VERSION 5.8 ;
BUSBITCHARS "[]" ;
DIVIDERCHAR "/" ;
UNITS
    DATABASE MICRONS 1000 ;
END UNITS

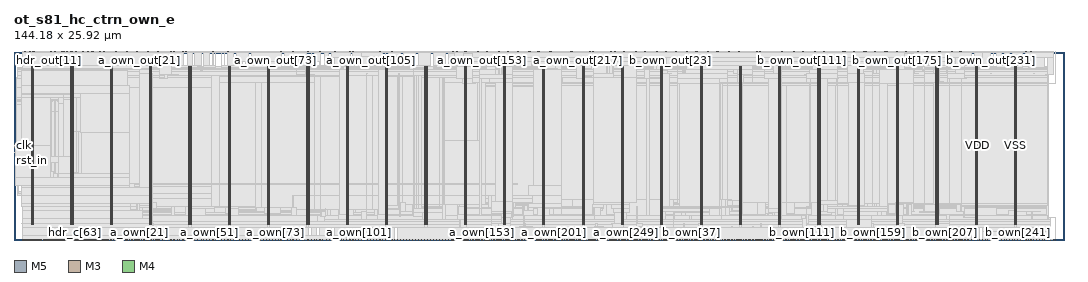
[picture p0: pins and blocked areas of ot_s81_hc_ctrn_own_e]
MACRO ot_s81_hc_ctrn_own_e
  FOREIGN ot_s81_hc_ctrn_own_e 0 0 ;
  CLASS BLOCK ;
  SIZE 144.18 BY 25.92 ;
  PIN a_own[0]
    DIRECTION INPUT ;
    USE SIGNAL ;
    PORT
      LAYER M5 ;
        RECT  13.008 0 13.032 0.084 ;
    END
  END a_own[0]
  PIN a_own[100]
    DIRECTION INPUT ;
    USE SIGNAL ;
    PORT
      LAYER M5 ;
        RECT  46.896 0 46.92 0.084 ;
    END
  END a_own[100]
  PIN a_own[101]
    DIRECTION INPUT ;
    USE SIGNAL ;
    PORT
      LAYER M3 ;
        RECT  47.304 0 47.322 0.038 ;
    END
  END a_own[101]
  PIN a_own[102]
    DIRECTION INPUT ;
    USE SIGNAL ;
    PORT
      LAYER M5 ;
        RECT  47.76 0 47.784 0.084 ;
    END
  END a_own[102]
  PIN a_own[103]
    DIRECTION INPUT ;
    USE SIGNAL ;
    PORT
      LAYER M3 ;
        RECT  48.168 0 48.186 0.038 ;
    END
  END a_own[103]
  PIN a_own[104]
    DIRECTION INPUT ;
    USE SIGNAL ;
    PORT
      LAYER M5 ;
        RECT  48.528 0 48.552 0.084 ;
    END
  END a_own[104]
  PIN a_own[105]
    DIRECTION INPUT ;
    USE SIGNAL ;
    PORT
      LAYER M3 ;
        RECT  48.96 0 48.978 0.038 ;
    END
  END a_own[105]
  PIN a_own[106]
    DIRECTION INPUT ;
    USE SIGNAL ;
    PORT
      LAYER M5 ;
        RECT  49.392 0 49.416 0.084 ;
    END
  END a_own[106]
  PIN a_own[107]
    DIRECTION INPUT ;
    USE SIGNAL ;
    PORT
      LAYER M3 ;
        RECT  49.824 0 49.842 0.038 ;
    END
  END a_own[107]
  PIN a_own[108]
    DIRECTION INPUT ;
    USE SIGNAL ;
    PORT
      LAYER M5 ;
        RECT  50.256 0 50.28 0.084 ;
    END
  END a_own[108]
  PIN a_own[109]
    DIRECTION INPUT ;
    USE SIGNAL ;
    PORT
      LAYER M3 ;
        RECT  50.58 0 50.598 0.038 ;
    END
  END a_own[109]
  PIN a_own[10]
    DIRECTION INPUT ;
    USE SIGNAL ;
    PORT
      LAYER M5 ;
        RECT  15.024 0 15.048 0.084 ;
    END
  END a_own[10]
  PIN a_own[110]
    DIRECTION INPUT ;
    USE SIGNAL ;
    PORT
      LAYER M5 ;
        RECT  51.024 0 51.048 0.084 ;
    END
  END a_own[110]
  PIN a_own[111]
    DIRECTION INPUT ;
    USE SIGNAL ;
    PORT
      LAYER M3 ;
        RECT  51.444 0 51.462 0.038 ;
    END
  END a_own[111]
  PIN a_own[112]
    DIRECTION INPUT ;
    USE SIGNAL ;
    PORT
      LAYER M5 ;
        RECT  51.888 0 51.912 0.084 ;
    END
  END a_own[112]
  PIN a_own[113]
    DIRECTION INPUT ;
    USE SIGNAL ;
    PORT
      LAYER M3 ;
        RECT  52.2 0 52.218 0.038 ;
    END
  END a_own[113]
  PIN a_own[114]
    DIRECTION INPUT ;
    USE SIGNAL ;
    PORT
      LAYER M5 ;
        RECT  52.656 0 52.68 0.084 ;
    END
  END a_own[114]
  PIN a_own[115]
    DIRECTION INPUT ;
    USE SIGNAL ;
    PORT
      LAYER M3 ;
        RECT  53.064 0 53.082 0.038 ;
    END
  END a_own[115]
  PIN a_own[116]
    DIRECTION INPUT ;
    USE SIGNAL ;
    PORT
      LAYER M5 ;
        RECT  53.52 0 53.544 0.084 ;
    END
  END a_own[116]
  PIN a_own[117]
    DIRECTION INPUT ;
    USE SIGNAL ;
    PORT
      LAYER M3 ;
        RECT  53.856 0 53.874 0.038 ;
    END
  END a_own[117]
  PIN a_own[118]
    DIRECTION INPUT ;
    USE SIGNAL ;
    PORT
      LAYER M5 ;
        RECT  54.288 0 54.312 0.084 ;
    END
  END a_own[118]
  PIN a_own[119]
    DIRECTION INPUT ;
    USE SIGNAL ;
    PORT
      LAYER M3 ;
        RECT  54.72 0 54.738 0.038 ;
    END
  END a_own[119]
  PIN a_own[11]
    DIRECTION INPUT ;
    USE SIGNAL ;
    PORT
      LAYER M3 ;
        RECT  15.264 0 15.282 0.038 ;
    END
  END a_own[11]
  PIN a_own[120]
    DIRECTION INPUT ;
    USE SIGNAL ;
    PORT
      LAYER M5 ;
        RECT  55.152 0 55.176 0.084 ;
    END
  END a_own[120]
  PIN a_own[121]
    DIRECTION INPUT ;
    USE SIGNAL ;
    PORT
      LAYER M3 ;
        RECT  55.476 0 55.494 0.038 ;
    END
  END a_own[121]
  PIN a_own[122]
    DIRECTION INPUT ;
    USE SIGNAL ;
    PORT
      LAYER M5 ;
        RECT  55.92 0 55.944 0.084 ;
    END
  END a_own[122]
  PIN a_own[123]
    DIRECTION INPUT ;
    USE SIGNAL ;
    PORT
      LAYER M3 ;
        RECT  56.34 0 56.358 0.038 ;
    END
  END a_own[123]
  PIN a_own[124]
    DIRECTION INPUT ;
    USE SIGNAL ;
    PORT
      LAYER M5 ;
        RECT  56.784 0 56.808 0.084 ;
    END
  END a_own[124]
  PIN a_own[125]
    DIRECTION INPUT ;
    USE SIGNAL ;
    PORT
      LAYER M3 ;
        RECT  57.204 0 57.222 0.038 ;
    END
  END a_own[125]
  PIN a_own[126]
    DIRECTION INPUT ;
    USE SIGNAL ;
    PORT
      LAYER M5 ;
        RECT  57.552 0 57.576 0.084 ;
    END
  END a_own[126]
  PIN a_own[127]
    DIRECTION INPUT ;
    USE SIGNAL ;
    PORT
      LAYER M3 ;
        RECT  57.96 0 57.978 0.038 ;
    END
  END a_own[127]
  PIN a_own[128]
    DIRECTION INPUT ;
    USE SIGNAL ;
    PORT
      LAYER M5 ;
        RECT  58.416 0 58.44 0.084 ;
    END
  END a_own[128]
  PIN a_own[129]
    DIRECTION INPUT ;
    USE SIGNAL ;
    PORT
      LAYER M3 ;
        RECT  58.824 0 58.842 0.038 ;
    END
  END a_own[129]
  PIN a_own[12]
    DIRECTION INPUT ;
    USE SIGNAL ;
    PORT
      LAYER M5 ;
        RECT  15.504 0 15.528 0.084 ;
    END
  END a_own[12]
  PIN a_own[130]
    DIRECTION INPUT ;
    USE SIGNAL ;
    PORT
      LAYER M5 ;
        RECT  59.184 0 59.208 0.084 ;
    END
  END a_own[130]
  PIN a_own[131]
    DIRECTION INPUT ;
    USE SIGNAL ;
    PORT
      LAYER M3 ;
        RECT  59.616 0 59.634 0.038 ;
    END
  END a_own[131]
  PIN a_own[132]
    DIRECTION INPUT ;
    USE SIGNAL ;
    PORT
      LAYER M5 ;
        RECT  60.048 0 60.072 0.084 ;
    END
  END a_own[132]
  PIN a_own[133]
    DIRECTION INPUT ;
    USE SIGNAL ;
    PORT
      LAYER M3 ;
        RECT  60.264 0 60.282 0.038 ;
    END
  END a_own[133]
  PIN a_own[134]
    DIRECTION INPUT ;
    USE SIGNAL ;
    PORT
      LAYER M5 ;
        RECT  60.432 0 60.456 0.084 ;
    END
  END a_own[134]
  PIN a_own[135]
    DIRECTION INPUT ;
    USE SIGNAL ;
    PORT
      LAYER M3 ;
        RECT  60.66 0 60.678 0.038 ;
    END
  END a_own[135]
  PIN a_own[136]
    DIRECTION INPUT ;
    USE SIGNAL ;
    PORT
      LAYER M5 ;
        RECT  60.816 0 60.84 0.084 ;
    END
  END a_own[136]
  PIN a_own[137]
    DIRECTION INPUT ;
    USE SIGNAL ;
    PORT
      LAYER M3 ;
        RECT  61.056 0 61.074 0.038 ;
    END
  END a_own[137]
  PIN a_own[138]
    DIRECTION INPUT ;
    USE SIGNAL ;
    PORT
      LAYER M5 ;
        RECT  61.296 0 61.32 0.084 ;
    END
  END a_own[138]
  PIN a_own[139]
    DIRECTION INPUT ;
    USE SIGNAL ;
    PORT
      LAYER M3 ;
        RECT  61.416 0 61.434 0.038 ;
    END
  END a_own[139]
  PIN a_own[13]
    DIRECTION INPUT ;
    USE SIGNAL ;
    PORT
      LAYER M3 ;
        RECT  15.624 0 15.642 0.038 ;
    END
  END a_own[13]
  PIN a_own[140]
    DIRECTION INPUT ;
    USE SIGNAL ;
    PORT
      LAYER M5 ;
        RECT  61.68 0 61.704 0.084 ;
    END
  END a_own[140]
  PIN a_own[141]
    DIRECTION INPUT ;
    USE SIGNAL ;
    PORT
      LAYER M3 ;
        RECT  61.92 0 61.938 0.038 ;
    END
  END a_own[141]
  PIN a_own[142]
    DIRECTION INPUT ;
    USE SIGNAL ;
    PORT
      LAYER M5 ;
        RECT  62.064 0 62.088 0.084 ;
    END
  END a_own[142]
  PIN a_own[143]
    DIRECTION INPUT ;
    USE SIGNAL ;
    PORT
      LAYER M3 ;
        RECT  62.28 0 62.298 0.038 ;
    END
  END a_own[143]
  PIN a_own[144]
    DIRECTION INPUT ;
    USE SIGNAL ;
    PORT
      LAYER M5 ;
        RECT  62.448 0 62.472 0.084 ;
    END
  END a_own[144]
  PIN a_own[145]
    DIRECTION INPUT ;
    USE SIGNAL ;
    PORT
      LAYER M3 ;
        RECT  62.676 0 62.694 0.038 ;
    END
  END a_own[145]
  PIN a_own[146]
    DIRECTION INPUT ;
    USE SIGNAL ;
    PORT
      LAYER M5 ;
        RECT  62.928 0 62.952 0.084 ;
    END
  END a_own[146]
  PIN a_own[147]
    DIRECTION INPUT ;
    USE SIGNAL ;
    PORT
      LAYER M3 ;
        RECT  63.072 0 63.09 0.038 ;
    END
  END a_own[147]
  PIN a_own[148]
    DIRECTION INPUT ;
    USE SIGNAL ;
    PORT
      LAYER M5 ;
        RECT  63.312 0 63.336 0.084 ;
    END
  END a_own[148]
  PIN a_own[149]
    DIRECTION INPUT ;
    USE SIGNAL ;
    PORT
      LAYER M3 ;
        RECT  63.54 0 63.558 0.038 ;
    END
  END a_own[149]
  PIN a_own[14]
    DIRECTION INPUT ;
    USE SIGNAL ;
    PORT
      LAYER M5 ;
        RECT  15.888 0 15.912 0.084 ;
    END
  END a_own[14]
  PIN a_own[150]
    DIRECTION INPUT ;
    USE SIGNAL ;
    PORT
      LAYER M5 ;
        RECT  63.696 0 63.72 0.084 ;
    END
  END a_own[150]
  PIN a_own[151]
    DIRECTION INPUT ;
    USE SIGNAL ;
    PORT
      LAYER M3 ;
        RECT  63.936 0 63.954 0.038 ;
    END
  END a_own[151]
  PIN a_own[152]
    DIRECTION INPUT ;
    USE SIGNAL ;
    PORT
      LAYER M5 ;
        RECT  64.176 0 64.2 0.084 ;
    END
  END a_own[152]
  PIN a_own[153]
    DIRECTION INPUT ;
    USE SIGNAL ;
    PORT
      LAYER M3 ;
        RECT  64.296 0 64.314 0.038 ;
    END
  END a_own[153]
  PIN a_own[154]
    DIRECTION INPUT ;
    USE SIGNAL ;
    PORT
      LAYER M5 ;
        RECT  64.56 0 64.584 0.084 ;
    END
  END a_own[154]
  PIN a_own[155]
    DIRECTION INPUT ;
    USE SIGNAL ;
    PORT
      LAYER M3 ;
        RECT  64.692 0 64.71 0.038 ;
    END
  END a_own[155]
  PIN a_own[156]
    DIRECTION INPUT ;
    USE SIGNAL ;
    PORT
      LAYER M5 ;
        RECT  64.944 0 64.968 0.084 ;
    END
  END a_own[156]
  PIN a_own[157]
    DIRECTION INPUT ;
    USE SIGNAL ;
    PORT
      LAYER M3 ;
        RECT  65.16 0 65.178 0.038 ;
    END
  END a_own[157]
  PIN a_own[158]
    DIRECTION INPUT ;
    USE SIGNAL ;
    PORT
      LAYER M5 ;
        RECT  65.328 0 65.352 0.084 ;
    END
  END a_own[158]
  PIN a_own[159]
    DIRECTION INPUT ;
    USE SIGNAL ;
    PORT
      LAYER M3 ;
        RECT  65.556 0 65.574 0.038 ;
    END
  END a_own[159]
  PIN a_own[15]
    DIRECTION INPUT ;
    USE SIGNAL ;
    PORT
      LAYER M3 ;
        RECT  16.128 0 16.146 0.038 ;
    END
  END a_own[15]
  PIN a_own[160]
    DIRECTION INPUT ;
    USE SIGNAL ;
    PORT
      LAYER M5 ;
        RECT  65.808 0 65.832 0.084 ;
    END
  END a_own[160]
  PIN a_own[161]
    DIRECTION INPUT ;
    USE SIGNAL ;
    PORT
      LAYER M3 ;
        RECT  65.952 0 65.97 0.038 ;
    END
  END a_own[161]
  PIN a_own[162]
    DIRECTION INPUT ;
    USE SIGNAL ;
    PORT
      LAYER M5 ;
        RECT  66.192 0 66.216 0.084 ;
    END
  END a_own[162]
  PIN a_own[163]
    DIRECTION INPUT ;
    USE SIGNAL ;
    PORT
      LAYER M3 ;
        RECT  66.42 0 66.438 0.038 ;
    END
  END a_own[163]
  PIN a_own[164]
    DIRECTION INPUT ;
    USE SIGNAL ;
    PORT
      LAYER M5 ;
        RECT  66.576 0 66.6 0.084 ;
    END
  END a_own[164]
  PIN a_own[165]
    DIRECTION INPUT ;
    USE SIGNAL ;
    PORT
      LAYER M3 ;
        RECT  66.816 0 66.834 0.038 ;
    END
  END a_own[165]
  PIN a_own[166]
    DIRECTION INPUT ;
    USE SIGNAL ;
    PORT
      LAYER M5 ;
        RECT  66.96 0 66.984 0.084 ;
    END
  END a_own[166]
  PIN a_own[167]
    DIRECTION INPUT ;
    USE SIGNAL ;
    PORT
      LAYER M3 ;
        RECT  67.176 0 67.194 0.038 ;
    END
  END a_own[167]
  PIN a_own[168]
    DIRECTION INPUT ;
    USE SIGNAL ;
    PORT
      LAYER M5 ;
        RECT  67.44 0 67.464 0.084 ;
    END
  END a_own[168]
  PIN a_own[169]
    DIRECTION INPUT ;
    USE SIGNAL ;
    PORT
      LAYER M3 ;
        RECT  67.572 0 67.59 0.038 ;
    END
  END a_own[169]
  PIN a_own[16]
    DIRECTION INPUT ;
    USE SIGNAL ;
    PORT
      LAYER M5 ;
        RECT  16.272 0 16.296 0.084 ;
    END
  END a_own[16]
  PIN a_own[170]
    DIRECTION INPUT ;
    USE SIGNAL ;
    PORT
      LAYER M5 ;
        RECT  67.824 0 67.848 0.084 ;
    END
  END a_own[170]
  PIN a_own[171]
    DIRECTION INPUT ;
    USE SIGNAL ;
    PORT
      LAYER M3 ;
        RECT  68.04 0 68.058 0.038 ;
    END
  END a_own[171]
  PIN a_own[172]
    DIRECTION INPUT ;
    USE SIGNAL ;
    PORT
      LAYER M5 ;
        RECT  68.208 0 68.232 0.084 ;
    END
  END a_own[172]
  PIN a_own[173]
    DIRECTION INPUT ;
    USE SIGNAL ;
    PORT
      LAYER M3 ;
        RECT  68.436 0 68.454 0.038 ;
    END
  END a_own[173]
  PIN a_own[174]
    DIRECTION INPUT ;
    USE SIGNAL ;
    PORT
      LAYER M5 ;
        RECT  68.592 0 68.616 0.084 ;
    END
  END a_own[174]
  PIN a_own[175]
    DIRECTION INPUT ;
    USE SIGNAL ;
    PORT
      LAYER M3 ;
        RECT  68.832 0 68.85 0.038 ;
    END
  END a_own[175]
  PIN a_own[176]
    DIRECTION INPUT ;
    USE SIGNAL ;
    PORT
      LAYER M5 ;
        RECT  69.072 0 69.096 0.084 ;
    END
  END a_own[176]
  PIN a_own[177]
    DIRECTION INPUT ;
    USE SIGNAL ;
    PORT
      LAYER M3 ;
        RECT  69.192 0 69.21 0.038 ;
    END
  END a_own[177]
  PIN a_own[178]
    DIRECTION INPUT ;
    USE SIGNAL ;
    PORT
      LAYER M5 ;
        RECT  69.456 0 69.48 0.084 ;
    END
  END a_own[178]
  PIN a_own[179]
    DIRECTION INPUT ;
    USE SIGNAL ;
    PORT
      LAYER M3 ;
        RECT  69.696 0 69.714 0.038 ;
    END
  END a_own[179]
  PIN a_own[17]
    DIRECTION INPUT ;
    USE SIGNAL ;
    PORT
      LAYER M3 ;
        RECT  16.488 0 16.506 0.038 ;
    END
  END a_own[17]
  PIN a_own[180]
    DIRECTION INPUT ;
    USE SIGNAL ;
    PORT
      LAYER M5 ;
        RECT  69.84 0 69.864 0.084 ;
    END
  END a_own[180]
  PIN a_own[181]
    DIRECTION INPUT ;
    USE SIGNAL ;
    PORT
      LAYER M3 ;
        RECT  70.056 0 70.074 0.038 ;
    END
  END a_own[181]
  PIN a_own[182]
    DIRECTION INPUT ;
    USE SIGNAL ;
    PORT
      LAYER M5 ;
        RECT  70.32 0 70.344 0.084 ;
    END
  END a_own[182]
  PIN a_own[183]
    DIRECTION INPUT ;
    USE SIGNAL ;
    PORT
      LAYER M3 ;
        RECT  70.452 0 70.47 0.038 ;
    END
  END a_own[183]
  PIN a_own[184]
    DIRECTION INPUT ;
    USE SIGNAL ;
    PORT
      LAYER M5 ;
        RECT  70.704 0 70.728 0.084 ;
    END
  END a_own[184]
  PIN a_own[185]
    DIRECTION INPUT ;
    USE SIGNAL ;
    PORT
      LAYER M3 ;
        RECT  70.848 0 70.866 0.038 ;
    END
  END a_own[185]
  PIN a_own[186]
    DIRECTION INPUT ;
    USE SIGNAL ;
    PORT
      LAYER M5 ;
        RECT  71.088 0 71.112 0.084 ;
    END
  END a_own[186]
  PIN a_own[187]
    DIRECTION INPUT ;
    USE SIGNAL ;
    PORT
      LAYER M3 ;
        RECT  71.316 0 71.334 0.038 ;
    END
  END a_own[187]
  PIN a_own[188]
    DIRECTION INPUT ;
    USE SIGNAL ;
    PORT
      LAYER M5 ;
        RECT  71.472 0 71.496 0.084 ;
    END
  END a_own[188]
  PIN a_own[189]
    DIRECTION INPUT ;
    USE SIGNAL ;
    PORT
      LAYER M3 ;
        RECT  71.712 0 71.73 0.038 ;
    END
  END a_own[189]
  PIN a_own[18]
    DIRECTION INPUT ;
    USE SIGNAL ;
    PORT
      LAYER M5 ;
        RECT  16.656 0 16.68 0.084 ;
    END
  END a_own[18]
  PIN a_own[190]
    DIRECTION INPUT ;
    USE SIGNAL ;
    PORT
      LAYER M5 ;
        RECT  71.952 0 71.976 0.084 ;
    END
  END a_own[190]
  PIN a_own[191]
    DIRECTION INPUT ;
    USE SIGNAL ;
    PORT
      LAYER M3 ;
        RECT  72.072 0 72.09 0.038 ;
    END
  END a_own[191]
  PIN a_own[192]
    DIRECTION INPUT ;
    USE SIGNAL ;
    PORT
      LAYER M5 ;
        RECT  72.336 0 72.36 0.084 ;
    END
  END a_own[192]
  PIN a_own[193]
    DIRECTION INPUT ;
    USE SIGNAL ;
    PORT
      LAYER M3 ;
        RECT  72.468 0 72.486 0.038 ;
    END
  END a_own[193]
  PIN a_own[194]
    DIRECTION INPUT ;
    USE SIGNAL ;
    PORT
      LAYER M5 ;
        RECT  72.72 0 72.744 0.084 ;
    END
  END a_own[194]
  PIN a_own[195]
    DIRECTION INPUT ;
    USE SIGNAL ;
    PORT
      LAYER M3 ;
        RECT  72.936 0 72.954 0.038 ;
    END
  END a_own[195]
  PIN a_own[196]
    DIRECTION INPUT ;
    USE SIGNAL ;
    PORT
      LAYER M5 ;
        RECT  73.104 0 73.128 0.084 ;
    END
  END a_own[196]
  PIN a_own[197]
    DIRECTION INPUT ;
    USE SIGNAL ;
    PORT
      LAYER M3 ;
        RECT  73.332 0 73.35 0.038 ;
    END
  END a_own[197]
  PIN a_own[198]
    DIRECTION INPUT ;
    USE SIGNAL ;
    PORT
      LAYER M5 ;
        RECT  73.584 0 73.608 0.084 ;
    END
  END a_own[198]
  PIN a_own[199]
    DIRECTION INPUT ;
    USE SIGNAL ;
    PORT
      LAYER M3 ;
        RECT  73.728 0 73.746 0.038 ;
    END
  END a_own[199]
  PIN a_own[19]
    DIRECTION INPUT ;
    USE SIGNAL ;
    PORT
      LAYER M3 ;
        RECT  16.884 0 16.902 0.038 ;
    END
  END a_own[19]
  PIN a_own[1]
    DIRECTION INPUT ;
    USE SIGNAL ;
    PORT
      LAYER M3 ;
        RECT  13.248 0 13.266 0.038 ;
    END
  END a_own[1]
  PIN a_own[200]
    DIRECTION INPUT ;
    USE SIGNAL ;
    PORT
      LAYER M5 ;
        RECT  73.968 0 73.992 0.084 ;
    END
  END a_own[200]
  PIN a_own[201]
    DIRECTION INPUT ;
    USE SIGNAL ;
    PORT
      LAYER M3 ;
        RECT  74.196 0 74.214 0.038 ;
    END
  END a_own[201]
  PIN a_own[202]
    DIRECTION INPUT ;
    USE SIGNAL ;
    PORT
      LAYER M5 ;
        RECT  74.352 0 74.376 0.084 ;
    END
  END a_own[202]
  PIN a_own[203]
    DIRECTION INPUT ;
    USE SIGNAL ;
    PORT
      LAYER M3 ;
        RECT  74.592 0 74.61 0.038 ;
    END
  END a_own[203]
  PIN a_own[204]
    DIRECTION INPUT ;
    USE SIGNAL ;
    PORT
      LAYER M5 ;
        RECT  74.736 0 74.76 0.084 ;
    END
  END a_own[204]
  PIN a_own[205]
    DIRECTION INPUT ;
    USE SIGNAL ;
    PORT
      LAYER M3 ;
        RECT  74.952 0 74.97 0.038 ;
    END
  END a_own[205]
  PIN a_own[206]
    DIRECTION INPUT ;
    USE SIGNAL ;
    PORT
      LAYER M5 ;
        RECT  75.216 0 75.24 0.084 ;
    END
  END a_own[206]
  PIN a_own[207]
    DIRECTION INPUT ;
    USE SIGNAL ;
    PORT
      LAYER M3 ;
        RECT  75.348 0 75.366 0.038 ;
    END
  END a_own[207]
  PIN a_own[208]
    DIRECTION INPUT ;
    USE SIGNAL ;
    PORT
      LAYER M5 ;
        RECT  75.6 0 75.624 0.084 ;
    END
  END a_own[208]
  PIN a_own[209]
    DIRECTION INPUT ;
    USE SIGNAL ;
    PORT
      LAYER M3 ;
        RECT  75.816 0 75.834 0.038 ;
    END
  END a_own[209]
  PIN a_own[20]
    DIRECTION INPUT ;
    USE SIGNAL ;
    PORT
      LAYER M5 ;
        RECT  17.136 0 17.16 0.084 ;
    END
  END a_own[20]
  PIN a_own[210]
    DIRECTION INPUT ;
    USE SIGNAL ;
    PORT
      LAYER M5 ;
        RECT  75.984 0 76.008 0.084 ;
    END
  END a_own[210]
  PIN a_own[211]
    DIRECTION INPUT ;
    USE SIGNAL ;
    PORT
      LAYER M3 ;
        RECT  76.212 0 76.23 0.038 ;
    END
  END a_own[211]
  PIN a_own[212]
    DIRECTION INPUT ;
    USE SIGNAL ;
    PORT
      LAYER M5 ;
        RECT  76.464 0 76.488 0.084 ;
    END
  END a_own[212]
  PIN a_own[213]
    DIRECTION INPUT ;
    USE SIGNAL ;
    PORT
      LAYER M3 ;
        RECT  76.608 0 76.626 0.038 ;
    END
  END a_own[213]
  PIN a_own[214]
    DIRECTION INPUT ;
    USE SIGNAL ;
    PORT
      LAYER M5 ;
        RECT  76.848 0 76.872 0.084 ;
    END
  END a_own[214]
  PIN a_own[215]
    DIRECTION INPUT ;
    USE SIGNAL ;
    PORT
      LAYER M3 ;
        RECT  76.968 0 76.986 0.038 ;
    END
  END a_own[215]
  PIN a_own[216]
    DIRECTION INPUT ;
    USE SIGNAL ;
    PORT
      LAYER M5 ;
        RECT  77.232 0 77.256 0.084 ;
    END
  END a_own[216]
  PIN a_own[217]
    DIRECTION INPUT ;
    USE SIGNAL ;
    PORT
      LAYER M3 ;
        RECT  77.472 0 77.49 0.038 ;
    END
  END a_own[217]
  PIN a_own[218]
    DIRECTION INPUT ;
    USE SIGNAL ;
    PORT
      LAYER M5 ;
        RECT  77.616 0 77.64 0.084 ;
    END
  END a_own[218]
  PIN a_own[219]
    DIRECTION INPUT ;
    USE SIGNAL ;
    PORT
      LAYER M3 ;
        RECT  77.832 0 77.85 0.038 ;
    END
  END a_own[219]
  PIN a_own[21]
    DIRECTION INPUT ;
    USE SIGNAL ;
    PORT
      LAYER M3 ;
        RECT  17.28 0 17.298 0.038 ;
    END
  END a_own[21]
  PIN a_own[220]
    DIRECTION INPUT ;
    USE SIGNAL ;
    PORT
      LAYER M5 ;
        RECT  78.096 0 78.12 0.084 ;
    END
  END a_own[220]
  PIN a_own[221]
    DIRECTION INPUT ;
    USE SIGNAL ;
    PORT
      LAYER M3 ;
        RECT  78.228 0 78.246 0.038 ;
    END
  END a_own[221]
  PIN a_own[222]
    DIRECTION INPUT ;
    USE SIGNAL ;
    PORT
      LAYER M5 ;
        RECT  78.48 0 78.504 0.084 ;
    END
  END a_own[222]
  PIN a_own[223]
    DIRECTION INPUT ;
    USE SIGNAL ;
    PORT
      LAYER M3 ;
        RECT  78.624 0 78.642 0.038 ;
    END
  END a_own[223]
  PIN a_own[224]
    DIRECTION INPUT ;
    USE SIGNAL ;
    PORT
      LAYER M5 ;
        RECT  78.864 0 78.888 0.084 ;
    END
  END a_own[224]
  PIN a_own[225]
    DIRECTION INPUT ;
    USE SIGNAL ;
    PORT
      LAYER M3 ;
        RECT  79.092 0 79.11 0.038 ;
    END
  END a_own[225]
  PIN a_own[226]
    DIRECTION INPUT ;
    USE SIGNAL ;
    PORT
      LAYER M5 ;
        RECT  79.248 0 79.272 0.084 ;
    END
  END a_own[226]
  PIN a_own[227]
    DIRECTION INPUT ;
    USE SIGNAL ;
    PORT
      LAYER M3 ;
        RECT  79.488 0 79.506 0.038 ;
    END
  END a_own[227]
  PIN a_own[228]
    DIRECTION INPUT ;
    USE SIGNAL ;
    PORT
      LAYER M5 ;
        RECT  79.728 0 79.752 0.084 ;
    END
  END a_own[228]
  PIN a_own[229]
    DIRECTION INPUT ;
    USE SIGNAL ;
    PORT
      LAYER M3 ;
        RECT  79.848 0 79.866 0.038 ;
    END
  END a_own[229]
  PIN a_own[22]
    DIRECTION INPUT ;
    USE SIGNAL ;
    PORT
      LAYER M5 ;
        RECT  17.52 0 17.544 0.084 ;
    END
  END a_own[22]
  PIN a_own[230]
    DIRECTION INPUT ;
    USE SIGNAL ;
    PORT
      LAYER M5 ;
        RECT  80.112 0 80.136 0.084 ;
    END
  END a_own[230]
  PIN a_own[231]
    DIRECTION INPUT ;
    USE SIGNAL ;
    PORT
      LAYER M3 ;
        RECT  80.352 0 80.37 0.038 ;
    END
  END a_own[231]
  PIN a_own[232]
    DIRECTION INPUT ;
    USE SIGNAL ;
    PORT
      LAYER M5 ;
        RECT  80.496 0 80.52 0.084 ;
    END
  END a_own[232]
  PIN a_own[233]
    DIRECTION INPUT ;
    USE SIGNAL ;
    PORT
      LAYER M3 ;
        RECT  80.712 0 80.73 0.038 ;
    END
  END a_own[233]
  PIN a_own[234]
    DIRECTION INPUT ;
    USE SIGNAL ;
    PORT
      LAYER M5 ;
        RECT  80.88 0 80.904 0.084 ;
    END
  END a_own[234]
  PIN a_own[235]
    DIRECTION INPUT ;
    USE SIGNAL ;
    PORT
      LAYER M3 ;
        RECT  81.108 0 81.126 0.038 ;
    END
  END a_own[235]
  PIN a_own[236]
    DIRECTION INPUT ;
    USE SIGNAL ;
    PORT
      LAYER M5 ;
        RECT  81.36 0 81.384 0.084 ;
    END
  END a_own[236]
  PIN a_own[237]
    DIRECTION INPUT ;
    USE SIGNAL ;
    PORT
      LAYER M3 ;
        RECT  81.504 0 81.522 0.038 ;
    END
  END a_own[237]
  PIN a_own[238]
    DIRECTION INPUT ;
    USE SIGNAL ;
    PORT
      LAYER M5 ;
        RECT  81.744 0 81.768 0.084 ;
    END
  END a_own[238]
  PIN a_own[239]
    DIRECTION INPUT ;
    USE SIGNAL ;
    PORT
      LAYER M3 ;
        RECT  81.972 0 81.99 0.038 ;
    END
  END a_own[239]
  PIN a_own[23]
    DIRECTION INPUT ;
    USE SIGNAL ;
    PORT
      LAYER M3 ;
        RECT  17.748 0 17.766 0.038 ;
    END
  END a_own[23]
  PIN a_own[240]
    DIRECTION INPUT ;
    USE SIGNAL ;
    PORT
      LAYER M5 ;
        RECT  82.128 0 82.152 0.084 ;
    END
  END a_own[240]
  PIN a_own[241]
    DIRECTION INPUT ;
    USE SIGNAL ;
    PORT
      LAYER M3 ;
        RECT  82.368 0 82.386 0.038 ;
    END
  END a_own[241]
  PIN a_own[242]
    DIRECTION INPUT ;
    USE SIGNAL ;
    PORT
      LAYER M5 ;
        RECT  82.512 0 82.536 0.084 ;
    END
  END a_own[242]
  PIN a_own[243]
    DIRECTION INPUT ;
    USE SIGNAL ;
    PORT
      LAYER M3 ;
        RECT  82.728 0 82.746 0.038 ;
    END
  END a_own[243]
  PIN a_own[244]
    DIRECTION INPUT ;
    USE SIGNAL ;
    PORT
      LAYER M5 ;
        RECT  82.992 0 83.016 0.084 ;
    END
  END a_own[244]
  PIN a_own[245]
    DIRECTION INPUT ;
    USE SIGNAL ;
    PORT
      LAYER M3 ;
        RECT  83.124 0 83.142 0.038 ;
    END
  END a_own[245]
  PIN a_own[246]
    DIRECTION INPUT ;
    USE SIGNAL ;
    PORT
      LAYER M5 ;
        RECT  83.376 0 83.4 0.084 ;
    END
  END a_own[246]
  PIN a_own[247]
    DIRECTION INPUT ;
    USE SIGNAL ;
    PORT
      LAYER M3 ;
        RECT  83.592 0 83.61 0.038 ;
    END
  END a_own[247]
  PIN a_own[248]
    DIRECTION INPUT ;
    USE SIGNAL ;
    PORT
      LAYER M5 ;
        RECT  83.76 0 83.784 0.084 ;
    END
  END a_own[248]
  PIN a_own[249]
    DIRECTION INPUT ;
    USE SIGNAL ;
    PORT
      LAYER M3 ;
        RECT  83.988 0 84.006 0.038 ;
    END
  END a_own[249]
  PIN a_own[24]
    DIRECTION INPUT ;
    USE SIGNAL ;
    PORT
      LAYER M5 ;
        RECT  17.904 0 17.928 0.084 ;
    END
  END a_own[24]
  PIN a_own[250]
    DIRECTION INPUT ;
    USE SIGNAL ;
    PORT
      LAYER M5 ;
        RECT  84.24 0 84.264 0.084 ;
    END
  END a_own[250]
  PIN a_own[251]
    DIRECTION INPUT ;
    USE SIGNAL ;
    PORT
      LAYER M3 ;
        RECT  84.384 0 84.402 0.038 ;
    END
  END a_own[251]
  PIN a_own[252]
    DIRECTION INPUT ;
    USE SIGNAL ;
    PORT
      LAYER M5 ;
        RECT  84.624 0 84.648 0.084 ;
    END
  END a_own[252]
  PIN a_own[253]
    DIRECTION INPUT ;
    USE SIGNAL ;
    PORT
      LAYER M3 ;
        RECT  84.744 0 84.762 0.038 ;
    END
  END a_own[253]
  PIN a_own[254]
    DIRECTION INPUT ;
    USE SIGNAL ;
    PORT
      LAYER M5 ;
        RECT  85.008 0 85.032 0.084 ;
    END
  END a_own[254]
  PIN a_own[255]
    DIRECTION INPUT ;
    USE SIGNAL ;
    PORT
      LAYER M3 ;
        RECT  85.248 0 85.266 0.038 ;
    END
  END a_own[255]
  PIN a_own[25]
    DIRECTION INPUT ;
    USE SIGNAL ;
    PORT
      LAYER M3 ;
        RECT  18.144 0 18.162 0.038 ;
    END
  END a_own[25]
  PIN a_own[26]
    DIRECTION INPUT ;
    USE SIGNAL ;
    PORT
      LAYER M5 ;
        RECT  18.384 0 18.408 0.084 ;
    END
  END a_own[26]
  PIN a_own[27]
    DIRECTION INPUT ;
    USE SIGNAL ;
    PORT
      LAYER M3 ;
        RECT  18.504 0 18.522 0.038 ;
    END
  END a_own[27]
  PIN a_own[28]
    DIRECTION INPUT ;
    USE SIGNAL ;
    PORT
      LAYER M5 ;
        RECT  18.768 0 18.792 0.084 ;
    END
  END a_own[28]
  PIN a_own[29]
    DIRECTION INPUT ;
    USE SIGNAL ;
    PORT
      LAYER M3 ;
        RECT  18.9 0 18.918 0.038 ;
    END
  END a_own[29]
  PIN a_own[2]
    DIRECTION INPUT ;
    USE SIGNAL ;
    PORT
      LAYER M5 ;
        RECT  13.392 0 13.416 0.084 ;
    END
  END a_own[2]
  PIN a_own[30]
    DIRECTION INPUT ;
    USE SIGNAL ;
    PORT
      LAYER M5 ;
        RECT  19.152 0 19.176 0.084 ;
    END
  END a_own[30]
  PIN a_own[31]
    DIRECTION INPUT ;
    USE SIGNAL ;
    PORT
      LAYER M3 ;
        RECT  19.368 0 19.386 0.038 ;
    END
  END a_own[31]
  PIN a_own[32]
    DIRECTION INPUT ;
    USE SIGNAL ;
    PORT
      LAYER M5 ;
        RECT  19.536 0 19.56 0.084 ;
    END
  END a_own[32]
  PIN a_own[33]
    DIRECTION INPUT ;
    USE SIGNAL ;
    PORT
      LAYER M3 ;
        RECT  19.764 0 19.782 0.038 ;
    END
  END a_own[33]
  PIN a_own[34]
    DIRECTION INPUT ;
    USE SIGNAL ;
    PORT
      LAYER M5 ;
        RECT  20.016 0 20.04 0.084 ;
    END
  END a_own[34]
  PIN a_own[35]
    DIRECTION INPUT ;
    USE SIGNAL ;
    PORT
      LAYER M3 ;
        RECT  20.34 0 20.358 0.038 ;
    END
  END a_own[35]
  PIN a_own[36]
    DIRECTION INPUT ;
    USE SIGNAL ;
    PORT
      LAYER M5 ;
        RECT  20.688 0 20.712 0.084 ;
    END
  END a_own[36]
  PIN a_own[37]
    DIRECTION INPUT ;
    USE SIGNAL ;
    PORT
      LAYER M3 ;
        RECT  21.096 0 21.114 0.038 ;
    END
  END a_own[37]
  PIN a_own[38]
    DIRECTION INPUT ;
    USE SIGNAL ;
    PORT
      LAYER M5 ;
        RECT  21.552 0 21.576 0.084 ;
    END
  END a_own[38]
  PIN a_own[39]
    DIRECTION INPUT ;
    USE SIGNAL ;
    PORT
      LAYER M3 ;
        RECT  21.96 0 21.978 0.038 ;
    END
  END a_own[39]
  PIN a_own[3]
    DIRECTION INPUT ;
    USE SIGNAL ;
    PORT
      LAYER M3 ;
        RECT  13.608 0 13.626 0.038 ;
    END
  END a_own[3]
  PIN a_own[40]
    DIRECTION INPUT ;
    USE SIGNAL ;
    PORT
      LAYER M5 ;
        RECT  22.416 0 22.44 0.084 ;
    END
  END a_own[40]
  PIN a_own[41]
    DIRECTION INPUT ;
    USE SIGNAL ;
    PORT
      LAYER M3 ;
        RECT  22.752 0 22.77 0.038 ;
    END
  END a_own[41]
  PIN a_own[42]
    DIRECTION INPUT ;
    USE SIGNAL ;
    PORT
      LAYER M5 ;
        RECT  23.184 0 23.208 0.084 ;
    END
  END a_own[42]
  PIN a_own[43]
    DIRECTION INPUT ;
    USE SIGNAL ;
    PORT
      LAYER M3 ;
        RECT  23.616 0 23.634 0.038 ;
    END
  END a_own[43]
  PIN a_own[44]
    DIRECTION INPUT ;
    USE SIGNAL ;
    PORT
      LAYER M5 ;
        RECT  24.048 0 24.072 0.084 ;
    END
  END a_own[44]
  PIN a_own[45]
    DIRECTION INPUT ;
    USE SIGNAL ;
    PORT
      LAYER M3 ;
        RECT  24.372 0 24.39 0.038 ;
    END
  END a_own[45]
  PIN a_own[46]
    DIRECTION INPUT ;
    USE SIGNAL ;
    PORT
      LAYER M5 ;
        RECT  24.816 0 24.84 0.084 ;
    END
  END a_own[46]
  PIN a_own[47]
    DIRECTION INPUT ;
    USE SIGNAL ;
    PORT
      LAYER M3 ;
        RECT  25.236 0 25.254 0.038 ;
    END
  END a_own[47]
  PIN a_own[48]
    DIRECTION INPUT ;
    USE SIGNAL ;
    PORT
      LAYER M5 ;
        RECT  25.68 0 25.704 0.084 ;
    END
  END a_own[48]
  PIN a_own[49]
    DIRECTION INPUT ;
    USE SIGNAL ;
    PORT
      LAYER M3 ;
        RECT  25.992 0 26.01 0.038 ;
    END
  END a_own[49]
  PIN a_own[4]
    DIRECTION INPUT ;
    USE SIGNAL ;
    PORT
      LAYER M5 ;
        RECT  13.872 0 13.896 0.084 ;
    END
  END a_own[4]
  PIN a_own[50]
    DIRECTION INPUT ;
    USE SIGNAL ;
    PORT
      LAYER M5 ;
        RECT  26.448 0 26.472 0.084 ;
    END
  END a_own[50]
  PIN a_own[51]
    DIRECTION INPUT ;
    USE SIGNAL ;
    PORT
      LAYER M3 ;
        RECT  26.856 0 26.874 0.038 ;
    END
  END a_own[51]
  PIN a_own[52]
    DIRECTION INPUT ;
    USE SIGNAL ;
    PORT
      LAYER M5 ;
        RECT  27.312 0 27.336 0.084 ;
    END
  END a_own[52]
  PIN a_own[53]
    DIRECTION INPUT ;
    USE SIGNAL ;
    PORT
      LAYER M3 ;
        RECT  27.648 0 27.666 0.038 ;
    END
  END a_own[53]
  PIN a_own[54]
    DIRECTION INPUT ;
    USE SIGNAL ;
    PORT
      LAYER M5 ;
        RECT  28.08 0 28.104 0.084 ;
    END
  END a_own[54]
  PIN a_own[55]
    DIRECTION INPUT ;
    USE SIGNAL ;
    PORT
      LAYER M3 ;
        RECT  28.512 0 28.53 0.038 ;
    END
  END a_own[55]
  PIN a_own[56]
    DIRECTION INPUT ;
    USE SIGNAL ;
    PORT
      LAYER M5 ;
        RECT  28.944 0 28.968 0.084 ;
    END
  END a_own[56]
  PIN a_own[57]
    DIRECTION INPUT ;
    USE SIGNAL ;
    PORT
      LAYER M3 ;
        RECT  29.376 0 29.394 0.038 ;
    END
  END a_own[57]
  PIN a_own[58]
    DIRECTION INPUT ;
    USE SIGNAL ;
    PORT
      LAYER M5 ;
        RECT  29.712 0 29.736 0.084 ;
    END
  END a_own[58]
  PIN a_own[59]
    DIRECTION INPUT ;
    USE SIGNAL ;
    PORT
      LAYER M3 ;
        RECT  30.132 0 30.15 0.038 ;
    END
  END a_own[59]
  PIN a_own[5]
    DIRECTION INPUT ;
    USE SIGNAL ;
    PORT
      LAYER M3 ;
        RECT  14.004 0 14.022 0.038 ;
    END
  END a_own[5]
  PIN a_own[60]
    DIRECTION INPUT ;
    USE SIGNAL ;
    PORT
      LAYER M5 ;
        RECT  30.576 0 30.6 0.084 ;
    END
  END a_own[60]
  PIN a_own[61]
    DIRECTION INPUT ;
    USE SIGNAL ;
    PORT
      LAYER M3 ;
        RECT  30.996 0 31.014 0.038 ;
    END
  END a_own[61]
  PIN a_own[62]
    DIRECTION INPUT ;
    USE SIGNAL ;
    PORT
      LAYER M5 ;
        RECT  31.344 0 31.368 0.084 ;
    END
  END a_own[62]
  PIN a_own[63]
    DIRECTION INPUT ;
    USE SIGNAL ;
    PORT
      LAYER M3 ;
        RECT  31.752 0 31.77 0.038 ;
    END
  END a_own[63]
  PIN a_own[64]
    DIRECTION INPUT ;
    USE SIGNAL ;
    PORT
      LAYER M5 ;
        RECT  32.208 0 32.232 0.084 ;
    END
  END a_own[64]
  PIN a_own[65]
    DIRECTION INPUT ;
    USE SIGNAL ;
    PORT
      LAYER M3 ;
        RECT  32.616 0 32.634 0.038 ;
    END
  END a_own[65]
  PIN a_own[66]
    DIRECTION INPUT ;
    USE SIGNAL ;
    PORT
      LAYER M5 ;
        RECT  32.976 0 33 0.084 ;
    END
  END a_own[66]
  PIN a_own[67]
    DIRECTION INPUT ;
    USE SIGNAL ;
    PORT
      LAYER M3 ;
        RECT  33.408 0 33.426 0.038 ;
    END
  END a_own[67]
  PIN a_own[68]
    DIRECTION INPUT ;
    USE SIGNAL ;
    PORT
      LAYER M5 ;
        RECT  33.84 0 33.864 0.084 ;
    END
  END a_own[68]
  PIN a_own[69]
    DIRECTION INPUT ;
    USE SIGNAL ;
    PORT
      LAYER M3 ;
        RECT  34.272 0 34.29 0.038 ;
    END
  END a_own[69]
  PIN a_own[6]
    DIRECTION INPUT ;
    USE SIGNAL ;
    PORT
      LAYER M5 ;
        RECT  14.256 0 14.28 0.084 ;
    END
  END a_own[6]
  PIN a_own[70]
    DIRECTION INPUT ;
    USE SIGNAL ;
    PORT
      LAYER M5 ;
        RECT  34.608 0 34.632 0.084 ;
    END
  END a_own[70]
  PIN a_own[71]
    DIRECTION INPUT ;
    USE SIGNAL ;
    PORT
      LAYER M3 ;
        RECT  35.028 0 35.046 0.038 ;
    END
  END a_own[71]
  PIN a_own[72]
    DIRECTION INPUT ;
    USE SIGNAL ;
    PORT
      LAYER M5 ;
        RECT  35.472 0 35.496 0.084 ;
    END
  END a_own[72]
  PIN a_own[73]
    DIRECTION INPUT ;
    USE SIGNAL ;
    PORT
      LAYER M3 ;
        RECT  35.892 0 35.91 0.038 ;
    END
  END a_own[73]
  PIN a_own[74]
    DIRECTION INPUT ;
    USE SIGNAL ;
    PORT
      LAYER M5 ;
        RECT  36.336 0 36.36 0.084 ;
    END
  END a_own[74]
  PIN a_own[75]
    DIRECTION INPUT ;
    USE SIGNAL ;
    PORT
      LAYER M3 ;
        RECT  36.648 0 36.666 0.038 ;
    END
  END a_own[75]
  PIN a_own[76]
    DIRECTION INPUT ;
    USE SIGNAL ;
    PORT
      LAYER M5 ;
        RECT  37.104 0 37.128 0.084 ;
    END
  END a_own[76]
  PIN a_own[77]
    DIRECTION INPUT ;
    USE SIGNAL ;
    PORT
      LAYER M3 ;
        RECT  37.512 0 37.53 0.038 ;
    END
  END a_own[77]
  PIN a_own[78]
    DIRECTION INPUT ;
    USE SIGNAL ;
    PORT
      LAYER M5 ;
        RECT  37.968 0 37.992 0.084 ;
    END
  END a_own[78]
  PIN a_own[79]
    DIRECTION INPUT ;
    USE SIGNAL ;
    PORT
      LAYER M3 ;
        RECT  38.304 0 38.322 0.038 ;
    END
  END a_own[79]
  PIN a_own[7]
    DIRECTION INPUT ;
    USE SIGNAL ;
    PORT
      LAYER M3 ;
        RECT  14.4 0 14.418 0.038 ;
    END
  END a_own[7]
  PIN a_own[80]
    DIRECTION INPUT ;
    USE SIGNAL ;
    PORT
      LAYER M5 ;
        RECT  38.736 0 38.76 0.084 ;
    END
  END a_own[80]
  PIN a_own[81]
    DIRECTION INPUT ;
    USE SIGNAL ;
    PORT
      LAYER M3 ;
        RECT  39.168 0 39.186 0.038 ;
    END
  END a_own[81]
  PIN a_own[82]
    DIRECTION INPUT ;
    USE SIGNAL ;
    PORT
      LAYER M5 ;
        RECT  39.6 0 39.624 0.084 ;
    END
  END a_own[82]
  PIN a_own[83]
    DIRECTION INPUT ;
    USE SIGNAL ;
    PORT
      LAYER M3 ;
        RECT  39.924 0 39.942 0.038 ;
    END
  END a_own[83]
  PIN a_own[84]
    DIRECTION INPUT ;
    USE SIGNAL ;
    PORT
      LAYER M5 ;
        RECT  40.368 0 40.392 0.084 ;
    END
  END a_own[84]
  PIN a_own[85]
    DIRECTION INPUT ;
    USE SIGNAL ;
    PORT
      LAYER M3 ;
        RECT  40.788 0 40.806 0.038 ;
    END
  END a_own[85]
  PIN a_own[86]
    DIRECTION INPUT ;
    USE SIGNAL ;
    PORT
      LAYER M5 ;
        RECT  41.232 0 41.256 0.084 ;
    END
  END a_own[86]
  PIN a_own[87]
    DIRECTION INPUT ;
    USE SIGNAL ;
    PORT
      LAYER M3 ;
        RECT  41.544 0 41.562 0.038 ;
    END
  END a_own[87]
  PIN a_own[88]
    DIRECTION INPUT ;
    USE SIGNAL ;
    PORT
      LAYER M5 ;
        RECT  42 0 42.024 0.084 ;
    END
  END a_own[88]
  PIN a_own[89]
    DIRECTION INPUT ;
    USE SIGNAL ;
    PORT
      LAYER M3 ;
        RECT  42.408 0 42.426 0.038 ;
    END
  END a_own[89]
  PIN a_own[8]
    DIRECTION INPUT ;
    USE SIGNAL ;
    PORT
      LAYER M5 ;
        RECT  14.64 0 14.664 0.084 ;
    END
  END a_own[8]
  PIN a_own[90]
    DIRECTION INPUT ;
    USE SIGNAL ;
    PORT
      LAYER M5 ;
        RECT  42.864 0 42.888 0.084 ;
    END
  END a_own[90]
  PIN a_own[91]
    DIRECTION INPUT ;
    USE SIGNAL ;
    PORT
      LAYER M3 ;
        RECT  43.272 0 43.29 0.038 ;
    END
  END a_own[91]
  PIN a_own[92]
    DIRECTION INPUT ;
    USE SIGNAL ;
    PORT
      LAYER M5 ;
        RECT  43.632 0 43.656 0.084 ;
    END
  END a_own[92]
  PIN a_own[93]
    DIRECTION INPUT ;
    USE SIGNAL ;
    PORT
      LAYER M3 ;
        RECT  44.064 0 44.082 0.038 ;
    END
  END a_own[93]
  PIN a_own[94]
    DIRECTION INPUT ;
    USE SIGNAL ;
    PORT
      LAYER M5 ;
        RECT  44.496 0 44.52 0.084 ;
    END
  END a_own[94]
  PIN a_own[95]
    DIRECTION INPUT ;
    USE SIGNAL ;
    PORT
      LAYER M3 ;
        RECT  44.928 0 44.946 0.038 ;
    END
  END a_own[95]
  PIN a_own[96]
    DIRECTION INPUT ;
    USE SIGNAL ;
    PORT
      LAYER M5 ;
        RECT  45.264 0 45.288 0.084 ;
    END
  END a_own[96]
  PIN a_own[97]
    DIRECTION INPUT ;
    USE SIGNAL ;
    PORT
      LAYER M3 ;
        RECT  45.684 0 45.702 0.038 ;
    END
  END a_own[97]
  PIN a_own[98]
    DIRECTION INPUT ;
    USE SIGNAL ;
    PORT
      LAYER M5 ;
        RECT  46.128 0 46.152 0.084 ;
    END
  END a_own[98]
  PIN a_own[99]
    DIRECTION INPUT ;
    USE SIGNAL ;
    PORT
      LAYER M3 ;
        RECT  46.548 0 46.566 0.038 ;
    END
  END a_own[99]
  PIN a_own[9]
    DIRECTION INPUT ;
    USE SIGNAL ;
    PORT
      LAYER M3 ;
        RECT  14.868 0 14.886 0.038 ;
    END
  END a_own[9]
  PIN a_own_out[0]
    DIRECTION OUTPUT ;
    USE SIGNAL ;
    PORT
      LAYER M5 ;
        RECT  13.008 25.836 13.032 25.92 ;
    END
  END a_own_out[0]
  PIN a_own_out[100]
    DIRECTION OUTPUT ;
    USE SIGNAL ;
    PORT
      LAYER M5 ;
        RECT  46.896 25.836 46.92 25.92 ;
    END
  END a_own_out[100]
  PIN a_own_out[101]
    DIRECTION OUTPUT ;
    USE SIGNAL ;
    PORT
      LAYER M3 ;
        RECT  47.304 25.882 47.322 25.92 ;
    END
  END a_own_out[101]
  PIN a_own_out[102]
    DIRECTION OUTPUT ;
    USE SIGNAL ;
    PORT
      LAYER M5 ;
        RECT  47.76 25.836 47.784 25.92 ;
    END
  END a_own_out[102]
  PIN a_own_out[103]
    DIRECTION OUTPUT ;
    USE SIGNAL ;
    PORT
      LAYER M3 ;
        RECT  48.168 25.882 48.186 25.92 ;
    END
  END a_own_out[103]
  PIN a_own_out[104]
    DIRECTION OUTPUT ;
    USE SIGNAL ;
    PORT
      LAYER M5 ;
        RECT  48.528 25.836 48.552 25.92 ;
    END
  END a_own_out[104]
  PIN a_own_out[105]
    DIRECTION OUTPUT ;
    USE SIGNAL ;
    PORT
      LAYER M3 ;
        RECT  48.96 25.882 48.978 25.92 ;
    END
  END a_own_out[105]
  PIN a_own_out[106]
    DIRECTION OUTPUT ;
    USE SIGNAL ;
    PORT
      LAYER M5 ;
        RECT  49.392 25.836 49.416 25.92 ;
    END
  END a_own_out[106]
  PIN a_own_out[107]
    DIRECTION OUTPUT ;
    USE SIGNAL ;
    PORT
      LAYER M3 ;
        RECT  49.824 25.882 49.842 25.92 ;
    END
  END a_own_out[107]
  PIN a_own_out[108]
    DIRECTION OUTPUT ;
    USE SIGNAL ;
    PORT
      LAYER M5 ;
        RECT  50.256 25.836 50.28 25.92 ;
    END
  END a_own_out[108]
  PIN a_own_out[109]
    DIRECTION OUTPUT ;
    USE SIGNAL ;
    PORT
      LAYER M3 ;
        RECT  50.58 25.882 50.598 25.92 ;
    END
  END a_own_out[109]
  PIN a_own_out[10]
    DIRECTION OUTPUT ;
    USE SIGNAL ;
    PORT
      LAYER M5 ;
        RECT  15.024 25.836 15.048 25.92 ;
    END
  END a_own_out[10]
  PIN a_own_out[110]
    DIRECTION OUTPUT ;
    USE SIGNAL ;
    PORT
      LAYER M5 ;
        RECT  51.024 25.836 51.048 25.92 ;
    END
  END a_own_out[110]
  PIN a_own_out[111]
    DIRECTION OUTPUT ;
    USE SIGNAL ;
    PORT
      LAYER M3 ;
        RECT  51.444 25.882 51.462 25.92 ;
    END
  END a_own_out[111]
  PIN a_own_out[112]
    DIRECTION OUTPUT ;
    USE SIGNAL ;
    PORT
      LAYER M5 ;
        RECT  51.888 25.836 51.912 25.92 ;
    END
  END a_own_out[112]
  PIN a_own_out[113]
    DIRECTION OUTPUT ;
    USE SIGNAL ;
    PORT
      LAYER M3 ;
        RECT  52.2 25.882 52.218 25.92 ;
    END
  END a_own_out[113]
  PIN a_own_out[114]
    DIRECTION OUTPUT ;
    USE SIGNAL ;
    PORT
      LAYER M5 ;
        RECT  52.656 25.836 52.68 25.92 ;
    END
  END a_own_out[114]
  PIN a_own_out[115]
    DIRECTION OUTPUT ;
    USE SIGNAL ;
    PORT
      LAYER M3 ;
        RECT  53.064 25.882 53.082 25.92 ;
    END
  END a_own_out[115]
  PIN a_own_out[116]
    DIRECTION OUTPUT ;
    USE SIGNAL ;
    PORT
      LAYER M5 ;
        RECT  53.52 25.836 53.544 25.92 ;
    END
  END a_own_out[116]
  PIN a_own_out[117]
    DIRECTION OUTPUT ;
    USE SIGNAL ;
    PORT
      LAYER M3 ;
        RECT  53.856 25.882 53.874 25.92 ;
    END
  END a_own_out[117]
  PIN a_own_out[118]
    DIRECTION OUTPUT ;
    USE SIGNAL ;
    PORT
      LAYER M5 ;
        RECT  54.288 25.836 54.312 25.92 ;
    END
  END a_own_out[118]
  PIN a_own_out[119]
    DIRECTION OUTPUT ;
    USE SIGNAL ;
    PORT
      LAYER M3 ;
        RECT  54.72 25.882 54.738 25.92 ;
    END
  END a_own_out[119]
  PIN a_own_out[11]
    DIRECTION OUTPUT ;
    USE SIGNAL ;
    PORT
      LAYER M3 ;
        RECT  15.264 25.882 15.282 25.92 ;
    END
  END a_own_out[11]
  PIN a_own_out[120]
    DIRECTION OUTPUT ;
    USE SIGNAL ;
    PORT
      LAYER M5 ;
        RECT  55.152 25.836 55.176 25.92 ;
    END
  END a_own_out[120]
  PIN a_own_out[121]
    DIRECTION OUTPUT ;
    USE SIGNAL ;
    PORT
      LAYER M3 ;
        RECT  55.476 25.882 55.494 25.92 ;
    END
  END a_own_out[121]
  PIN a_own_out[122]
    DIRECTION OUTPUT ;
    USE SIGNAL ;
    PORT
      LAYER M5 ;
        RECT  55.92 25.836 55.944 25.92 ;
    END
  END a_own_out[122]
  PIN a_own_out[123]
    DIRECTION OUTPUT ;
    USE SIGNAL ;
    PORT
      LAYER M3 ;
        RECT  56.34 25.882 56.358 25.92 ;
    END
  END a_own_out[123]
  PIN a_own_out[124]
    DIRECTION OUTPUT ;
    USE SIGNAL ;
    PORT
      LAYER M5 ;
        RECT  56.784 25.836 56.808 25.92 ;
    END
  END a_own_out[124]
  PIN a_own_out[125]
    DIRECTION OUTPUT ;
    USE SIGNAL ;
    PORT
      LAYER M3 ;
        RECT  57.204 25.882 57.222 25.92 ;
    END
  END a_own_out[125]
  PIN a_own_out[126]
    DIRECTION OUTPUT ;
    USE SIGNAL ;
    PORT
      LAYER M5 ;
        RECT  57.552 25.836 57.576 25.92 ;
    END
  END a_own_out[126]
  PIN a_own_out[127]
    DIRECTION OUTPUT ;
    USE SIGNAL ;
    PORT
      LAYER M3 ;
        RECT  57.96 25.882 57.978 25.92 ;
    END
  END a_own_out[127]
  PIN a_own_out[128]
    DIRECTION OUTPUT ;
    USE SIGNAL ;
    PORT
      LAYER M5 ;
        RECT  58.416 25.836 58.44 25.92 ;
    END
  END a_own_out[128]
  PIN a_own_out[129]
    DIRECTION OUTPUT ;
    USE SIGNAL ;
    PORT
      LAYER M3 ;
        RECT  58.824 25.882 58.842 25.92 ;
    END
  END a_own_out[129]
  PIN a_own_out[12]
    DIRECTION OUTPUT ;
    USE SIGNAL ;
    PORT
      LAYER M5 ;
        RECT  15.504 25.836 15.528 25.92 ;
    END
  END a_own_out[12]
  PIN a_own_out[130]
    DIRECTION OUTPUT ;
    USE SIGNAL ;
    PORT
      LAYER M5 ;
        RECT  59.184 25.836 59.208 25.92 ;
    END
  END a_own_out[130]
  PIN a_own_out[131]
    DIRECTION OUTPUT ;
    USE SIGNAL ;
    PORT
      LAYER M3 ;
        RECT  59.616 25.882 59.634 25.92 ;
    END
  END a_own_out[131]
  PIN a_own_out[132]
    DIRECTION OUTPUT ;
    USE SIGNAL ;
    PORT
      LAYER M5 ;
        RECT  60.048 25.836 60.072 25.92 ;
    END
  END a_own_out[132]
  PIN a_own_out[133]
    DIRECTION OUTPUT ;
    USE SIGNAL ;
    PORT
      LAYER M3 ;
        RECT  60.264 25.882 60.282 25.92 ;
    END
  END a_own_out[133]
  PIN a_own_out[134]
    DIRECTION OUTPUT ;
    USE SIGNAL ;
    PORT
      LAYER M5 ;
        RECT  60.432 25.836 60.456 25.92 ;
    END
  END a_own_out[134]
  PIN a_own_out[135]
    DIRECTION OUTPUT ;
    USE SIGNAL ;
    PORT
      LAYER M3 ;
        RECT  60.66 25.882 60.678 25.92 ;
    END
  END a_own_out[135]
  PIN a_own_out[136]
    DIRECTION OUTPUT ;
    USE SIGNAL ;
    PORT
      LAYER M5 ;
        RECT  60.816 25.836 60.84 25.92 ;
    END
  END a_own_out[136]
  PIN a_own_out[137]
    DIRECTION OUTPUT ;
    USE SIGNAL ;
    PORT
      LAYER M3 ;
        RECT  61.056 25.882 61.074 25.92 ;
    END
  END a_own_out[137]
  PIN a_own_out[138]
    DIRECTION OUTPUT ;
    USE SIGNAL ;
    PORT
      LAYER M5 ;
        RECT  61.296 25.836 61.32 25.92 ;
    END
  END a_own_out[138]
  PIN a_own_out[139]
    DIRECTION OUTPUT ;
    USE SIGNAL ;
    PORT
      LAYER M3 ;
        RECT  61.416 25.882 61.434 25.92 ;
    END
  END a_own_out[139]
  PIN a_own_out[13]
    DIRECTION OUTPUT ;
    USE SIGNAL ;
    PORT
      LAYER M3 ;
        RECT  15.624 25.882 15.642 25.92 ;
    END
  END a_own_out[13]
  PIN a_own_out[140]
    DIRECTION OUTPUT ;
    USE SIGNAL ;
    PORT
      LAYER M5 ;
        RECT  61.68 25.836 61.704 25.92 ;
    END
  END a_own_out[140]
  PIN a_own_out[141]
    DIRECTION OUTPUT ;
    USE SIGNAL ;
    PORT
      LAYER M3 ;
        RECT  61.92 25.882 61.938 25.92 ;
    END
  END a_own_out[141]
  PIN a_own_out[142]
    DIRECTION OUTPUT ;
    USE SIGNAL ;
    PORT
      LAYER M5 ;
        RECT  62.064 25.836 62.088 25.92 ;
    END
  END a_own_out[142]
  PIN a_own_out[143]
    DIRECTION OUTPUT ;
    USE SIGNAL ;
    PORT
      LAYER M3 ;
        RECT  62.28 25.882 62.298 25.92 ;
    END
  END a_own_out[143]
  PIN a_own_out[144]
    DIRECTION OUTPUT ;
    USE SIGNAL ;
    PORT
      LAYER M5 ;
        RECT  62.448 25.836 62.472 25.92 ;
    END
  END a_own_out[144]
  PIN a_own_out[145]
    DIRECTION OUTPUT ;
    USE SIGNAL ;
    PORT
      LAYER M3 ;
        RECT  62.676 25.882 62.694 25.92 ;
    END
  END a_own_out[145]
  PIN a_own_out[146]
    DIRECTION OUTPUT ;
    USE SIGNAL ;
    PORT
      LAYER M5 ;
        RECT  62.928 25.836 62.952 25.92 ;
    END
  END a_own_out[146]
  PIN a_own_out[147]
    DIRECTION OUTPUT ;
    USE SIGNAL ;
    PORT
      LAYER M3 ;
        RECT  63.072 25.882 63.09 25.92 ;
    END
  END a_own_out[147]
  PIN a_own_out[148]
    DIRECTION OUTPUT ;
    USE SIGNAL ;
    PORT
      LAYER M5 ;
        RECT  63.312 25.836 63.336 25.92 ;
    END
  END a_own_out[148]
  PIN a_own_out[149]
    DIRECTION OUTPUT ;
    USE SIGNAL ;
    PORT
      LAYER M3 ;
        RECT  63.54 25.882 63.558 25.92 ;
    END
  END a_own_out[149]
  PIN a_own_out[14]
    DIRECTION OUTPUT ;
    USE SIGNAL ;
    PORT
      LAYER M5 ;
        RECT  15.888 25.836 15.912 25.92 ;
    END
  END a_own_out[14]
  PIN a_own_out[150]
    DIRECTION OUTPUT ;
    USE SIGNAL ;
    PORT
      LAYER M5 ;
        RECT  63.696 25.836 63.72 25.92 ;
    END
  END a_own_out[150]
  PIN a_own_out[151]
    DIRECTION OUTPUT ;
    USE SIGNAL ;
    PORT
      LAYER M3 ;
        RECT  63.936 25.882 63.954 25.92 ;
    END
  END a_own_out[151]
  PIN a_own_out[152]
    DIRECTION OUTPUT ;
    USE SIGNAL ;
    PORT
      LAYER M5 ;
        RECT  64.176 25.836 64.2 25.92 ;
    END
  END a_own_out[152]
  PIN a_own_out[153]
    DIRECTION OUTPUT ;
    USE SIGNAL ;
    PORT
      LAYER M3 ;
        RECT  64.296 25.882 64.314 25.92 ;
    END
  END a_own_out[153]
  PIN a_own_out[154]
    DIRECTION OUTPUT ;
    USE SIGNAL ;
    PORT
      LAYER M5 ;
        RECT  64.56 25.836 64.584 25.92 ;
    END
  END a_own_out[154]
  PIN a_own_out[155]
    DIRECTION OUTPUT ;
    USE SIGNAL ;
    PORT
      LAYER M3 ;
        RECT  64.692 25.882 64.71 25.92 ;
    END
  END a_own_out[155]
  PIN a_own_out[156]
    DIRECTION OUTPUT ;
    USE SIGNAL ;
    PORT
      LAYER M5 ;
        RECT  64.944 25.836 64.968 25.92 ;
    END
  END a_own_out[156]
  PIN a_own_out[157]
    DIRECTION OUTPUT ;
    USE SIGNAL ;
    PORT
      LAYER M3 ;
        RECT  65.16 25.882 65.178 25.92 ;
    END
  END a_own_out[157]
  PIN a_own_out[158]
    DIRECTION OUTPUT ;
    USE SIGNAL ;
    PORT
      LAYER M5 ;
        RECT  65.328 25.836 65.352 25.92 ;
    END
  END a_own_out[158]
  PIN a_own_out[159]
    DIRECTION OUTPUT ;
    USE SIGNAL ;
    PORT
      LAYER M3 ;
        RECT  65.556 25.882 65.574 25.92 ;
    END
  END a_own_out[159]
  PIN a_own_out[15]
    DIRECTION OUTPUT ;
    USE SIGNAL ;
    PORT
      LAYER M3 ;
        RECT  16.128 25.882 16.146 25.92 ;
    END
  END a_own_out[15]
  PIN a_own_out[160]
    DIRECTION OUTPUT ;
    USE SIGNAL ;
    PORT
      LAYER M5 ;
        RECT  65.808 25.836 65.832 25.92 ;
    END
  END a_own_out[160]
  PIN a_own_out[161]
    DIRECTION OUTPUT ;
    USE SIGNAL ;
    PORT
      LAYER M3 ;
        RECT  65.952 25.882 65.97 25.92 ;
    END
  END a_own_out[161]
  PIN a_own_out[162]
    DIRECTION OUTPUT ;
    USE SIGNAL ;
    PORT
      LAYER M5 ;
        RECT  66.192 25.836 66.216 25.92 ;
    END
  END a_own_out[162]
  PIN a_own_out[163]
    DIRECTION OUTPUT ;
    USE SIGNAL ;
    PORT
      LAYER M3 ;
        RECT  66.42 25.882 66.438 25.92 ;
    END
  END a_own_out[163]
  PIN a_own_out[164]
    DIRECTION OUTPUT ;
    USE SIGNAL ;
    PORT
      LAYER M5 ;
        RECT  66.576 25.836 66.6 25.92 ;
    END
  END a_own_out[164]
  PIN a_own_out[165]
    DIRECTION OUTPUT ;
    USE SIGNAL ;
    PORT
      LAYER M3 ;
        RECT  66.816 25.882 66.834 25.92 ;
    END
  END a_own_out[165]
  PIN a_own_out[166]
    DIRECTION OUTPUT ;
    USE SIGNAL ;
    PORT
      LAYER M5 ;
        RECT  66.96 25.836 66.984 25.92 ;
    END
  END a_own_out[166]
  PIN a_own_out[167]
    DIRECTION OUTPUT ;
    USE SIGNAL ;
    PORT
      LAYER M3 ;
        RECT  67.176 25.882 67.194 25.92 ;
    END
  END a_own_out[167]
  PIN a_own_out[168]
    DIRECTION OUTPUT ;
    USE SIGNAL ;
    PORT
      LAYER M5 ;
        RECT  67.44 25.836 67.464 25.92 ;
    END
  END a_own_out[168]
  PIN a_own_out[169]
    DIRECTION OUTPUT ;
    USE SIGNAL ;
    PORT
      LAYER M3 ;
        RECT  67.572 25.882 67.59 25.92 ;
    END
  END a_own_out[169]
  PIN a_own_out[16]
    DIRECTION OUTPUT ;
    USE SIGNAL ;
    PORT
      LAYER M5 ;
        RECT  16.272 25.836 16.296 25.92 ;
    END
  END a_own_out[16]
  PIN a_own_out[170]
    DIRECTION OUTPUT ;
    USE SIGNAL ;
    PORT
      LAYER M5 ;
        RECT  67.824 25.836 67.848 25.92 ;
    END
  END a_own_out[170]
  PIN a_own_out[171]
    DIRECTION OUTPUT ;
    USE SIGNAL ;
    PORT
      LAYER M3 ;
        RECT  68.04 25.882 68.058 25.92 ;
    END
  END a_own_out[171]
  PIN a_own_out[172]
    DIRECTION OUTPUT ;
    USE SIGNAL ;
    PORT
      LAYER M5 ;
        RECT  68.208 25.836 68.232 25.92 ;
    END
  END a_own_out[172]
  PIN a_own_out[173]
    DIRECTION OUTPUT ;
    USE SIGNAL ;
    PORT
      LAYER M3 ;
        RECT  68.436 25.882 68.454 25.92 ;
    END
  END a_own_out[173]
  PIN a_own_out[174]
    DIRECTION OUTPUT ;
    USE SIGNAL ;
    PORT
      LAYER M5 ;
        RECT  68.592 25.836 68.616 25.92 ;
    END
  END a_own_out[174]
  PIN a_own_out[175]
    DIRECTION OUTPUT ;
    USE SIGNAL ;
    PORT
      LAYER M3 ;
        RECT  68.832 25.882 68.85 25.92 ;
    END
  END a_own_out[175]
  PIN a_own_out[176]
    DIRECTION OUTPUT ;
    USE SIGNAL ;
    PORT
      LAYER M5 ;
        RECT  69.072 25.836 69.096 25.92 ;
    END
  END a_own_out[176]
  PIN a_own_out[177]
    DIRECTION OUTPUT ;
    USE SIGNAL ;
    PORT
      LAYER M3 ;
        RECT  69.192 25.882 69.21 25.92 ;
    END
  END a_own_out[177]
  PIN a_own_out[178]
    DIRECTION OUTPUT ;
    USE SIGNAL ;
    PORT
      LAYER M5 ;
        RECT  69.456 25.836 69.48 25.92 ;
    END
  END a_own_out[178]
  PIN a_own_out[179]
    DIRECTION OUTPUT ;
    USE SIGNAL ;
    PORT
      LAYER M3 ;
        RECT  69.696 25.882 69.714 25.92 ;
    END
  END a_own_out[179]
  PIN a_own_out[17]
    DIRECTION OUTPUT ;
    USE SIGNAL ;
    PORT
      LAYER M3 ;
        RECT  16.488 25.882 16.506 25.92 ;
    END
  END a_own_out[17]
  PIN a_own_out[180]
    DIRECTION OUTPUT ;
    USE SIGNAL ;
    PORT
      LAYER M5 ;
        RECT  69.84 25.836 69.864 25.92 ;
    END
  END a_own_out[180]
  PIN a_own_out[181]
    DIRECTION OUTPUT ;
    USE SIGNAL ;
    PORT
      LAYER M3 ;
        RECT  70.056 25.882 70.074 25.92 ;
    END
  END a_own_out[181]
  PIN a_own_out[182]
    DIRECTION OUTPUT ;
    USE SIGNAL ;
    PORT
      LAYER M5 ;
        RECT  70.32 25.836 70.344 25.92 ;
    END
  END a_own_out[182]
  PIN a_own_out[183]
    DIRECTION OUTPUT ;
    USE SIGNAL ;
    PORT
      LAYER M3 ;
        RECT  70.452 25.882 70.47 25.92 ;
    END
  END a_own_out[183]
  PIN a_own_out[184]
    DIRECTION OUTPUT ;
    USE SIGNAL ;
    PORT
      LAYER M5 ;
        RECT  70.704 25.836 70.728 25.92 ;
    END
  END a_own_out[184]
  PIN a_own_out[185]
    DIRECTION OUTPUT ;
    USE SIGNAL ;
    PORT
      LAYER M3 ;
        RECT  70.848 25.882 70.866 25.92 ;
    END
  END a_own_out[185]
  PIN a_own_out[186]
    DIRECTION OUTPUT ;
    USE SIGNAL ;
    PORT
      LAYER M5 ;
        RECT  71.088 25.836 71.112 25.92 ;
    END
  END a_own_out[186]
  PIN a_own_out[187]
    DIRECTION OUTPUT ;
    USE SIGNAL ;
    PORT
      LAYER M3 ;
        RECT  71.316 25.882 71.334 25.92 ;
    END
  END a_own_out[187]
  PIN a_own_out[188]
    DIRECTION OUTPUT ;
    USE SIGNAL ;
    PORT
      LAYER M5 ;
        RECT  71.472 25.836 71.496 25.92 ;
    END
  END a_own_out[188]
  PIN a_own_out[189]
    DIRECTION OUTPUT ;
    USE SIGNAL ;
    PORT
      LAYER M3 ;
        RECT  71.712 25.882 71.73 25.92 ;
    END
  END a_own_out[189]
  PIN a_own_out[18]
    DIRECTION OUTPUT ;
    USE SIGNAL ;
    PORT
      LAYER M5 ;
        RECT  16.656 25.836 16.68 25.92 ;
    END
  END a_own_out[18]
  PIN a_own_out[190]
    DIRECTION OUTPUT ;
    USE SIGNAL ;
    PORT
      LAYER M5 ;
        RECT  71.952 25.836 71.976 25.92 ;
    END
  END a_own_out[190]
  PIN a_own_out[191]
    DIRECTION OUTPUT ;
    USE SIGNAL ;
    PORT
      LAYER M3 ;
        RECT  72.072 25.882 72.09 25.92 ;
    END
  END a_own_out[191]
  PIN a_own_out[192]
    DIRECTION OUTPUT ;
    USE SIGNAL ;
    PORT
      LAYER M5 ;
        RECT  72.336 25.836 72.36 25.92 ;
    END
  END a_own_out[192]
  PIN a_own_out[193]
    DIRECTION OUTPUT ;
    USE SIGNAL ;
    PORT
      LAYER M3 ;
        RECT  72.468 25.882 72.486 25.92 ;
    END
  END a_own_out[193]
  PIN a_own_out[194]
    DIRECTION OUTPUT ;
    USE SIGNAL ;
    PORT
      LAYER M5 ;
        RECT  72.72 25.836 72.744 25.92 ;
    END
  END a_own_out[194]
  PIN a_own_out[195]
    DIRECTION OUTPUT ;
    USE SIGNAL ;
    PORT
      LAYER M3 ;
        RECT  72.936 25.882 72.954 25.92 ;
    END
  END a_own_out[195]
  PIN a_own_out[196]
    DIRECTION OUTPUT ;
    USE SIGNAL ;
    PORT
      LAYER M5 ;
        RECT  73.104 25.836 73.128 25.92 ;
    END
  END a_own_out[196]
  PIN a_own_out[197]
    DIRECTION OUTPUT ;
    USE SIGNAL ;
    PORT
      LAYER M3 ;
        RECT  73.332 25.882 73.35 25.92 ;
    END
  END a_own_out[197]
  PIN a_own_out[198]
    DIRECTION OUTPUT ;
    USE SIGNAL ;
    PORT
      LAYER M5 ;
        RECT  73.584 25.836 73.608 25.92 ;
    END
  END a_own_out[198]
  PIN a_own_out[199]
    DIRECTION OUTPUT ;
    USE SIGNAL ;
    PORT
      LAYER M3 ;
        RECT  73.728 25.882 73.746 25.92 ;
    END
  END a_own_out[199]
  PIN a_own_out[19]
    DIRECTION OUTPUT ;
    USE SIGNAL ;
    PORT
      LAYER M3 ;
        RECT  16.884 25.882 16.902 25.92 ;
    END
  END a_own_out[19]
  PIN a_own_out[1]
    DIRECTION OUTPUT ;
    USE SIGNAL ;
    PORT
      LAYER M3 ;
        RECT  13.248 25.882 13.266 25.92 ;
    END
  END a_own_out[1]
  PIN a_own_out[200]
    DIRECTION OUTPUT ;
    USE SIGNAL ;
    PORT
      LAYER M5 ;
        RECT  73.968 25.836 73.992 25.92 ;
    END
  END a_own_out[200]
  PIN a_own_out[201]
    DIRECTION OUTPUT ;
    USE SIGNAL ;
    PORT
      LAYER M3 ;
        RECT  74.196 25.882 74.214 25.92 ;
    END
  END a_own_out[201]
  PIN a_own_out[202]
    DIRECTION OUTPUT ;
    USE SIGNAL ;
    PORT
      LAYER M5 ;
        RECT  74.352 25.836 74.376 25.92 ;
    END
  END a_own_out[202]
  PIN a_own_out[203]
    DIRECTION OUTPUT ;
    USE SIGNAL ;
    PORT
      LAYER M3 ;
        RECT  74.592 25.882 74.61 25.92 ;
    END
  END a_own_out[203]
  PIN a_own_out[204]
    DIRECTION OUTPUT ;
    USE SIGNAL ;
    PORT
      LAYER M5 ;
        RECT  74.736 25.836 74.76 25.92 ;
    END
  END a_own_out[204]
  PIN a_own_out[205]
    DIRECTION OUTPUT ;
    USE SIGNAL ;
    PORT
      LAYER M3 ;
        RECT  74.952 25.882 74.97 25.92 ;
    END
  END a_own_out[205]
  PIN a_own_out[206]
    DIRECTION OUTPUT ;
    USE SIGNAL ;
    PORT
      LAYER M5 ;
        RECT  75.216 25.836 75.24 25.92 ;
    END
  END a_own_out[206]
  PIN a_own_out[207]
    DIRECTION OUTPUT ;
    USE SIGNAL ;
    PORT
      LAYER M3 ;
        RECT  75.348 25.882 75.366 25.92 ;
    END
  END a_own_out[207]
  PIN a_own_out[208]
    DIRECTION OUTPUT ;
    USE SIGNAL ;
    PORT
      LAYER M5 ;
        RECT  75.6 25.836 75.624 25.92 ;
    END
  END a_own_out[208]
  PIN a_own_out[209]
    DIRECTION OUTPUT ;
    USE SIGNAL ;
    PORT
      LAYER M3 ;
        RECT  75.816 25.882 75.834 25.92 ;
    END
  END a_own_out[209]
  PIN a_own_out[20]
    DIRECTION OUTPUT ;
    USE SIGNAL ;
    PORT
      LAYER M5 ;
        RECT  17.136 25.836 17.16 25.92 ;
    END
  END a_own_out[20]
  PIN a_own_out[210]
    DIRECTION OUTPUT ;
    USE SIGNAL ;
    PORT
      LAYER M5 ;
        RECT  75.984 25.836 76.008 25.92 ;
    END
  END a_own_out[210]
  PIN a_own_out[211]
    DIRECTION OUTPUT ;
    USE SIGNAL ;
    PORT
      LAYER M3 ;
        RECT  76.212 25.882 76.23 25.92 ;
    END
  END a_own_out[211]
  PIN a_own_out[212]
    DIRECTION OUTPUT ;
    USE SIGNAL ;
    PORT
      LAYER M5 ;
        RECT  76.464 25.836 76.488 25.92 ;
    END
  END a_own_out[212]
  PIN a_own_out[213]
    DIRECTION OUTPUT ;
    USE SIGNAL ;
    PORT
      LAYER M3 ;
        RECT  76.608 25.882 76.626 25.92 ;
    END
  END a_own_out[213]
  PIN a_own_out[214]
    DIRECTION OUTPUT ;
    USE SIGNAL ;
    PORT
      LAYER M5 ;
        RECT  76.848 25.836 76.872 25.92 ;
    END
  END a_own_out[214]
  PIN a_own_out[215]
    DIRECTION OUTPUT ;
    USE SIGNAL ;
    PORT
      LAYER M3 ;
        RECT  76.968 25.882 76.986 25.92 ;
    END
  END a_own_out[215]
  PIN a_own_out[216]
    DIRECTION OUTPUT ;
    USE SIGNAL ;
    PORT
      LAYER M5 ;
        RECT  77.232 25.836 77.256 25.92 ;
    END
  END a_own_out[216]
  PIN a_own_out[217]
    DIRECTION OUTPUT ;
    USE SIGNAL ;
    PORT
      LAYER M3 ;
        RECT  77.472 25.882 77.49 25.92 ;
    END
  END a_own_out[217]
  PIN a_own_out[218]
    DIRECTION OUTPUT ;
    USE SIGNAL ;
    PORT
      LAYER M5 ;
        RECT  77.616 25.836 77.64 25.92 ;
    END
  END a_own_out[218]
  PIN a_own_out[219]
    DIRECTION OUTPUT ;
    USE SIGNAL ;
    PORT
      LAYER M3 ;
        RECT  77.832 25.882 77.85 25.92 ;
    END
  END a_own_out[219]
  PIN a_own_out[21]
    DIRECTION OUTPUT ;
    USE SIGNAL ;
    PORT
      LAYER M3 ;
        RECT  17.28 25.882 17.298 25.92 ;
    END
  END a_own_out[21]
  PIN a_own_out[220]
    DIRECTION OUTPUT ;
    USE SIGNAL ;
    PORT
      LAYER M5 ;
        RECT  78.096 25.836 78.12 25.92 ;
    END
  END a_own_out[220]
  PIN a_own_out[221]
    DIRECTION OUTPUT ;
    USE SIGNAL ;
    PORT
      LAYER M3 ;
        RECT  78.228 25.882 78.246 25.92 ;
    END
  END a_own_out[221]
  PIN a_own_out[222]
    DIRECTION OUTPUT ;
    USE SIGNAL ;
    PORT
      LAYER M5 ;
        RECT  78.48 25.836 78.504 25.92 ;
    END
  END a_own_out[222]
  PIN a_own_out[223]
    DIRECTION OUTPUT ;
    USE SIGNAL ;
    PORT
      LAYER M3 ;
        RECT  78.624 25.882 78.642 25.92 ;
    END
  END a_own_out[223]
  PIN a_own_out[224]
    DIRECTION OUTPUT ;
    USE SIGNAL ;
    PORT
      LAYER M5 ;
        RECT  78.864 25.836 78.888 25.92 ;
    END
  END a_own_out[224]
  PIN a_own_out[225]
    DIRECTION OUTPUT ;
    USE SIGNAL ;
    PORT
      LAYER M3 ;
        RECT  79.092 25.882 79.11 25.92 ;
    END
  END a_own_out[225]
  PIN a_own_out[226]
    DIRECTION OUTPUT ;
    USE SIGNAL ;
    PORT
      LAYER M5 ;
        RECT  79.248 25.836 79.272 25.92 ;
    END
  END a_own_out[226]
  PIN a_own_out[227]
    DIRECTION OUTPUT ;
    USE SIGNAL ;
    PORT
      LAYER M3 ;
        RECT  79.488 25.882 79.506 25.92 ;
    END
  END a_own_out[227]
  PIN a_own_out[228]
    DIRECTION OUTPUT ;
    USE SIGNAL ;
    PORT
      LAYER M5 ;
        RECT  79.728 25.836 79.752 25.92 ;
    END
  END a_own_out[228]
  PIN a_own_out[229]
    DIRECTION OUTPUT ;
    USE SIGNAL ;
    PORT
      LAYER M3 ;
        RECT  79.848 25.882 79.866 25.92 ;
    END
  END a_own_out[229]
  PIN a_own_out[22]
    DIRECTION OUTPUT ;
    USE SIGNAL ;
    PORT
      LAYER M5 ;
        RECT  17.52 25.836 17.544 25.92 ;
    END
  END a_own_out[22]
  PIN a_own_out[230]
    DIRECTION OUTPUT ;
    USE SIGNAL ;
    PORT
      LAYER M5 ;
        RECT  80.112 25.836 80.136 25.92 ;
    END
  END a_own_out[230]
  PIN a_own_out[231]
    DIRECTION OUTPUT ;
    USE SIGNAL ;
    PORT
      LAYER M3 ;
        RECT  80.352 25.882 80.37 25.92 ;
    END
  END a_own_out[231]
  PIN a_own_out[232]
    DIRECTION OUTPUT ;
    USE SIGNAL ;
    PORT
      LAYER M5 ;
        RECT  80.496 25.836 80.52 25.92 ;
    END
  END a_own_out[232]
  PIN a_own_out[233]
    DIRECTION OUTPUT ;
    USE SIGNAL ;
    PORT
      LAYER M3 ;
        RECT  80.712 25.882 80.73 25.92 ;
    END
  END a_own_out[233]
  PIN a_own_out[234]
    DIRECTION OUTPUT ;
    USE SIGNAL ;
    PORT
      LAYER M5 ;
        RECT  80.88 25.836 80.904 25.92 ;
    END
  END a_own_out[234]
  PIN a_own_out[235]
    DIRECTION OUTPUT ;
    USE SIGNAL ;
    PORT
      LAYER M3 ;
        RECT  81.108 25.882 81.126 25.92 ;
    END
  END a_own_out[235]
  PIN a_own_out[236]
    DIRECTION OUTPUT ;
    USE SIGNAL ;
    PORT
      LAYER M5 ;
        RECT  81.36 25.836 81.384 25.92 ;
    END
  END a_own_out[236]
  PIN a_own_out[237]
    DIRECTION OUTPUT ;
    USE SIGNAL ;
    PORT
      LAYER M3 ;
        RECT  81.504 25.882 81.522 25.92 ;
    END
  END a_own_out[237]
  PIN a_own_out[238]
    DIRECTION OUTPUT ;
    USE SIGNAL ;
    PORT
      LAYER M5 ;
        RECT  81.744 25.836 81.768 25.92 ;
    END
  END a_own_out[238]
  PIN a_own_out[239]
    DIRECTION OUTPUT ;
    USE SIGNAL ;
    PORT
      LAYER M3 ;
        RECT  81.972 25.882 81.99 25.92 ;
    END
  END a_own_out[239]
  PIN a_own_out[23]
    DIRECTION OUTPUT ;
    USE SIGNAL ;
    PORT
      LAYER M3 ;
        RECT  17.748 25.882 17.766 25.92 ;
    END
  END a_own_out[23]
  PIN a_own_out[240]
    DIRECTION OUTPUT ;
    USE SIGNAL ;
    PORT
      LAYER M5 ;
        RECT  82.128 25.836 82.152 25.92 ;
    END
  END a_own_out[240]
  PIN a_own_out[241]
    DIRECTION OUTPUT ;
    USE SIGNAL ;
    PORT
      LAYER M3 ;
        RECT  82.368 25.882 82.386 25.92 ;
    END
  END a_own_out[241]
  PIN a_own_out[242]
    DIRECTION OUTPUT ;
    USE SIGNAL ;
    PORT
      LAYER M5 ;
        RECT  82.512 25.836 82.536 25.92 ;
    END
  END a_own_out[242]
  PIN a_own_out[243]
    DIRECTION OUTPUT ;
    USE SIGNAL ;
    PORT
      LAYER M3 ;
        RECT  82.728 25.882 82.746 25.92 ;
    END
  END a_own_out[243]
  PIN a_own_out[244]
    DIRECTION OUTPUT ;
    USE SIGNAL ;
    PORT
      LAYER M5 ;
        RECT  82.992 25.836 83.016 25.92 ;
    END
  END a_own_out[244]
  PIN a_own_out[245]
    DIRECTION OUTPUT ;
    USE SIGNAL ;
    PORT
      LAYER M3 ;
        RECT  83.124 25.882 83.142 25.92 ;
    END
  END a_own_out[245]
  PIN a_own_out[246]
    DIRECTION OUTPUT ;
    USE SIGNAL ;
    PORT
      LAYER M5 ;
        RECT  83.376 25.836 83.4 25.92 ;
    END
  END a_own_out[246]
  PIN a_own_out[247]
    DIRECTION OUTPUT ;
    USE SIGNAL ;
    PORT
      LAYER M3 ;
        RECT  83.592 25.882 83.61 25.92 ;
    END
  END a_own_out[247]
  PIN a_own_out[248]
    DIRECTION OUTPUT ;
    USE SIGNAL ;
    PORT
      LAYER M5 ;
        RECT  83.76 25.836 83.784 25.92 ;
    END
  END a_own_out[248]
  PIN a_own_out[249]
    DIRECTION OUTPUT ;
    USE SIGNAL ;
    PORT
      LAYER M3 ;
        RECT  83.988 25.882 84.006 25.92 ;
    END
  END a_own_out[249]
  PIN a_own_out[24]
    DIRECTION OUTPUT ;
    USE SIGNAL ;
    PORT
      LAYER M5 ;
        RECT  17.904 25.836 17.928 25.92 ;
    END
  END a_own_out[24]
  PIN a_own_out[250]
    DIRECTION OUTPUT ;
    USE SIGNAL ;
    PORT
      LAYER M5 ;
        RECT  84.24 25.836 84.264 25.92 ;
    END
  END a_own_out[250]
  PIN a_own_out[251]
    DIRECTION OUTPUT ;
    USE SIGNAL ;
    PORT
      LAYER M3 ;
        RECT  84.384 25.882 84.402 25.92 ;
    END
  END a_own_out[251]
  PIN a_own_out[252]
    DIRECTION OUTPUT ;
    USE SIGNAL ;
    PORT
      LAYER M5 ;
        RECT  84.624 25.836 84.648 25.92 ;
    END
  END a_own_out[252]
  PIN a_own_out[253]
    DIRECTION OUTPUT ;
    USE SIGNAL ;
    PORT
      LAYER M3 ;
        RECT  84.744 25.882 84.762 25.92 ;
    END
  END a_own_out[253]
  PIN a_own_out[254]
    DIRECTION OUTPUT ;
    USE SIGNAL ;
    PORT
      LAYER M5 ;
        RECT  85.008 25.836 85.032 25.92 ;
    END
  END a_own_out[254]
  PIN a_own_out[255]
    DIRECTION OUTPUT ;
    USE SIGNAL ;
    PORT
      LAYER M3 ;
        RECT  85.248 25.882 85.266 25.92 ;
    END
  END a_own_out[255]
  PIN a_own_out[25]
    DIRECTION OUTPUT ;
    USE SIGNAL ;
    PORT
      LAYER M3 ;
        RECT  18.144 25.882 18.162 25.92 ;
    END
  END a_own_out[25]
  PIN a_own_out[26]
    DIRECTION OUTPUT ;
    USE SIGNAL ;
    PORT
      LAYER M5 ;
        RECT  18.384 25.836 18.408 25.92 ;
    END
  END a_own_out[26]
  PIN a_own_out[27]
    DIRECTION OUTPUT ;
    USE SIGNAL ;
    PORT
      LAYER M3 ;
        RECT  18.504 25.882 18.522 25.92 ;
    END
  END a_own_out[27]
  PIN a_own_out[28]
    DIRECTION OUTPUT ;
    USE SIGNAL ;
    PORT
      LAYER M5 ;
        RECT  18.768 25.836 18.792 25.92 ;
    END
  END a_own_out[28]
  PIN a_own_out[29]
    DIRECTION OUTPUT ;
    USE SIGNAL ;
    PORT
      LAYER M3 ;
        RECT  18.9 25.882 18.918 25.92 ;
    END
  END a_own_out[29]
  PIN a_own_out[2]
    DIRECTION OUTPUT ;
    USE SIGNAL ;
    PORT
      LAYER M5 ;
        RECT  13.392 25.836 13.416 25.92 ;
    END
  END a_own_out[2]
  PIN a_own_out[30]
    DIRECTION OUTPUT ;
    USE SIGNAL ;
    PORT
      LAYER M5 ;
        RECT  19.152 25.836 19.176 25.92 ;
    END
  END a_own_out[30]
  PIN a_own_out[31]
    DIRECTION OUTPUT ;
    USE SIGNAL ;
    PORT
      LAYER M3 ;
        RECT  19.368 25.882 19.386 25.92 ;
    END
  END a_own_out[31]
  PIN a_own_out[32]
    DIRECTION OUTPUT ;
    USE SIGNAL ;
    PORT
      LAYER M5 ;
        RECT  19.536 25.836 19.56 25.92 ;
    END
  END a_own_out[32]
  PIN a_own_out[33]
    DIRECTION OUTPUT ;
    USE SIGNAL ;
    PORT
      LAYER M3 ;
        RECT  19.764 25.882 19.782 25.92 ;
    END
  END a_own_out[33]
  PIN a_own_out[34]
    DIRECTION OUTPUT ;
    USE SIGNAL ;
    PORT
      LAYER M5 ;
        RECT  20.016 25.836 20.04 25.92 ;
    END
  END a_own_out[34]
  PIN a_own_out[35]
    DIRECTION OUTPUT ;
    USE SIGNAL ;
    PORT
      LAYER M3 ;
        RECT  20.34 25.882 20.358 25.92 ;
    END
  END a_own_out[35]
  PIN a_own_out[36]
    DIRECTION OUTPUT ;
    USE SIGNAL ;
    PORT
      LAYER M5 ;
        RECT  20.688 25.836 20.712 25.92 ;
    END
  END a_own_out[36]
  PIN a_own_out[37]
    DIRECTION OUTPUT ;
    USE SIGNAL ;
    PORT
      LAYER M3 ;
        RECT  21.096 25.882 21.114 25.92 ;
    END
  END a_own_out[37]
  PIN a_own_out[38]
    DIRECTION OUTPUT ;
    USE SIGNAL ;
    PORT
      LAYER M5 ;
        RECT  21.552 25.836 21.576 25.92 ;
    END
  END a_own_out[38]
  PIN a_own_out[39]
    DIRECTION OUTPUT ;
    USE SIGNAL ;
    PORT
      LAYER M3 ;
        RECT  21.96 25.882 21.978 25.92 ;
    END
  END a_own_out[39]
  PIN a_own_out[3]
    DIRECTION OUTPUT ;
    USE SIGNAL ;
    PORT
      LAYER M3 ;
        RECT  13.608 25.882 13.626 25.92 ;
    END
  END a_own_out[3]
  PIN a_own_out[40]
    DIRECTION OUTPUT ;
    USE SIGNAL ;
    PORT
      LAYER M5 ;
        RECT  22.416 25.836 22.44 25.92 ;
    END
  END a_own_out[40]
  PIN a_own_out[41]
    DIRECTION OUTPUT ;
    USE SIGNAL ;
    PORT
      LAYER M3 ;
        RECT  22.752 25.882 22.77 25.92 ;
    END
  END a_own_out[41]
  PIN a_own_out[42]
    DIRECTION OUTPUT ;
    USE SIGNAL ;
    PORT
      LAYER M5 ;
        RECT  23.184 25.836 23.208 25.92 ;
    END
  END a_own_out[42]
  PIN a_own_out[43]
    DIRECTION OUTPUT ;
    USE SIGNAL ;
    PORT
      LAYER M3 ;
        RECT  23.616 25.882 23.634 25.92 ;
    END
  END a_own_out[43]
  PIN a_own_out[44]
    DIRECTION OUTPUT ;
    USE SIGNAL ;
    PORT
      LAYER M5 ;
        RECT  24.048 25.836 24.072 25.92 ;
    END
  END a_own_out[44]
  PIN a_own_out[45]
    DIRECTION OUTPUT ;
    USE SIGNAL ;
    PORT
      LAYER M3 ;
        RECT  24.372 25.882 24.39 25.92 ;
    END
  END a_own_out[45]
  PIN a_own_out[46]
    DIRECTION OUTPUT ;
    USE SIGNAL ;
    PORT
      LAYER M5 ;
        RECT  24.816 25.836 24.84 25.92 ;
    END
  END a_own_out[46]
  PIN a_own_out[47]
    DIRECTION OUTPUT ;
    USE SIGNAL ;
    PORT
      LAYER M3 ;
        RECT  25.236 25.882 25.254 25.92 ;
    END
  END a_own_out[47]
  PIN a_own_out[48]
    DIRECTION OUTPUT ;
    USE SIGNAL ;
    PORT
      LAYER M5 ;
        RECT  25.68 25.836 25.704 25.92 ;
    END
  END a_own_out[48]
  PIN a_own_out[49]
    DIRECTION OUTPUT ;
    USE SIGNAL ;
    PORT
      LAYER M3 ;
        RECT  25.992 25.882 26.01 25.92 ;
    END
  END a_own_out[49]
  PIN a_own_out[4]
    DIRECTION OUTPUT ;
    USE SIGNAL ;
    PORT
      LAYER M5 ;
        RECT  13.872 25.836 13.896 25.92 ;
    END
  END a_own_out[4]
  PIN a_own_out[50]
    DIRECTION OUTPUT ;
    USE SIGNAL ;
    PORT
      LAYER M5 ;
        RECT  26.448 25.836 26.472 25.92 ;
    END
  END a_own_out[50]
  PIN a_own_out[51]
    DIRECTION OUTPUT ;
    USE SIGNAL ;
    PORT
      LAYER M3 ;
        RECT  26.856 25.882 26.874 25.92 ;
    END
  END a_own_out[51]
  PIN a_own_out[52]
    DIRECTION OUTPUT ;
    USE SIGNAL ;
    PORT
      LAYER M5 ;
        RECT  27.312 25.836 27.336 25.92 ;
    END
  END a_own_out[52]
  PIN a_own_out[53]
    DIRECTION OUTPUT ;
    USE SIGNAL ;
    PORT
      LAYER M3 ;
        RECT  27.648 25.882 27.666 25.92 ;
    END
  END a_own_out[53]
  PIN a_own_out[54]
    DIRECTION OUTPUT ;
    USE SIGNAL ;
    PORT
      LAYER M5 ;
        RECT  28.08 25.836 28.104 25.92 ;
    END
  END a_own_out[54]
  PIN a_own_out[55]
    DIRECTION OUTPUT ;
    USE SIGNAL ;
    PORT
      LAYER M3 ;
        RECT  28.512 25.882 28.53 25.92 ;
    END
  END a_own_out[55]
  PIN a_own_out[56]
    DIRECTION OUTPUT ;
    USE SIGNAL ;
    PORT
      LAYER M5 ;
        RECT  28.944 25.836 28.968 25.92 ;
    END
  END a_own_out[56]
  PIN a_own_out[57]
    DIRECTION OUTPUT ;
    USE SIGNAL ;
    PORT
      LAYER M3 ;
        RECT  29.376 25.882 29.394 25.92 ;
    END
  END a_own_out[57]
  PIN a_own_out[58]
    DIRECTION OUTPUT ;
    USE SIGNAL ;
    PORT
      LAYER M5 ;
        RECT  29.712 25.836 29.736 25.92 ;
    END
  END a_own_out[58]
  PIN a_own_out[59]
    DIRECTION OUTPUT ;
    USE SIGNAL ;
    PORT
      LAYER M3 ;
        RECT  30.132 25.882 30.15 25.92 ;
    END
  END a_own_out[59]
  PIN a_own_out[5]
    DIRECTION OUTPUT ;
    USE SIGNAL ;
    PORT
      LAYER M3 ;
        RECT  14.004 25.882 14.022 25.92 ;
    END
  END a_own_out[5]
  PIN a_own_out[60]
    DIRECTION OUTPUT ;
    USE SIGNAL ;
    PORT
      LAYER M5 ;
        RECT  30.576 25.836 30.6 25.92 ;
    END
  END a_own_out[60]
  PIN a_own_out[61]
    DIRECTION OUTPUT ;
    USE SIGNAL ;
    PORT
      LAYER M3 ;
        RECT  30.996 25.882 31.014 25.92 ;
    END
  END a_own_out[61]
  PIN a_own_out[62]
    DIRECTION OUTPUT ;
    USE SIGNAL ;
    PORT
      LAYER M5 ;
        RECT  31.344 25.836 31.368 25.92 ;
    END
  END a_own_out[62]
  PIN a_own_out[63]
    DIRECTION OUTPUT ;
    USE SIGNAL ;
    PORT
      LAYER M3 ;
        RECT  31.752 25.882 31.77 25.92 ;
    END
  END a_own_out[63]
  PIN a_own_out[64]
    DIRECTION OUTPUT ;
    USE SIGNAL ;
    PORT
      LAYER M5 ;
        RECT  32.208 25.836 32.232 25.92 ;
    END
  END a_own_out[64]
  PIN a_own_out[65]
    DIRECTION OUTPUT ;
    USE SIGNAL ;
    PORT
      LAYER M3 ;
        RECT  32.616 25.882 32.634 25.92 ;
    END
  END a_own_out[65]
  PIN a_own_out[66]
    DIRECTION OUTPUT ;
    USE SIGNAL ;
    PORT
      LAYER M5 ;
        RECT  32.976 25.836 33 25.92 ;
    END
  END a_own_out[66]
  PIN a_own_out[67]
    DIRECTION OUTPUT ;
    USE SIGNAL ;
    PORT
      LAYER M3 ;
        RECT  33.408 25.882 33.426 25.92 ;
    END
  END a_own_out[67]
  PIN a_own_out[68]
    DIRECTION OUTPUT ;
    USE SIGNAL ;
    PORT
      LAYER M5 ;
        RECT  33.84 25.836 33.864 25.92 ;
    END
  END a_own_out[68]
  PIN a_own_out[69]
    DIRECTION OUTPUT ;
    USE SIGNAL ;
    PORT
      LAYER M3 ;
        RECT  34.272 25.882 34.29 25.92 ;
    END
  END a_own_out[69]
  PIN a_own_out[6]
    DIRECTION OUTPUT ;
    USE SIGNAL ;
    PORT
      LAYER M5 ;
        RECT  14.256 25.836 14.28 25.92 ;
    END
  END a_own_out[6]
  PIN a_own_out[70]
    DIRECTION OUTPUT ;
    USE SIGNAL ;
    PORT
      LAYER M5 ;
        RECT  34.608 25.836 34.632 25.92 ;
    END
  END a_own_out[70]
  PIN a_own_out[71]
    DIRECTION OUTPUT ;
    USE SIGNAL ;
    PORT
      LAYER M3 ;
        RECT  35.028 25.882 35.046 25.92 ;
    END
  END a_own_out[71]
  PIN a_own_out[72]
    DIRECTION OUTPUT ;
    USE SIGNAL ;
    PORT
      LAYER M5 ;
        RECT  35.472 25.836 35.496 25.92 ;
    END
  END a_own_out[72]
  PIN a_own_out[73]
    DIRECTION OUTPUT ;
    USE SIGNAL ;
    PORT
      LAYER M3 ;
        RECT  35.892 25.882 35.91 25.92 ;
    END
  END a_own_out[73]
  PIN a_own_out[74]
    DIRECTION OUTPUT ;
    USE SIGNAL ;
    PORT
      LAYER M5 ;
        RECT  36.336 25.836 36.36 25.92 ;
    END
  END a_own_out[74]
  PIN a_own_out[75]
    DIRECTION OUTPUT ;
    USE SIGNAL ;
    PORT
      LAYER M3 ;
        RECT  36.648 25.882 36.666 25.92 ;
    END
  END a_own_out[75]
  PIN a_own_out[76]
    DIRECTION OUTPUT ;
    USE SIGNAL ;
    PORT
      LAYER M5 ;
        RECT  37.104 25.836 37.128 25.92 ;
    END
  END a_own_out[76]
  PIN a_own_out[77]
    DIRECTION OUTPUT ;
    USE SIGNAL ;
    PORT
      LAYER M3 ;
        RECT  37.512 25.882 37.53 25.92 ;
    END
  END a_own_out[77]
  PIN a_own_out[78]
    DIRECTION OUTPUT ;
    USE SIGNAL ;
    PORT
      LAYER M5 ;
        RECT  37.968 25.836 37.992 25.92 ;
    END
  END a_own_out[78]
  PIN a_own_out[79]
    DIRECTION OUTPUT ;
    USE SIGNAL ;
    PORT
      LAYER M3 ;
        RECT  38.304 25.882 38.322 25.92 ;
    END
  END a_own_out[79]
  PIN a_own_out[7]
    DIRECTION OUTPUT ;
    USE SIGNAL ;
    PORT
      LAYER M3 ;
        RECT  14.4 25.882 14.418 25.92 ;
    END
  END a_own_out[7]
  PIN a_own_out[80]
    DIRECTION OUTPUT ;
    USE SIGNAL ;
    PORT
      LAYER M5 ;
        RECT  38.736 25.836 38.76 25.92 ;
    END
  END a_own_out[80]
  PIN a_own_out[81]
    DIRECTION OUTPUT ;
    USE SIGNAL ;
    PORT
      LAYER M3 ;
        RECT  39.168 25.882 39.186 25.92 ;
    END
  END a_own_out[81]
  PIN a_own_out[82]
    DIRECTION OUTPUT ;
    USE SIGNAL ;
    PORT
      LAYER M5 ;
        RECT  39.6 25.836 39.624 25.92 ;
    END
  END a_own_out[82]
  PIN a_own_out[83]
    DIRECTION OUTPUT ;
    USE SIGNAL ;
    PORT
      LAYER M3 ;
        RECT  39.924 25.882 39.942 25.92 ;
    END
  END a_own_out[83]
  PIN a_own_out[84]
    DIRECTION OUTPUT ;
    USE SIGNAL ;
    PORT
      LAYER M5 ;
        RECT  40.368 25.836 40.392 25.92 ;
    END
  END a_own_out[84]
  PIN a_own_out[85]
    DIRECTION OUTPUT ;
    USE SIGNAL ;
    PORT
      LAYER M3 ;
        RECT  40.788 25.882 40.806 25.92 ;
    END
  END a_own_out[85]
  PIN a_own_out[86]
    DIRECTION OUTPUT ;
    USE SIGNAL ;
    PORT
      LAYER M5 ;
        RECT  41.232 25.836 41.256 25.92 ;
    END
  END a_own_out[86]
  PIN a_own_out[87]
    DIRECTION OUTPUT ;
    USE SIGNAL ;
    PORT
      LAYER M3 ;
        RECT  41.544 25.882 41.562 25.92 ;
    END
  END a_own_out[87]
  PIN a_own_out[88]
    DIRECTION OUTPUT ;
    USE SIGNAL ;
    PORT
      LAYER M5 ;
        RECT  42 25.836 42.024 25.92 ;
    END
  END a_own_out[88]
  PIN a_own_out[89]
    DIRECTION OUTPUT ;
    USE SIGNAL ;
    PORT
      LAYER M3 ;
        RECT  42.408 25.882 42.426 25.92 ;
    END
  END a_own_out[89]
  PIN a_own_out[8]
    DIRECTION OUTPUT ;
    USE SIGNAL ;
    PORT
      LAYER M5 ;
        RECT  14.64 25.836 14.664 25.92 ;
    END
  END a_own_out[8]
  PIN a_own_out[90]
    DIRECTION OUTPUT ;
    USE SIGNAL ;
    PORT
      LAYER M5 ;
        RECT  42.864 25.836 42.888 25.92 ;
    END
  END a_own_out[90]
  PIN a_own_out[91]
    DIRECTION OUTPUT ;
    USE SIGNAL ;
    PORT
      LAYER M3 ;
        RECT  43.272 25.882 43.29 25.92 ;
    END
  END a_own_out[91]
  PIN a_own_out[92]
    DIRECTION OUTPUT ;
    USE SIGNAL ;
    PORT
      LAYER M5 ;
        RECT  43.632 25.836 43.656 25.92 ;
    END
  END a_own_out[92]
  PIN a_own_out[93]
    DIRECTION OUTPUT ;
    USE SIGNAL ;
    PORT
      LAYER M3 ;
        RECT  44.064 25.882 44.082 25.92 ;
    END
  END a_own_out[93]
  PIN a_own_out[94]
    DIRECTION OUTPUT ;
    USE SIGNAL ;
    PORT
      LAYER M5 ;
        RECT  44.496 25.836 44.52 25.92 ;
    END
  END a_own_out[94]
  PIN a_own_out[95]
    DIRECTION OUTPUT ;
    USE SIGNAL ;
    PORT
      LAYER M3 ;
        RECT  44.928 25.882 44.946 25.92 ;
    END
  END a_own_out[95]
  PIN a_own_out[96]
    DIRECTION OUTPUT ;
    USE SIGNAL ;
    PORT
      LAYER M5 ;
        RECT  45.264 25.836 45.288 25.92 ;
    END
  END a_own_out[96]
  PIN a_own_out[97]
    DIRECTION OUTPUT ;
    USE SIGNAL ;
    PORT
      LAYER M3 ;
        RECT  45.684 25.882 45.702 25.92 ;
    END
  END a_own_out[97]
  PIN a_own_out[98]
    DIRECTION OUTPUT ;
    USE SIGNAL ;
    PORT
      LAYER M5 ;
        RECT  46.128 25.836 46.152 25.92 ;
    END
  END a_own_out[98]
  PIN a_own_out[99]
    DIRECTION OUTPUT ;
    USE SIGNAL ;
    PORT
      LAYER M3 ;
        RECT  46.548 25.882 46.566 25.92 ;
    END
  END a_own_out[99]
  PIN a_own_out[9]
    DIRECTION OUTPUT ;
    USE SIGNAL ;
    PORT
      LAYER M3 ;
        RECT  14.868 25.882 14.886 25.92 ;
    END
  END a_own_out[9]
  PIN b_own[0]
    DIRECTION INPUT ;
    USE SIGNAL ;
    PORT
      LAYER M5 ;
        RECT  85.392 0 85.416 0.084 ;
    END
  END b_own[0]
  PIN b_own[100]
    DIRECTION INPUT ;
    USE SIGNAL ;
    PORT
      LAYER M5 ;
        RECT  105.936 0 105.96 0.084 ;
    END
  END b_own[100]
  PIN b_own[101]
    DIRECTION INPUT ;
    USE SIGNAL ;
    PORT
      LAYER M3 ;
        RECT  106.056 0 106.074 0.038 ;
    END
  END b_own[101]
  PIN b_own[102]
    DIRECTION INPUT ;
    USE SIGNAL ;
    PORT
      LAYER M5 ;
        RECT  106.32 0 106.344 0.084 ;
    END
  END b_own[102]
  PIN b_own[103]
    DIRECTION INPUT ;
    USE SIGNAL ;
    PORT
      LAYER M3 ;
        RECT  106.56 0 106.578 0.038 ;
    END
  END b_own[103]
  PIN b_own[104]
    DIRECTION INPUT ;
    USE SIGNAL ;
    PORT
      LAYER M5 ;
        RECT  106.704 0 106.728 0.084 ;
    END
  END b_own[104]
  PIN b_own[105]
    DIRECTION INPUT ;
    USE SIGNAL ;
    PORT
      LAYER M3 ;
        RECT  106.92 0 106.938 0.038 ;
    END
  END b_own[105]
  PIN b_own[106]
    DIRECTION INPUT ;
    USE SIGNAL ;
    PORT
      LAYER M5 ;
        RECT  107.088 0 107.112 0.084 ;
    END
  END b_own[106]
  PIN b_own[107]
    DIRECTION INPUT ;
    USE SIGNAL ;
    PORT
      LAYER M3 ;
        RECT  107.316 0 107.334 0.038 ;
    END
  END b_own[107]
  PIN b_own[108]
    DIRECTION INPUT ;
    USE SIGNAL ;
    PORT
      LAYER M5 ;
        RECT  107.568 0 107.592 0.084 ;
    END
  END b_own[108]
  PIN b_own[109]
    DIRECTION INPUT ;
    USE SIGNAL ;
    PORT
      LAYER M3 ;
        RECT  107.712 0 107.73 0.038 ;
    END
  END b_own[109]
  PIN b_own[10]
    DIRECTION INPUT ;
    USE SIGNAL ;
    PORT
      LAYER M5 ;
        RECT  87.504 0 87.528 0.084 ;
    END
  END b_own[10]
  PIN b_own[110]
    DIRECTION INPUT ;
    USE SIGNAL ;
    PORT
      LAYER M5 ;
        RECT  107.952 0 107.976 0.084 ;
    END
  END b_own[110]
  PIN b_own[111]
    DIRECTION INPUT ;
    USE SIGNAL ;
    PORT
      LAYER M3 ;
        RECT  108.18 0 108.198 0.038 ;
    END
  END b_own[111]
  PIN b_own[112]
    DIRECTION INPUT ;
    USE SIGNAL ;
    PORT
      LAYER M5 ;
        RECT  108.336 0 108.36 0.084 ;
    END
  END b_own[112]
  PIN b_own[113]
    DIRECTION INPUT ;
    USE SIGNAL ;
    PORT
      LAYER M3 ;
        RECT  108.576 0 108.594 0.038 ;
    END
  END b_own[113]
  PIN b_own[114]
    DIRECTION INPUT ;
    USE SIGNAL ;
    PORT
      LAYER M5 ;
        RECT  108.72 0 108.744 0.084 ;
    END
  END b_own[114]
  PIN b_own[115]
    DIRECTION INPUT ;
    USE SIGNAL ;
    PORT
      LAYER M3 ;
        RECT  108.936 0 108.954 0.038 ;
    END
  END b_own[115]
  PIN b_own[116]
    DIRECTION INPUT ;
    USE SIGNAL ;
    PORT
      LAYER M5 ;
        RECT  109.2 0 109.224 0.084 ;
    END
  END b_own[116]
  PIN b_own[117]
    DIRECTION INPUT ;
    USE SIGNAL ;
    PORT
      LAYER M3 ;
        RECT  109.332 0 109.35 0.038 ;
    END
  END b_own[117]
  PIN b_own[118]
    DIRECTION INPUT ;
    USE SIGNAL ;
    PORT
      LAYER M5 ;
        RECT  109.584 0 109.608 0.084 ;
    END
  END b_own[118]
  PIN b_own[119]
    DIRECTION INPUT ;
    USE SIGNAL ;
    PORT
      LAYER M3 ;
        RECT  109.8 0 109.818 0.038 ;
    END
  END b_own[119]
  PIN b_own[11]
    DIRECTION INPUT ;
    USE SIGNAL ;
    PORT
      LAYER M3 ;
        RECT  87.624 0 87.642 0.038 ;
    END
  END b_own[11]
  PIN b_own[120]
    DIRECTION INPUT ;
    USE SIGNAL ;
    PORT
      LAYER M5 ;
        RECT  109.968 0 109.992 0.084 ;
    END
  END b_own[120]
  PIN b_own[121]
    DIRECTION INPUT ;
    USE SIGNAL ;
    PORT
      LAYER M3 ;
        RECT  110.196 0 110.214 0.038 ;
    END
  END b_own[121]
  PIN b_own[122]
    DIRECTION INPUT ;
    USE SIGNAL ;
    PORT
      LAYER M5 ;
        RECT  110.448 0 110.472 0.084 ;
    END
  END b_own[122]
  PIN b_own[123]
    DIRECTION INPUT ;
    USE SIGNAL ;
    PORT
      LAYER M3 ;
        RECT  110.592 0 110.61 0.038 ;
    END
  END b_own[123]
  PIN b_own[124]
    DIRECTION INPUT ;
    USE SIGNAL ;
    PORT
      LAYER M5 ;
        RECT  110.832 0 110.856 0.084 ;
    END
  END b_own[124]
  PIN b_own[125]
    DIRECTION INPUT ;
    USE SIGNAL ;
    PORT
      LAYER M3 ;
        RECT  110.952 0 110.97 0.038 ;
    END
  END b_own[125]
  PIN b_own[126]
    DIRECTION INPUT ;
    USE SIGNAL ;
    PORT
      LAYER M5 ;
        RECT  111.216 0 111.24 0.084 ;
    END
  END b_own[126]
  PIN b_own[127]
    DIRECTION INPUT ;
    USE SIGNAL ;
    PORT
      LAYER M3 ;
        RECT  111.456 0 111.474 0.038 ;
    END
  END b_own[127]
  PIN b_own[128]
    DIRECTION INPUT ;
    USE SIGNAL ;
    PORT
      LAYER M5 ;
        RECT  111.6 0 111.624 0.084 ;
    END
  END b_own[128]
  PIN b_own[129]
    DIRECTION INPUT ;
    USE SIGNAL ;
    PORT
      LAYER M3 ;
        RECT  111.816 0 111.834 0.038 ;
    END
  END b_own[129]
  PIN b_own[12]
    DIRECTION INPUT ;
    USE SIGNAL ;
    PORT
      LAYER M5 ;
        RECT  87.888 0 87.912 0.084 ;
    END
  END b_own[12]
  PIN b_own[130]
    DIRECTION INPUT ;
    USE SIGNAL ;
    PORT
      LAYER M5 ;
        RECT  112.08 0 112.104 0.084 ;
    END
  END b_own[130]
  PIN b_own[131]
    DIRECTION INPUT ;
    USE SIGNAL ;
    PORT
      LAYER M3 ;
        RECT  112.212 0 112.23 0.038 ;
    END
  END b_own[131]
  PIN b_own[132]
    DIRECTION INPUT ;
    USE SIGNAL ;
    PORT
      LAYER M5 ;
        RECT  112.464 0 112.488 0.084 ;
    END
  END b_own[132]
  PIN b_own[133]
    DIRECTION INPUT ;
    USE SIGNAL ;
    PORT
      LAYER M3 ;
        RECT  112.608 0 112.626 0.038 ;
    END
  END b_own[133]
  PIN b_own[134]
    DIRECTION INPUT ;
    USE SIGNAL ;
    PORT
      LAYER M5 ;
        RECT  112.848 0 112.872 0.084 ;
    END
  END b_own[134]
  PIN b_own[135]
    DIRECTION INPUT ;
    USE SIGNAL ;
    PORT
      LAYER M3 ;
        RECT  113.076 0 113.094 0.038 ;
    END
  END b_own[135]
  PIN b_own[136]
    DIRECTION INPUT ;
    USE SIGNAL ;
    PORT
      LAYER M5 ;
        RECT  113.232 0 113.256 0.084 ;
    END
  END b_own[136]
  PIN b_own[137]
    DIRECTION INPUT ;
    USE SIGNAL ;
    PORT
      LAYER M3 ;
        RECT  113.472 0 113.49 0.038 ;
    END
  END b_own[137]
  PIN b_own[138]
    DIRECTION INPUT ;
    USE SIGNAL ;
    PORT
      LAYER M5 ;
        RECT  113.712 0 113.736 0.084 ;
    END
  END b_own[138]
  PIN b_own[139]
    DIRECTION INPUT ;
    USE SIGNAL ;
    PORT
      LAYER M3 ;
        RECT  113.832 0 113.85 0.038 ;
    END
  END b_own[139]
  PIN b_own[13]
    DIRECTION INPUT ;
    USE SIGNAL ;
    PORT
      LAYER M3 ;
        RECT  88.128 0 88.146 0.038 ;
    END
  END b_own[13]
  PIN b_own[140]
    DIRECTION INPUT ;
    USE SIGNAL ;
    PORT
      LAYER M5 ;
        RECT  114.096 0 114.12 0.084 ;
    END
  END b_own[140]
  PIN b_own[141]
    DIRECTION INPUT ;
    USE SIGNAL ;
    PORT
      LAYER M3 ;
        RECT  114.336 0 114.354 0.038 ;
    END
  END b_own[141]
  PIN b_own[142]
    DIRECTION INPUT ;
    USE SIGNAL ;
    PORT
      LAYER M5 ;
        RECT  114.48 0 114.504 0.084 ;
    END
  END b_own[142]
  PIN b_own[143]
    DIRECTION INPUT ;
    USE SIGNAL ;
    PORT
      LAYER M3 ;
        RECT  114.696 0 114.714 0.038 ;
    END
  END b_own[143]
  PIN b_own[144]
    DIRECTION INPUT ;
    USE SIGNAL ;
    PORT
      LAYER M5 ;
        RECT  114.864 0 114.888 0.084 ;
    END
  END b_own[144]
  PIN b_own[145]
    DIRECTION INPUT ;
    USE SIGNAL ;
    PORT
      LAYER M3 ;
        RECT  115.092 0 115.11 0.038 ;
    END
  END b_own[145]
  PIN b_own[146]
    DIRECTION INPUT ;
    USE SIGNAL ;
    PORT
      LAYER M5 ;
        RECT  115.344 0 115.368 0.084 ;
    END
  END b_own[146]
  PIN b_own[147]
    DIRECTION INPUT ;
    USE SIGNAL ;
    PORT
      LAYER M3 ;
        RECT  115.488 0 115.506 0.038 ;
    END
  END b_own[147]
  PIN b_own[148]
    DIRECTION INPUT ;
    USE SIGNAL ;
    PORT
      LAYER M5 ;
        RECT  115.728 0 115.752 0.084 ;
    END
  END b_own[148]
  PIN b_own[149]
    DIRECTION INPUT ;
    USE SIGNAL ;
    PORT
      LAYER M3 ;
        RECT  115.956 0 115.974 0.038 ;
    END
  END b_own[149]
  PIN b_own[14]
    DIRECTION INPUT ;
    USE SIGNAL ;
    PORT
      LAYER M5 ;
        RECT  88.272 0 88.296 0.084 ;
    END
  END b_own[14]
  PIN b_own[150]
    DIRECTION INPUT ;
    USE SIGNAL ;
    PORT
      LAYER M5 ;
        RECT  116.112 0 116.136 0.084 ;
    END
  END b_own[150]
  PIN b_own[151]
    DIRECTION INPUT ;
    USE SIGNAL ;
    PORT
      LAYER M3 ;
        RECT  116.352 0 116.37 0.038 ;
    END
  END b_own[151]
  PIN b_own[152]
    DIRECTION INPUT ;
    USE SIGNAL ;
    PORT
      LAYER M5 ;
        RECT  116.592 0 116.616 0.084 ;
    END
  END b_own[152]
  PIN b_own[153]
    DIRECTION INPUT ;
    USE SIGNAL ;
    PORT
      LAYER M3 ;
        RECT  116.712 0 116.73 0.038 ;
    END
  END b_own[153]
  PIN b_own[154]
    DIRECTION INPUT ;
    USE SIGNAL ;
    PORT
      LAYER M5 ;
        RECT  116.976 0 117 0.084 ;
    END
  END b_own[154]
  PIN b_own[155]
    DIRECTION INPUT ;
    USE SIGNAL ;
    PORT
      LAYER M3 ;
        RECT  117.108 0 117.126 0.038 ;
    END
  END b_own[155]
  PIN b_own[156]
    DIRECTION INPUT ;
    USE SIGNAL ;
    PORT
      LAYER M5 ;
        RECT  117.36 0 117.384 0.084 ;
    END
  END b_own[156]
  PIN b_own[157]
    DIRECTION INPUT ;
    USE SIGNAL ;
    PORT
      LAYER M3 ;
        RECT  117.576 0 117.594 0.038 ;
    END
  END b_own[157]
  PIN b_own[158]
    DIRECTION INPUT ;
    USE SIGNAL ;
    PORT
      LAYER M5 ;
        RECT  117.744 0 117.768 0.084 ;
    END
  END b_own[158]
  PIN b_own[159]
    DIRECTION INPUT ;
    USE SIGNAL ;
    PORT
      LAYER M3 ;
        RECT  117.972 0 117.99 0.038 ;
    END
  END b_own[159]
  PIN b_own[15]
    DIRECTION INPUT ;
    USE SIGNAL ;
    PORT
      LAYER M3 ;
        RECT  88.488 0 88.506 0.038 ;
    END
  END b_own[15]
  PIN b_own[160]
    DIRECTION INPUT ;
    USE SIGNAL ;
    PORT
      LAYER M5 ;
        RECT  118.224 0 118.248 0.084 ;
    END
  END b_own[160]
  PIN b_own[161]
    DIRECTION INPUT ;
    USE SIGNAL ;
    PORT
      LAYER M3 ;
        RECT  118.368 0 118.386 0.038 ;
    END
  END b_own[161]
  PIN b_own[162]
    DIRECTION INPUT ;
    USE SIGNAL ;
    PORT
      LAYER M5 ;
        RECT  118.608 0 118.632 0.084 ;
    END
  END b_own[162]
  PIN b_own[163]
    DIRECTION INPUT ;
    USE SIGNAL ;
    PORT
      LAYER M3 ;
        RECT  118.728 0 118.746 0.038 ;
    END
  END b_own[163]
  PIN b_own[164]
    DIRECTION INPUT ;
    USE SIGNAL ;
    PORT
      LAYER M5 ;
        RECT  118.992 0 119.016 0.084 ;
    END
  END b_own[164]
  PIN b_own[165]
    DIRECTION INPUT ;
    USE SIGNAL ;
    PORT
      LAYER M3 ;
        RECT  119.232 0 119.25 0.038 ;
    END
  END b_own[165]
  PIN b_own[166]
    DIRECTION INPUT ;
    USE SIGNAL ;
    PORT
      LAYER M5 ;
        RECT  119.376 0 119.4 0.084 ;
    END
  END b_own[166]
  PIN b_own[167]
    DIRECTION INPUT ;
    USE SIGNAL ;
    PORT
      LAYER M3 ;
        RECT  119.592 0 119.61 0.038 ;
    END
  END b_own[167]
  PIN b_own[168]
    DIRECTION INPUT ;
    USE SIGNAL ;
    PORT
      LAYER M5 ;
        RECT  119.856 0 119.88 0.084 ;
    END
  END b_own[168]
  PIN b_own[169]
    DIRECTION INPUT ;
    USE SIGNAL ;
    PORT
      LAYER M3 ;
        RECT  119.988 0 120.006 0.038 ;
    END
  END b_own[169]
  PIN b_own[16]
    DIRECTION INPUT ;
    USE SIGNAL ;
    PORT
      LAYER M5 ;
        RECT  88.656 0 88.68 0.084 ;
    END
  END b_own[16]
  PIN b_own[170]
    DIRECTION INPUT ;
    USE SIGNAL ;
    PORT
      LAYER M5 ;
        RECT  120.24 0 120.264 0.084 ;
    END
  END b_own[170]
  PIN b_own[171]
    DIRECTION INPUT ;
    USE SIGNAL ;
    PORT
      LAYER M3 ;
        RECT  120.456 0 120.474 0.038 ;
    END
  END b_own[171]
  PIN b_own[172]
    DIRECTION INPUT ;
    USE SIGNAL ;
    PORT
      LAYER M5 ;
        RECT  120.624 0 120.648 0.084 ;
    END
  END b_own[172]
  PIN b_own[173]
    DIRECTION INPUT ;
    USE SIGNAL ;
    PORT
      LAYER M3 ;
        RECT  120.852 0 120.87 0.038 ;
    END
  END b_own[173]
  PIN b_own[174]
    DIRECTION INPUT ;
    USE SIGNAL ;
    PORT
      LAYER M5 ;
        RECT  121.008 0 121.032 0.084 ;
    END
  END b_own[174]
  PIN b_own[175]
    DIRECTION INPUT ;
    USE SIGNAL ;
    PORT
      LAYER M3 ;
        RECT  121.248 0 121.266 0.038 ;
    END
  END b_own[175]
  PIN b_own[176]
    DIRECTION INPUT ;
    USE SIGNAL ;
    PORT
      LAYER M5 ;
        RECT  121.488 0 121.512 0.084 ;
    END
  END b_own[176]
  PIN b_own[177]
    DIRECTION INPUT ;
    USE SIGNAL ;
    PORT
      LAYER M3 ;
        RECT  121.608 0 121.626 0.038 ;
    END
  END b_own[177]
  PIN b_own[178]
    DIRECTION INPUT ;
    USE SIGNAL ;
    PORT
      LAYER M5 ;
        RECT  121.872 0 121.896 0.084 ;
    END
  END b_own[178]
  PIN b_own[179]
    DIRECTION INPUT ;
    USE SIGNAL ;
    PORT
      LAYER M3 ;
        RECT  122.112 0 122.13 0.038 ;
    END
  END b_own[179]
  PIN b_own[17]
    DIRECTION INPUT ;
    USE SIGNAL ;
    PORT
      LAYER M3 ;
        RECT  88.884 0 88.902 0.038 ;
    END
  END b_own[17]
  PIN b_own[180]
    DIRECTION INPUT ;
    USE SIGNAL ;
    PORT
      LAYER M5 ;
        RECT  122.256 0 122.28 0.084 ;
    END
  END b_own[180]
  PIN b_own[181]
    DIRECTION INPUT ;
    USE SIGNAL ;
    PORT
      LAYER M3 ;
        RECT  122.472 0 122.49 0.038 ;
    END
  END b_own[181]
  PIN b_own[182]
    DIRECTION INPUT ;
    USE SIGNAL ;
    PORT
      LAYER M5 ;
        RECT  122.64 0 122.664 0.084 ;
    END
  END b_own[182]
  PIN b_own[183]
    DIRECTION INPUT ;
    USE SIGNAL ;
    PORT
      LAYER M3 ;
        RECT  122.868 0 122.886 0.038 ;
    END
  END b_own[183]
  PIN b_own[184]
    DIRECTION INPUT ;
    USE SIGNAL ;
    PORT
      LAYER M5 ;
        RECT  123.12 0 123.144 0.084 ;
    END
  END b_own[184]
  PIN b_own[185]
    DIRECTION INPUT ;
    USE SIGNAL ;
    PORT
      LAYER M3 ;
        RECT  123.264 0 123.282 0.038 ;
    END
  END b_own[185]
  PIN b_own[186]
    DIRECTION INPUT ;
    USE SIGNAL ;
    PORT
      LAYER M5 ;
        RECT  123.504 0 123.528 0.084 ;
    END
  END b_own[186]
  PIN b_own[187]
    DIRECTION INPUT ;
    USE SIGNAL ;
    PORT
      LAYER M3 ;
        RECT  123.732 0 123.75 0.038 ;
    END
  END b_own[187]
  PIN b_own[188]
    DIRECTION INPUT ;
    USE SIGNAL ;
    PORT
      LAYER M5 ;
        RECT  123.888 0 123.912 0.084 ;
    END
  END b_own[188]
  PIN b_own[189]
    DIRECTION INPUT ;
    USE SIGNAL ;
    PORT
      LAYER M3 ;
        RECT  124.128 0 124.146 0.038 ;
    END
  END b_own[189]
  PIN b_own[18]
    DIRECTION INPUT ;
    USE SIGNAL ;
    PORT
      LAYER M5 ;
        RECT  89.136 0 89.16 0.084 ;
    END
  END b_own[18]
  PIN b_own[190]
    DIRECTION INPUT ;
    USE SIGNAL ;
    PORT
      LAYER M5 ;
        RECT  124.368 0 124.392 0.084 ;
    END
  END b_own[190]
  PIN b_own[191]
    DIRECTION INPUT ;
    USE SIGNAL ;
    PORT
      LAYER M3 ;
        RECT  124.488 0 124.506 0.038 ;
    END
  END b_own[191]
  PIN b_own[192]
    DIRECTION INPUT ;
    USE SIGNAL ;
    PORT
      LAYER M5 ;
        RECT  124.752 0 124.776 0.084 ;
    END
  END b_own[192]
  PIN b_own[193]
    DIRECTION INPUT ;
    USE SIGNAL ;
    PORT
      LAYER M3 ;
        RECT  124.884 0 124.902 0.038 ;
    END
  END b_own[193]
  PIN b_own[194]
    DIRECTION INPUT ;
    USE SIGNAL ;
    PORT
      LAYER M5 ;
        RECT  125.136 0 125.16 0.084 ;
    END
  END b_own[194]
  PIN b_own[195]
    DIRECTION INPUT ;
    USE SIGNAL ;
    PORT
      LAYER M3 ;
        RECT  125.352 0 125.37 0.038 ;
    END
  END b_own[195]
  PIN b_own[196]
    DIRECTION INPUT ;
    USE SIGNAL ;
    PORT
      LAYER M5 ;
        RECT  125.52 0 125.544 0.084 ;
    END
  END b_own[196]
  PIN b_own[197]
    DIRECTION INPUT ;
    USE SIGNAL ;
    PORT
      LAYER M3 ;
        RECT  125.748 0 125.766 0.038 ;
    END
  END b_own[197]
  PIN b_own[198]
    DIRECTION INPUT ;
    USE SIGNAL ;
    PORT
      LAYER M5 ;
        RECT  126 0 126.024 0.084 ;
    END
  END b_own[198]
  PIN b_own[199]
    DIRECTION INPUT ;
    USE SIGNAL ;
    PORT
      LAYER M3 ;
        RECT  126.144 0 126.162 0.038 ;
    END
  END b_own[199]
  PIN b_own[19]
    DIRECTION INPUT ;
    USE SIGNAL ;
    PORT
      LAYER M3 ;
        RECT  89.28 0 89.298 0.038 ;
    END
  END b_own[19]
  PIN b_own[1]
    DIRECTION INPUT ;
    USE SIGNAL ;
    PORT
      LAYER M3 ;
        RECT  85.608 0 85.626 0.038 ;
    END
  END b_own[1]
  PIN b_own[200]
    DIRECTION INPUT ;
    USE SIGNAL ;
    PORT
      LAYER M5 ;
        RECT  126.384 0 126.408 0.084 ;
    END
  END b_own[200]
  PIN b_own[201]
    DIRECTION INPUT ;
    USE SIGNAL ;
    PORT
      LAYER M3 ;
        RECT  126.612 0 126.63 0.038 ;
    END
  END b_own[201]
  PIN b_own[202]
    DIRECTION INPUT ;
    USE SIGNAL ;
    PORT
      LAYER M5 ;
        RECT  126.768 0 126.792 0.084 ;
    END
  END b_own[202]
  PIN b_own[203]
    DIRECTION INPUT ;
    USE SIGNAL ;
    PORT
      LAYER M3 ;
        RECT  127.008 0 127.026 0.038 ;
    END
  END b_own[203]
  PIN b_own[204]
    DIRECTION INPUT ;
    USE SIGNAL ;
    PORT
      LAYER M5 ;
        RECT  127.152 0 127.176 0.084 ;
    END
  END b_own[204]
  PIN b_own[205]
    DIRECTION INPUT ;
    USE SIGNAL ;
    PORT
      LAYER M3 ;
        RECT  127.368 0 127.386 0.038 ;
    END
  END b_own[205]
  PIN b_own[206]
    DIRECTION INPUT ;
    USE SIGNAL ;
    PORT
      LAYER M5 ;
        RECT  127.632 0 127.656 0.084 ;
    END
  END b_own[206]
  PIN b_own[207]
    DIRECTION INPUT ;
    USE SIGNAL ;
    PORT
      LAYER M3 ;
        RECT  127.764 0 127.782 0.038 ;
    END
  END b_own[207]
  PIN b_own[208]
    DIRECTION INPUT ;
    USE SIGNAL ;
    PORT
      LAYER M5 ;
        RECT  128.016 0 128.04 0.084 ;
    END
  END b_own[208]
  PIN b_own[209]
    DIRECTION INPUT ;
    USE SIGNAL ;
    PORT
      LAYER M3 ;
        RECT  128.232 0 128.25 0.038 ;
    END
  END b_own[209]
  PIN b_own[20]
    DIRECTION INPUT ;
    USE SIGNAL ;
    PORT
      LAYER M5 ;
        RECT  89.52 0 89.544 0.084 ;
    END
  END b_own[20]
  PIN b_own[210]
    DIRECTION INPUT ;
    USE SIGNAL ;
    PORT
      LAYER M5 ;
        RECT  128.4 0 128.424 0.084 ;
    END
  END b_own[210]
  PIN b_own[211]
    DIRECTION INPUT ;
    USE SIGNAL ;
    PORT
      LAYER M3 ;
        RECT  128.628 0 128.646 0.038 ;
    END
  END b_own[211]
  PIN b_own[212]
    DIRECTION INPUT ;
    USE SIGNAL ;
    PORT
      LAYER M5 ;
        RECT  128.784 0 128.808 0.084 ;
    END
  END b_own[212]
  PIN b_own[213]
    DIRECTION INPUT ;
    USE SIGNAL ;
    PORT
      LAYER M3 ;
        RECT  129.024 0 129.042 0.038 ;
    END
  END b_own[213]
  PIN b_own[214]
    DIRECTION INPUT ;
    USE SIGNAL ;
    PORT
      LAYER M5 ;
        RECT  129.264 0 129.288 0.084 ;
    END
  END b_own[214]
  PIN b_own[215]
    DIRECTION INPUT ;
    USE SIGNAL ;
    PORT
      LAYER M3 ;
        RECT  129.384 0 129.402 0.038 ;
    END
  END b_own[215]
  PIN b_own[216]
    DIRECTION INPUT ;
    USE SIGNAL ;
    PORT
      LAYER M5 ;
        RECT  129.648 0 129.672 0.084 ;
    END
  END b_own[216]
  PIN b_own[217]
    DIRECTION INPUT ;
    USE SIGNAL ;
    PORT
      LAYER M3 ;
        RECT  129.888 0 129.906 0.038 ;
    END
  END b_own[217]
  PIN b_own[218]
    DIRECTION INPUT ;
    USE SIGNAL ;
    PORT
      LAYER M5 ;
        RECT  130.032 0 130.056 0.084 ;
    END
  END b_own[218]
  PIN b_own[219]
    DIRECTION INPUT ;
    USE SIGNAL ;
    PORT
      LAYER M3 ;
        RECT  130.248 0 130.266 0.038 ;
    END
  END b_own[219]
  PIN b_own[21]
    DIRECTION INPUT ;
    USE SIGNAL ;
    PORT
      LAYER M3 ;
        RECT  89.748 0 89.766 0.038 ;
    END
  END b_own[21]
  PIN b_own[220]
    DIRECTION INPUT ;
    USE SIGNAL ;
    PORT
      LAYER M5 ;
        RECT  130.512 0 130.536 0.084 ;
    END
  END b_own[220]
  PIN b_own[221]
    DIRECTION INPUT ;
    USE SIGNAL ;
    PORT
      LAYER M3 ;
        RECT  130.644 0 130.662 0.038 ;
    END
  END b_own[221]
  PIN b_own[222]
    DIRECTION INPUT ;
    USE SIGNAL ;
    PORT
      LAYER M5 ;
        RECT  130.896 0 130.92 0.084 ;
    END
  END b_own[222]
  PIN b_own[223]
    DIRECTION INPUT ;
    USE SIGNAL ;
    PORT
      LAYER M3 ;
        RECT  131.112 0 131.13 0.038 ;
    END
  END b_own[223]
  PIN b_own[224]
    DIRECTION INPUT ;
    USE SIGNAL ;
    PORT
      LAYER M5 ;
        RECT  131.472 0 131.496 0.084 ;
    END
  END b_own[224]
  PIN b_own[225]
    DIRECTION INPUT ;
    USE SIGNAL ;
    PORT
      LAYER M3 ;
        RECT  131.904 0 131.922 0.038 ;
    END
  END b_own[225]
  PIN b_own[226]
    DIRECTION INPUT ;
    USE SIGNAL ;
    PORT
      LAYER M5 ;
        RECT  132.24 0 132.264 0.084 ;
    END
  END b_own[226]
  PIN b_own[227]
    DIRECTION INPUT ;
    USE SIGNAL ;
    PORT
      LAYER M3 ;
        RECT  132.552 0 132.57 0.038 ;
    END
  END b_own[227]
  PIN b_own[228]
    DIRECTION INPUT ;
    USE SIGNAL ;
    PORT
      LAYER M5 ;
        RECT  133.008 0 133.032 0.084 ;
    END
  END b_own[228]
  PIN b_own[229]
    DIRECTION INPUT ;
    USE SIGNAL ;
    PORT
      LAYER M3 ;
        RECT  133.344 0 133.362 0.038 ;
    END
  END b_own[229]
  PIN b_own[22]
    DIRECTION INPUT ;
    USE SIGNAL ;
    PORT
      LAYER M5 ;
        RECT  89.904 0 89.928 0.084 ;
    END
  END b_own[22]
  PIN b_own[230]
    DIRECTION INPUT ;
    USE SIGNAL ;
    PORT
      LAYER M5 ;
        RECT  133.68 0 133.704 0.084 ;
    END
  END b_own[230]
  PIN b_own[231]
    DIRECTION INPUT ;
    USE SIGNAL ;
    PORT
      LAYER M3 ;
        RECT  134.1 0 134.118 0.038 ;
    END
  END b_own[231]
  PIN b_own[232]
    DIRECTION INPUT ;
    USE SIGNAL ;
    PORT
      LAYER M5 ;
        RECT  134.448 0 134.472 0.084 ;
    END
  END b_own[232]
  PIN b_own[233]
    DIRECTION INPUT ;
    USE SIGNAL ;
    PORT
      LAYER M3 ;
        RECT  134.856 0 134.874 0.038 ;
    END
  END b_own[233]
  PIN b_own[234]
    DIRECTION INPUT ;
    USE SIGNAL ;
    PORT
      LAYER M5 ;
        RECT  135.216 0 135.24 0.084 ;
    END
  END b_own[234]
  PIN b_own[235]
    DIRECTION INPUT ;
    USE SIGNAL ;
    PORT
      LAYER M3 ;
        RECT  135.54 0 135.558 0.038 ;
    END
  END b_own[235]
  PIN b_own[236]
    DIRECTION INPUT ;
    USE SIGNAL ;
    PORT
      LAYER M5 ;
        RECT  135.984 0 136.008 0.084 ;
    END
  END b_own[236]
  PIN b_own[237]
    DIRECTION INPUT ;
    USE SIGNAL ;
    PORT
      LAYER M3 ;
        RECT  136.296 0 136.314 0.038 ;
    END
  END b_own[237]
  PIN b_own[238]
    DIRECTION INPUT ;
    USE SIGNAL ;
    PORT
      LAYER M5 ;
        RECT  136.656 0 136.68 0.084 ;
    END
  END b_own[238]
  PIN b_own[239]
    DIRECTION INPUT ;
    USE SIGNAL ;
    PORT
      LAYER M3 ;
        RECT  137.088 0 137.106 0.038 ;
    END
  END b_own[239]
  PIN b_own[23]
    DIRECTION INPUT ;
    USE SIGNAL ;
    PORT
      LAYER M3 ;
        RECT  90.144 0 90.162 0.038 ;
    END
  END b_own[23]
  PIN b_own[240]
    DIRECTION INPUT ;
    USE SIGNAL ;
    PORT
      LAYER M5 ;
        RECT  137.424 0 137.448 0.084 ;
    END
  END b_own[240]
  PIN b_own[241]
    DIRECTION INPUT ;
    USE SIGNAL ;
    PORT
      LAYER M3 ;
        RECT  137.844 0 137.862 0.038 ;
    END
  END b_own[241]
  PIN b_own[242]
    DIRECTION INPUT ;
    USE SIGNAL ;
    PORT
      LAYER M5 ;
        RECT  138.192 0 138.216 0.084 ;
    END
  END b_own[242]
  PIN b_own[243]
    DIRECTION INPUT ;
    USE SIGNAL ;
    PORT
      LAYER M3 ;
        RECT  138.528 0 138.546 0.038 ;
    END
  END b_own[243]
  PIN b_own[244]
    DIRECTION INPUT ;
    USE SIGNAL ;
    PORT
      LAYER M5 ;
        RECT  138.96 0 138.984 0.084 ;
    END
  END b_own[244]
  PIN b_own[245]
    DIRECTION INPUT ;
    USE SIGNAL ;
    PORT
      LAYER M3 ;
        RECT  139.284 0 139.302 0.038 ;
    END
  END b_own[245]
  PIN b_own[246]
    DIRECTION INPUT ;
    USE SIGNAL ;
    PORT
      LAYER M5 ;
        RECT  139.632 0 139.656 0.084 ;
    END
  END b_own[246]
  PIN b_own[247]
    DIRECTION INPUT ;
    USE SIGNAL ;
    PORT
      LAYER M3 ;
        RECT  140.04 0 140.058 0.038 ;
    END
  END b_own[247]
  PIN b_own[248]
    DIRECTION INPUT ;
    USE SIGNAL ;
    PORT
      LAYER M5 ;
        RECT  140.4 0 140.424 0.084 ;
    END
  END b_own[248]
  PIN b_own[249]
    DIRECTION INPUT ;
    USE SIGNAL ;
    PORT
      LAYER M3 ;
        RECT  140.832 0 140.85 0.038 ;
    END
  END b_own[249]
  PIN b_own[24]
    DIRECTION INPUT ;
    USE SIGNAL ;
    PORT
      LAYER M5 ;
        RECT  90.384 0 90.408 0.084 ;
    END
  END b_own[24]
  PIN b_own[250]
    DIRECTION INPUT ;
    USE SIGNAL ;
    PORT
      LAYER M5 ;
        RECT  141.168 0 141.192 0.084 ;
    END
  END b_own[250]
  PIN b_own[251]
    DIRECTION INPUT ;
    USE SIGNAL ;
    PORT
      LAYER M3 ;
        RECT  141.48 0 141.498 0.038 ;
    END
  END b_own[251]
  PIN b_own[252]
    DIRECTION INPUT ;
    USE SIGNAL ;
    PORT
      LAYER M5 ;
        RECT  141.936 0 141.96 0.084 ;
    END
  END b_own[252]
  PIN b_own[253]
    DIRECTION INPUT ;
    USE SIGNAL ;
    PORT
      LAYER M3 ;
        RECT  142.272 0 142.29 0.038 ;
    END
  END b_own[253]
  PIN b_own[254]
    DIRECTION INPUT ;
    USE SIGNAL ;
    PORT
      LAYER M5 ;
        RECT  142.704 0 142.728 0.084 ;
    END
  END b_own[254]
  PIN b_own[255]
    DIRECTION INPUT ;
    USE SIGNAL ;
    PORT
      LAYER M3 ;
        RECT  143.028 0 143.046 0.038 ;
    END
  END b_own[255]
  PIN b_own[25]
    DIRECTION INPUT ;
    USE SIGNAL ;
    PORT
      LAYER M3 ;
        RECT  90.504 0 90.522 0.038 ;
    END
  END b_own[25]
  PIN b_own[26]
    DIRECTION INPUT ;
    USE SIGNAL ;
    PORT
      LAYER M5 ;
        RECT  90.768 0 90.792 0.084 ;
    END
  END b_own[26]
  PIN b_own[27]
    DIRECTION INPUT ;
    USE SIGNAL ;
    PORT
      LAYER M3 ;
        RECT  90.9 0 90.918 0.038 ;
    END
  END b_own[27]
  PIN b_own[28]
    DIRECTION INPUT ;
    USE SIGNAL ;
    PORT
      LAYER M5 ;
        RECT  91.152 0 91.176 0.084 ;
    END
  END b_own[28]
  PIN b_own[29]
    DIRECTION INPUT ;
    USE SIGNAL ;
    PORT
      LAYER M3 ;
        RECT  91.368 0 91.386 0.038 ;
    END
  END b_own[29]
  PIN b_own[2]
    DIRECTION INPUT ;
    USE SIGNAL ;
    PORT
      LAYER M5 ;
        RECT  85.872 0 85.896 0.084 ;
    END
  END b_own[2]
  PIN b_own[30]
    DIRECTION INPUT ;
    USE SIGNAL ;
    PORT
      LAYER M5 ;
        RECT  91.536 0 91.56 0.084 ;
    END
  END b_own[30]
  PIN b_own[31]
    DIRECTION INPUT ;
    USE SIGNAL ;
    PORT
      LAYER M3 ;
        RECT  91.764 0 91.782 0.038 ;
    END
  END b_own[31]
  PIN b_own[32]
    DIRECTION INPUT ;
    USE SIGNAL ;
    PORT
      LAYER M5 ;
        RECT  92.016 0 92.04 0.084 ;
    END
  END b_own[32]
  PIN b_own[33]
    DIRECTION INPUT ;
    USE SIGNAL ;
    PORT
      LAYER M3 ;
        RECT  92.16 0 92.178 0.038 ;
    END
  END b_own[33]
  PIN b_own[34]
    DIRECTION INPUT ;
    USE SIGNAL ;
    PORT
      LAYER M5 ;
        RECT  92.4 0 92.424 0.084 ;
    END
  END b_own[34]
  PIN b_own[35]
    DIRECTION INPUT ;
    USE SIGNAL ;
    PORT
      LAYER M3 ;
        RECT  92.52 0 92.538 0.038 ;
    END
  END b_own[35]
  PIN b_own[36]
    DIRECTION INPUT ;
    USE SIGNAL ;
    PORT
      LAYER M5 ;
        RECT  92.784 0 92.808 0.084 ;
    END
  END b_own[36]
  PIN b_own[37]
    DIRECTION INPUT ;
    USE SIGNAL ;
    PORT
      LAYER M3 ;
        RECT  93.024 0 93.042 0.038 ;
    END
  END b_own[37]
  PIN b_own[38]
    DIRECTION INPUT ;
    USE SIGNAL ;
    PORT
      LAYER M5 ;
        RECT  93.168 0 93.192 0.084 ;
    END
  END b_own[38]
  PIN b_own[39]
    DIRECTION INPUT ;
    USE SIGNAL ;
    PORT
      LAYER M3 ;
        RECT  93.384 0 93.402 0.038 ;
    END
  END b_own[39]
  PIN b_own[3]
    DIRECTION INPUT ;
    USE SIGNAL ;
    PORT
      LAYER M3 ;
        RECT  86.004 0 86.022 0.038 ;
    END
  END b_own[3]
  PIN b_own[40]
    DIRECTION INPUT ;
    USE SIGNAL ;
    PORT
      LAYER M5 ;
        RECT  93.648 0 93.672 0.084 ;
    END
  END b_own[40]
  PIN b_own[41]
    DIRECTION INPUT ;
    USE SIGNAL ;
    PORT
      LAYER M3 ;
        RECT  93.78 0 93.798 0.038 ;
    END
  END b_own[41]
  PIN b_own[42]
    DIRECTION INPUT ;
    USE SIGNAL ;
    PORT
      LAYER M5 ;
        RECT  94.032 0 94.056 0.084 ;
    END
  END b_own[42]
  PIN b_own[43]
    DIRECTION INPUT ;
    USE SIGNAL ;
    PORT
      LAYER M3 ;
        RECT  94.248 0 94.266 0.038 ;
    END
  END b_own[43]
  PIN b_own[44]
    DIRECTION INPUT ;
    USE SIGNAL ;
    PORT
      LAYER M5 ;
        RECT  94.416 0 94.44 0.084 ;
    END
  END b_own[44]
  PIN b_own[45]
    DIRECTION INPUT ;
    USE SIGNAL ;
    PORT
      LAYER M3 ;
        RECT  94.644 0 94.662 0.038 ;
    END
  END b_own[45]
  PIN b_own[46]
    DIRECTION INPUT ;
    USE SIGNAL ;
    PORT
      LAYER M5 ;
        RECT  94.8 0 94.824 0.084 ;
    END
  END b_own[46]
  PIN b_own[47]
    DIRECTION INPUT ;
    USE SIGNAL ;
    PORT
      LAYER M3 ;
        RECT  95.04 0 95.058 0.038 ;
    END
  END b_own[47]
  PIN b_own[48]
    DIRECTION INPUT ;
    USE SIGNAL ;
    PORT
      LAYER M5 ;
        RECT  95.28 0 95.304 0.084 ;
    END
  END b_own[48]
  PIN b_own[49]
    DIRECTION INPUT ;
    USE SIGNAL ;
    PORT
      LAYER M3 ;
        RECT  95.4 0 95.418 0.038 ;
    END
  END b_own[49]
  PIN b_own[4]
    DIRECTION INPUT ;
    USE SIGNAL ;
    PORT
      LAYER M5 ;
        RECT  86.256 0 86.28 0.084 ;
    END
  END b_own[4]
  PIN b_own[50]
    DIRECTION INPUT ;
    USE SIGNAL ;
    PORT
      LAYER M5 ;
        RECT  95.664 0 95.688 0.084 ;
    END
  END b_own[50]
  PIN b_own[51]
    DIRECTION INPUT ;
    USE SIGNAL ;
    PORT
      LAYER M3 ;
        RECT  95.904 0 95.922 0.038 ;
    END
  END b_own[51]
  PIN b_own[52]
    DIRECTION INPUT ;
    USE SIGNAL ;
    PORT
      LAYER M5 ;
        RECT  96.048 0 96.072 0.084 ;
    END
  END b_own[52]
  PIN b_own[53]
    DIRECTION INPUT ;
    USE SIGNAL ;
    PORT
      LAYER M3 ;
        RECT  96.264 0 96.282 0.038 ;
    END
  END b_own[53]
  PIN b_own[54]
    DIRECTION INPUT ;
    USE SIGNAL ;
    PORT
      LAYER M5 ;
        RECT  96.528 0 96.552 0.084 ;
    END
  END b_own[54]
  PIN b_own[55]
    DIRECTION INPUT ;
    USE SIGNAL ;
    PORT
      LAYER M3 ;
        RECT  96.66 0 96.678 0.038 ;
    END
  END b_own[55]
  PIN b_own[56]
    DIRECTION INPUT ;
    USE SIGNAL ;
    PORT
      LAYER M5 ;
        RECT  96.912 0 96.936 0.084 ;
    END
  END b_own[56]
  PIN b_own[57]
    DIRECTION INPUT ;
    USE SIGNAL ;
    PORT
      LAYER M3 ;
        RECT  97.056 0 97.074 0.038 ;
    END
  END b_own[57]
  PIN b_own[58]
    DIRECTION INPUT ;
    USE SIGNAL ;
    PORT
      LAYER M5 ;
        RECT  97.296 0 97.32 0.084 ;
    END
  END b_own[58]
  PIN b_own[59]
    DIRECTION INPUT ;
    USE SIGNAL ;
    PORT
      LAYER M3 ;
        RECT  97.524 0 97.542 0.038 ;
    END
  END b_own[59]
  PIN b_own[5]
    DIRECTION INPUT ;
    USE SIGNAL ;
    PORT
      LAYER M3 ;
        RECT  86.472 0 86.49 0.038 ;
    END
  END b_own[5]
  PIN b_own[60]
    DIRECTION INPUT ;
    USE SIGNAL ;
    PORT
      LAYER M5 ;
        RECT  97.68 0 97.704 0.084 ;
    END
  END b_own[60]
  PIN b_own[61]
    DIRECTION INPUT ;
    USE SIGNAL ;
    PORT
      LAYER M3 ;
        RECT  97.92 0 97.938 0.038 ;
    END
  END b_own[61]
  PIN b_own[62]
    DIRECTION INPUT ;
    USE SIGNAL ;
    PORT
      LAYER M5 ;
        RECT  98.16 0 98.184 0.084 ;
    END
  END b_own[62]
  PIN b_own[63]
    DIRECTION INPUT ;
    USE SIGNAL ;
    PORT
      LAYER M3 ;
        RECT  98.28 0 98.298 0.038 ;
    END
  END b_own[63]
  PIN b_own[64]
    DIRECTION INPUT ;
    USE SIGNAL ;
    PORT
      LAYER M5 ;
        RECT  98.544 0 98.568 0.084 ;
    END
  END b_own[64]
  PIN b_own[65]
    DIRECTION INPUT ;
    USE SIGNAL ;
    PORT
      LAYER M3 ;
        RECT  98.676 0 98.694 0.038 ;
    END
  END b_own[65]
  PIN b_own[66]
    DIRECTION INPUT ;
    USE SIGNAL ;
    PORT
      LAYER M5 ;
        RECT  98.928 0 98.952 0.084 ;
    END
  END b_own[66]
  PIN b_own[67]
    DIRECTION INPUT ;
    USE SIGNAL ;
    PORT
      LAYER M3 ;
        RECT  99.144 0 99.162 0.038 ;
    END
  END b_own[67]
  PIN b_own[68]
    DIRECTION INPUT ;
    USE SIGNAL ;
    PORT
      LAYER M5 ;
        RECT  99.312 0 99.336 0.084 ;
    END
  END b_own[68]
  PIN b_own[69]
    DIRECTION INPUT ;
    USE SIGNAL ;
    PORT
      LAYER M3 ;
        RECT  99.54 0 99.558 0.038 ;
    END
  END b_own[69]
  PIN b_own[6]
    DIRECTION INPUT ;
    USE SIGNAL ;
    PORT
      LAYER M5 ;
        RECT  86.64 0 86.664 0.084 ;
    END
  END b_own[6]
  PIN b_own[70]
    DIRECTION INPUT ;
    USE SIGNAL ;
    PORT
      LAYER M5 ;
        RECT  99.792 0 99.816 0.084 ;
    END
  END b_own[70]
  PIN b_own[71]
    DIRECTION INPUT ;
    USE SIGNAL ;
    PORT
      LAYER M3 ;
        RECT  99.936 0 99.954 0.038 ;
    END
  END b_own[71]
  PIN b_own[72]
    DIRECTION INPUT ;
    USE SIGNAL ;
    PORT
      LAYER M5 ;
        RECT  100.176 0 100.2 0.084 ;
    END
  END b_own[72]
  PIN b_own[73]
    DIRECTION INPUT ;
    USE SIGNAL ;
    PORT
      LAYER M3 ;
        RECT  100.404 0 100.422 0.038 ;
    END
  END b_own[73]
  PIN b_own[74]
    DIRECTION INPUT ;
    USE SIGNAL ;
    PORT
      LAYER M5 ;
        RECT  100.56 0 100.584 0.084 ;
    END
  END b_own[74]
  PIN b_own[75]
    DIRECTION INPUT ;
    USE SIGNAL ;
    PORT
      LAYER M3 ;
        RECT  100.8 0 100.818 0.038 ;
    END
  END b_own[75]
  PIN b_own[76]
    DIRECTION INPUT ;
    USE SIGNAL ;
    PORT
      LAYER M5 ;
        RECT  100.944 0 100.968 0.084 ;
    END
  END b_own[76]
  PIN b_own[77]
    DIRECTION INPUT ;
    USE SIGNAL ;
    PORT
      LAYER M3 ;
        RECT  101.16 0 101.178 0.038 ;
    END
  END b_own[77]
  PIN b_own[78]
    DIRECTION INPUT ;
    USE SIGNAL ;
    PORT
      LAYER M5 ;
        RECT  101.424 0 101.448 0.084 ;
    END
  END b_own[78]
  PIN b_own[79]
    DIRECTION INPUT ;
    USE SIGNAL ;
    PORT
      LAYER M3 ;
        RECT  101.556 0 101.574 0.038 ;
    END
  END b_own[79]
  PIN b_own[7]
    DIRECTION INPUT ;
    USE SIGNAL ;
    PORT
      LAYER M3 ;
        RECT  86.868 0 86.886 0.038 ;
    END
  END b_own[7]
  PIN b_own[80]
    DIRECTION INPUT ;
    USE SIGNAL ;
    PORT
      LAYER M5 ;
        RECT  101.808 0 101.832 0.084 ;
    END
  END b_own[80]
  PIN b_own[81]
    DIRECTION INPUT ;
    USE SIGNAL ;
    PORT
      LAYER M3 ;
        RECT  102.024 0 102.042 0.038 ;
    END
  END b_own[81]
  PIN b_own[82]
    DIRECTION INPUT ;
    USE SIGNAL ;
    PORT
      LAYER M5 ;
        RECT  102.192 0 102.216 0.084 ;
    END
  END b_own[82]
  PIN b_own[83]
    DIRECTION INPUT ;
    USE SIGNAL ;
    PORT
      LAYER M3 ;
        RECT  102.42 0 102.438 0.038 ;
    END
  END b_own[83]
  PIN b_own[84]
    DIRECTION INPUT ;
    USE SIGNAL ;
    PORT
      LAYER M5 ;
        RECT  102.576 0 102.6 0.084 ;
    END
  END b_own[84]
  PIN b_own[85]
    DIRECTION INPUT ;
    USE SIGNAL ;
    PORT
      LAYER M3 ;
        RECT  102.816 0 102.834 0.038 ;
    END
  END b_own[85]
  PIN b_own[86]
    DIRECTION INPUT ;
    USE SIGNAL ;
    PORT
      LAYER M5 ;
        RECT  103.056 0 103.08 0.084 ;
    END
  END b_own[86]
  PIN b_own[87]
    DIRECTION INPUT ;
    USE SIGNAL ;
    PORT
      LAYER M3 ;
        RECT  103.176 0 103.194 0.038 ;
    END
  END b_own[87]
  PIN b_own[88]
    DIRECTION INPUT ;
    USE SIGNAL ;
    PORT
      LAYER M5 ;
        RECT  103.44 0 103.464 0.084 ;
    END
  END b_own[88]
  PIN b_own[89]
    DIRECTION INPUT ;
    USE SIGNAL ;
    PORT
      LAYER M3 ;
        RECT  103.68 0 103.698 0.038 ;
    END
  END b_own[89]
  PIN b_own[8]
    DIRECTION INPUT ;
    USE SIGNAL ;
    PORT
      LAYER M5 ;
        RECT  87.024 0 87.048 0.084 ;
    END
  END b_own[8]
  PIN b_own[90]
    DIRECTION INPUT ;
    USE SIGNAL ;
    PORT
      LAYER M5 ;
        RECT  103.824 0 103.848 0.084 ;
    END
  END b_own[90]
  PIN b_own[91]
    DIRECTION INPUT ;
    USE SIGNAL ;
    PORT
      LAYER M3 ;
        RECT  104.04 0 104.058 0.038 ;
    END
  END b_own[91]
  PIN b_own[92]
    DIRECTION INPUT ;
    USE SIGNAL ;
    PORT
      LAYER M5 ;
        RECT  104.304 0 104.328 0.084 ;
    END
  END b_own[92]
  PIN b_own[93]
    DIRECTION INPUT ;
    USE SIGNAL ;
    PORT
      LAYER M3 ;
        RECT  104.436 0 104.454 0.038 ;
    END
  END b_own[93]
  PIN b_own[94]
    DIRECTION INPUT ;
    USE SIGNAL ;
    PORT
      LAYER M5 ;
        RECT  104.688 0 104.712 0.084 ;
    END
  END b_own[94]
  PIN b_own[95]
    DIRECTION INPUT ;
    USE SIGNAL ;
    PORT
      LAYER M3 ;
        RECT  104.832 0 104.85 0.038 ;
    END
  END b_own[95]
  PIN b_own[96]
    DIRECTION INPUT ;
    USE SIGNAL ;
    PORT
      LAYER M5 ;
        RECT  105.072 0 105.096 0.084 ;
    END
  END b_own[96]
  PIN b_own[97]
    DIRECTION INPUT ;
    USE SIGNAL ;
    PORT
      LAYER M3 ;
        RECT  105.3 0 105.318 0.038 ;
    END
  END b_own[97]
  PIN b_own[98]
    DIRECTION INPUT ;
    USE SIGNAL ;
    PORT
      LAYER M5 ;
        RECT  105.456 0 105.48 0.084 ;
    END
  END b_own[98]
  PIN b_own[99]
    DIRECTION INPUT ;
    USE SIGNAL ;
    PORT
      LAYER M3 ;
        RECT  105.696 0 105.714 0.038 ;
    END
  END b_own[99]
  PIN b_own[9]
    DIRECTION INPUT ;
    USE SIGNAL ;
    PORT
      LAYER M3 ;
        RECT  87.264 0 87.282 0.038 ;
    END
  END b_own[9]
  PIN b_own_out[0]
    DIRECTION OUTPUT ;
    USE SIGNAL ;
    PORT
      LAYER M5 ;
        RECT  85.392 25.836 85.416 25.92 ;
    END
  END b_own_out[0]
  PIN b_own_out[100]
    DIRECTION OUTPUT ;
    USE SIGNAL ;
    PORT
      LAYER M5 ;
        RECT  105.936 25.836 105.96 25.92 ;
    END
  END b_own_out[100]
  PIN b_own_out[101]
    DIRECTION OUTPUT ;
    USE SIGNAL ;
    PORT
      LAYER M3 ;
        RECT  106.056 25.882 106.074 25.92 ;
    END
  END b_own_out[101]
  PIN b_own_out[102]
    DIRECTION OUTPUT ;
    USE SIGNAL ;
    PORT
      LAYER M5 ;
        RECT  106.32 25.836 106.344 25.92 ;
    END
  END b_own_out[102]
  PIN b_own_out[103]
    DIRECTION OUTPUT ;
    USE SIGNAL ;
    PORT
      LAYER M3 ;
        RECT  106.56 25.882 106.578 25.92 ;
    END
  END b_own_out[103]
  PIN b_own_out[104]
    DIRECTION OUTPUT ;
    USE SIGNAL ;
    PORT
      LAYER M5 ;
        RECT  106.704 25.836 106.728 25.92 ;
    END
  END b_own_out[104]
  PIN b_own_out[105]
    DIRECTION OUTPUT ;
    USE SIGNAL ;
    PORT
      LAYER M3 ;
        RECT  106.92 25.882 106.938 25.92 ;
    END
  END b_own_out[105]
  PIN b_own_out[106]
    DIRECTION OUTPUT ;
    USE SIGNAL ;
    PORT
      LAYER M5 ;
        RECT  107.088 25.836 107.112 25.92 ;
    END
  END b_own_out[106]
  PIN b_own_out[107]
    DIRECTION OUTPUT ;
    USE SIGNAL ;
    PORT
      LAYER M3 ;
        RECT  107.316 25.882 107.334 25.92 ;
    END
  END b_own_out[107]
  PIN b_own_out[108]
    DIRECTION OUTPUT ;
    USE SIGNAL ;
    PORT
      LAYER M5 ;
        RECT  107.568 25.836 107.592 25.92 ;
    END
  END b_own_out[108]
  PIN b_own_out[109]
    DIRECTION OUTPUT ;
    USE SIGNAL ;
    PORT
      LAYER M3 ;
        RECT  107.712 25.882 107.73 25.92 ;
    END
  END b_own_out[109]
  PIN b_own_out[10]
    DIRECTION OUTPUT ;
    USE SIGNAL ;
    PORT
      LAYER M5 ;
        RECT  87.504 25.836 87.528 25.92 ;
    END
  END b_own_out[10]
  PIN b_own_out[110]
    DIRECTION OUTPUT ;
    USE SIGNAL ;
    PORT
      LAYER M5 ;
        RECT  107.952 25.836 107.976 25.92 ;
    END
  END b_own_out[110]
  PIN b_own_out[111]
    DIRECTION OUTPUT ;
    USE SIGNAL ;
    PORT
      LAYER M3 ;
        RECT  108.18 25.882 108.198 25.92 ;
    END
  END b_own_out[111]
  PIN b_own_out[112]
    DIRECTION OUTPUT ;
    USE SIGNAL ;
    PORT
      LAYER M5 ;
        RECT  108.336 25.836 108.36 25.92 ;
    END
  END b_own_out[112]
  PIN b_own_out[113]
    DIRECTION OUTPUT ;
    USE SIGNAL ;
    PORT
      LAYER M3 ;
        RECT  108.576 25.882 108.594 25.92 ;
    END
  END b_own_out[113]
  PIN b_own_out[114]
    DIRECTION OUTPUT ;
    USE SIGNAL ;
    PORT
      LAYER M5 ;
        RECT  108.72 25.836 108.744 25.92 ;
    END
  END b_own_out[114]
  PIN b_own_out[115]
    DIRECTION OUTPUT ;
    USE SIGNAL ;
    PORT
      LAYER M3 ;
        RECT  108.936 25.882 108.954 25.92 ;
    END
  END b_own_out[115]
  PIN b_own_out[116]
    DIRECTION OUTPUT ;
    USE SIGNAL ;
    PORT
      LAYER M5 ;
        RECT  109.2 25.836 109.224 25.92 ;
    END
  END b_own_out[116]
  PIN b_own_out[117]
    DIRECTION OUTPUT ;
    USE SIGNAL ;
    PORT
      LAYER M3 ;
        RECT  109.332 25.882 109.35 25.92 ;
    END
  END b_own_out[117]
  PIN b_own_out[118]
    DIRECTION OUTPUT ;
    USE SIGNAL ;
    PORT
      LAYER M5 ;
        RECT  109.584 25.836 109.608 25.92 ;
    END
  END b_own_out[118]
  PIN b_own_out[119]
    DIRECTION OUTPUT ;
    USE SIGNAL ;
    PORT
      LAYER M3 ;
        RECT  109.8 25.882 109.818 25.92 ;
    END
  END b_own_out[119]
  PIN b_own_out[11]
    DIRECTION OUTPUT ;
    USE SIGNAL ;
    PORT
      LAYER M3 ;
        RECT  87.624 25.882 87.642 25.92 ;
    END
  END b_own_out[11]
  PIN b_own_out[120]
    DIRECTION OUTPUT ;
    USE SIGNAL ;
    PORT
      LAYER M5 ;
        RECT  109.968 25.836 109.992 25.92 ;
    END
  END b_own_out[120]
  PIN b_own_out[121]
    DIRECTION OUTPUT ;
    USE SIGNAL ;
    PORT
      LAYER M3 ;
        RECT  110.196 25.882 110.214 25.92 ;
    END
  END b_own_out[121]
  PIN b_own_out[122]
    DIRECTION OUTPUT ;
    USE SIGNAL ;
    PORT
      LAYER M5 ;
        RECT  110.448 25.836 110.472 25.92 ;
    END
  END b_own_out[122]
  PIN b_own_out[123]
    DIRECTION OUTPUT ;
    USE SIGNAL ;
    PORT
      LAYER M3 ;
        RECT  110.592 25.882 110.61 25.92 ;
    END
  END b_own_out[123]
  PIN b_own_out[124]
    DIRECTION OUTPUT ;
    USE SIGNAL ;
    PORT
      LAYER M5 ;
        RECT  110.832 25.836 110.856 25.92 ;
    END
  END b_own_out[124]
  PIN b_own_out[125]
    DIRECTION OUTPUT ;
    USE SIGNAL ;
    PORT
      LAYER M3 ;
        RECT  110.952 25.882 110.97 25.92 ;
    END
  END b_own_out[125]
  PIN b_own_out[126]
    DIRECTION OUTPUT ;
    USE SIGNAL ;
    PORT
      LAYER M5 ;
        RECT  111.216 25.836 111.24 25.92 ;
    END
  END b_own_out[126]
  PIN b_own_out[127]
    DIRECTION OUTPUT ;
    USE SIGNAL ;
    PORT
      LAYER M3 ;
        RECT  111.456 25.882 111.474 25.92 ;
    END
  END b_own_out[127]
  PIN b_own_out[128]
    DIRECTION OUTPUT ;
    USE SIGNAL ;
    PORT
      LAYER M5 ;
        RECT  111.6 25.836 111.624 25.92 ;
    END
  END b_own_out[128]
  PIN b_own_out[129]
    DIRECTION OUTPUT ;
    USE SIGNAL ;
    PORT
      LAYER M3 ;
        RECT  111.816 25.882 111.834 25.92 ;
    END
  END b_own_out[129]
  PIN b_own_out[12]
    DIRECTION OUTPUT ;
    USE SIGNAL ;
    PORT
      LAYER M5 ;
        RECT  87.888 25.836 87.912 25.92 ;
    END
  END b_own_out[12]
  PIN b_own_out[130]
    DIRECTION OUTPUT ;
    USE SIGNAL ;
    PORT
      LAYER M5 ;
        RECT  112.08 25.836 112.104 25.92 ;
    END
  END b_own_out[130]
  PIN b_own_out[131]
    DIRECTION OUTPUT ;
    USE SIGNAL ;
    PORT
      LAYER M3 ;
        RECT  112.212 25.882 112.23 25.92 ;
    END
  END b_own_out[131]
  PIN b_own_out[132]
    DIRECTION OUTPUT ;
    USE SIGNAL ;
    PORT
      LAYER M5 ;
        RECT  112.464 25.836 112.488 25.92 ;
    END
  END b_own_out[132]
  PIN b_own_out[133]
    DIRECTION OUTPUT ;
    USE SIGNAL ;
    PORT
      LAYER M3 ;
        RECT  112.608 25.882 112.626 25.92 ;
    END
  END b_own_out[133]
  PIN b_own_out[134]
    DIRECTION OUTPUT ;
    USE SIGNAL ;
    PORT
      LAYER M5 ;
        RECT  112.848 25.836 112.872 25.92 ;
    END
  END b_own_out[134]
  PIN b_own_out[135]
    DIRECTION OUTPUT ;
    USE SIGNAL ;
    PORT
      LAYER M3 ;
        RECT  113.076 25.882 113.094 25.92 ;
    END
  END b_own_out[135]
  PIN b_own_out[136]
    DIRECTION OUTPUT ;
    USE SIGNAL ;
    PORT
      LAYER M5 ;
        RECT  113.232 25.836 113.256 25.92 ;
    END
  END b_own_out[136]
  PIN b_own_out[137]
    DIRECTION OUTPUT ;
    USE SIGNAL ;
    PORT
      LAYER M3 ;
        RECT  113.472 25.882 113.49 25.92 ;
    END
  END b_own_out[137]
  PIN b_own_out[138]
    DIRECTION OUTPUT ;
    USE SIGNAL ;
    PORT
      LAYER M5 ;
        RECT  113.712 25.836 113.736 25.92 ;
    END
  END b_own_out[138]
  PIN b_own_out[139]
    DIRECTION OUTPUT ;
    USE SIGNAL ;
    PORT
      LAYER M3 ;
        RECT  113.832 25.882 113.85 25.92 ;
    END
  END b_own_out[139]
  PIN b_own_out[13]
    DIRECTION OUTPUT ;
    USE SIGNAL ;
    PORT
      LAYER M3 ;
        RECT  88.128 25.882 88.146 25.92 ;
    END
  END b_own_out[13]
  PIN b_own_out[140]
    DIRECTION OUTPUT ;
    USE SIGNAL ;
    PORT
      LAYER M5 ;
        RECT  114.096 25.836 114.12 25.92 ;
    END
  END b_own_out[140]
  PIN b_own_out[141]
    DIRECTION OUTPUT ;
    USE SIGNAL ;
    PORT
      LAYER M3 ;
        RECT  114.336 25.882 114.354 25.92 ;
    END
  END b_own_out[141]
  PIN b_own_out[142]
    DIRECTION OUTPUT ;
    USE SIGNAL ;
    PORT
      LAYER M5 ;
        RECT  114.48 25.836 114.504 25.92 ;
    END
  END b_own_out[142]
  PIN b_own_out[143]
    DIRECTION OUTPUT ;
    USE SIGNAL ;
    PORT
      LAYER M3 ;
        RECT  114.696 25.882 114.714 25.92 ;
    END
  END b_own_out[143]
  PIN b_own_out[144]
    DIRECTION OUTPUT ;
    USE SIGNAL ;
    PORT
      LAYER M5 ;
        RECT  114.864 25.836 114.888 25.92 ;
    END
  END b_own_out[144]
  PIN b_own_out[145]
    DIRECTION OUTPUT ;
    USE SIGNAL ;
    PORT
      LAYER M3 ;
        RECT  115.092 25.882 115.11 25.92 ;
    END
  END b_own_out[145]
  PIN b_own_out[146]
    DIRECTION OUTPUT ;
    USE SIGNAL ;
    PORT
      LAYER M5 ;
        RECT  115.344 25.836 115.368 25.92 ;
    END
  END b_own_out[146]
  PIN b_own_out[147]
    DIRECTION OUTPUT ;
    USE SIGNAL ;
    PORT
      LAYER M3 ;
        RECT  115.488 25.882 115.506 25.92 ;
    END
  END b_own_out[147]
  PIN b_own_out[148]
    DIRECTION OUTPUT ;
    USE SIGNAL ;
    PORT
      LAYER M5 ;
        RECT  115.728 25.836 115.752 25.92 ;
    END
  END b_own_out[148]
  PIN b_own_out[149]
    DIRECTION OUTPUT ;
    USE SIGNAL ;
    PORT
      LAYER M3 ;
        RECT  115.956 25.882 115.974 25.92 ;
    END
  END b_own_out[149]
  PIN b_own_out[14]
    DIRECTION OUTPUT ;
    USE SIGNAL ;
    PORT
      LAYER M5 ;
        RECT  88.272 25.836 88.296 25.92 ;
    END
  END b_own_out[14]
  PIN b_own_out[150]
    DIRECTION OUTPUT ;
    USE SIGNAL ;
    PORT
      LAYER M5 ;
        RECT  116.112 25.836 116.136 25.92 ;
    END
  END b_own_out[150]
  PIN b_own_out[151]
    DIRECTION OUTPUT ;
    USE SIGNAL ;
    PORT
      LAYER M3 ;
        RECT  116.352 25.882 116.37 25.92 ;
    END
  END b_own_out[151]
  PIN b_own_out[152]
    DIRECTION OUTPUT ;
    USE SIGNAL ;
    PORT
      LAYER M5 ;
        RECT  116.592 25.836 116.616 25.92 ;
    END
  END b_own_out[152]
  PIN b_own_out[153]
    DIRECTION OUTPUT ;
    USE SIGNAL ;
    PORT
      LAYER M3 ;
        RECT  116.712 25.882 116.73 25.92 ;
    END
  END b_own_out[153]
  PIN b_own_out[154]
    DIRECTION OUTPUT ;
    USE SIGNAL ;
    PORT
      LAYER M5 ;
        RECT  116.976 25.836 117 25.92 ;
    END
  END b_own_out[154]
  PIN b_own_out[155]
    DIRECTION OUTPUT ;
    USE SIGNAL ;
    PORT
      LAYER M3 ;
        RECT  117.108 25.882 117.126 25.92 ;
    END
  END b_own_out[155]
  PIN b_own_out[156]
    DIRECTION OUTPUT ;
    USE SIGNAL ;
    PORT
      LAYER M5 ;
        RECT  117.36 25.836 117.384 25.92 ;
    END
  END b_own_out[156]
  PIN b_own_out[157]
    DIRECTION OUTPUT ;
    USE SIGNAL ;
    PORT
      LAYER M3 ;
        RECT  117.576 25.882 117.594 25.92 ;
    END
  END b_own_out[157]
  PIN b_own_out[158]
    DIRECTION OUTPUT ;
    USE SIGNAL ;
    PORT
      LAYER M5 ;
        RECT  117.744 25.836 117.768 25.92 ;
    END
  END b_own_out[158]
  PIN b_own_out[159]
    DIRECTION OUTPUT ;
    USE SIGNAL ;
    PORT
      LAYER M3 ;
        RECT  117.972 25.882 117.99 25.92 ;
    END
  END b_own_out[159]
  PIN b_own_out[15]
    DIRECTION OUTPUT ;
    USE SIGNAL ;
    PORT
      LAYER M3 ;
        RECT  88.488 25.882 88.506 25.92 ;
    END
  END b_own_out[15]
  PIN b_own_out[160]
    DIRECTION OUTPUT ;
    USE SIGNAL ;
    PORT
      LAYER M5 ;
        RECT  118.224 25.836 118.248 25.92 ;
    END
  END b_own_out[160]
  PIN b_own_out[161]
    DIRECTION OUTPUT ;
    USE SIGNAL ;
    PORT
      LAYER M3 ;
        RECT  118.368 25.882 118.386 25.92 ;
    END
  END b_own_out[161]
  PIN b_own_out[162]
    DIRECTION OUTPUT ;
    USE SIGNAL ;
    PORT
      LAYER M5 ;
        RECT  118.608 25.836 118.632 25.92 ;
    END
  END b_own_out[162]
  PIN b_own_out[163]
    DIRECTION OUTPUT ;
    USE SIGNAL ;
    PORT
      LAYER M3 ;
        RECT  118.728 25.882 118.746 25.92 ;
    END
  END b_own_out[163]
  PIN b_own_out[164]
    DIRECTION OUTPUT ;
    USE SIGNAL ;
    PORT
      LAYER M5 ;
        RECT  118.992 25.836 119.016 25.92 ;
    END
  END b_own_out[164]
  PIN b_own_out[165]
    DIRECTION OUTPUT ;
    USE SIGNAL ;
    PORT
      LAYER M3 ;
        RECT  119.232 25.882 119.25 25.92 ;
    END
  END b_own_out[165]
  PIN b_own_out[166]
    DIRECTION OUTPUT ;
    USE SIGNAL ;
    PORT
      LAYER M5 ;
        RECT  119.376 25.836 119.4 25.92 ;
    END
  END b_own_out[166]
  PIN b_own_out[167]
    DIRECTION OUTPUT ;
    USE SIGNAL ;
    PORT
      LAYER M3 ;
        RECT  119.592 25.882 119.61 25.92 ;
    END
  END b_own_out[167]
  PIN b_own_out[168]
    DIRECTION OUTPUT ;
    USE SIGNAL ;
    PORT
      LAYER M5 ;
        RECT  119.856 25.836 119.88 25.92 ;
    END
  END b_own_out[168]
  PIN b_own_out[169]
    DIRECTION OUTPUT ;
    USE SIGNAL ;
    PORT
      LAYER M3 ;
        RECT  119.988 25.882 120.006 25.92 ;
    END
  END b_own_out[169]
  PIN b_own_out[16]
    DIRECTION OUTPUT ;
    USE SIGNAL ;
    PORT
      LAYER M5 ;
        RECT  88.656 25.836 88.68 25.92 ;
    END
  END b_own_out[16]
  PIN b_own_out[170]
    DIRECTION OUTPUT ;
    USE SIGNAL ;
    PORT
      LAYER M5 ;
        RECT  120.24 25.836 120.264 25.92 ;
    END
  END b_own_out[170]
  PIN b_own_out[171]
    DIRECTION OUTPUT ;
    USE SIGNAL ;
    PORT
      LAYER M3 ;
        RECT  120.456 25.882 120.474 25.92 ;
    END
  END b_own_out[171]
  PIN b_own_out[172]
    DIRECTION OUTPUT ;
    USE SIGNAL ;
    PORT
      LAYER M5 ;
        RECT  120.624 25.836 120.648 25.92 ;
    END
  END b_own_out[172]
  PIN b_own_out[173]
    DIRECTION OUTPUT ;
    USE SIGNAL ;
    PORT
      LAYER M3 ;
        RECT  120.852 25.882 120.87 25.92 ;
    END
  END b_own_out[173]
  PIN b_own_out[174]
    DIRECTION OUTPUT ;
    USE SIGNAL ;
    PORT
      LAYER M5 ;
        RECT  121.008 25.836 121.032 25.92 ;
    END
  END b_own_out[174]
  PIN b_own_out[175]
    DIRECTION OUTPUT ;
    USE SIGNAL ;
    PORT
      LAYER M3 ;
        RECT  121.248 25.882 121.266 25.92 ;
    END
  END b_own_out[175]
  PIN b_own_out[176]
    DIRECTION OUTPUT ;
    USE SIGNAL ;
    PORT
      LAYER M5 ;
        RECT  121.488 25.836 121.512 25.92 ;
    END
  END b_own_out[176]
  PIN b_own_out[177]
    DIRECTION OUTPUT ;
    USE SIGNAL ;
    PORT
      LAYER M3 ;
        RECT  121.608 25.882 121.626 25.92 ;
    END
  END b_own_out[177]
  PIN b_own_out[178]
    DIRECTION OUTPUT ;
    USE SIGNAL ;
    PORT
      LAYER M5 ;
        RECT  121.872 25.836 121.896 25.92 ;
    END
  END b_own_out[178]
  PIN b_own_out[179]
    DIRECTION OUTPUT ;
    USE SIGNAL ;
    PORT
      LAYER M3 ;
        RECT  122.112 25.882 122.13 25.92 ;
    END
  END b_own_out[179]
  PIN b_own_out[17]
    DIRECTION OUTPUT ;
    USE SIGNAL ;
    PORT
      LAYER M3 ;
        RECT  88.884 25.882 88.902 25.92 ;
    END
  END b_own_out[17]
  PIN b_own_out[180]
    DIRECTION OUTPUT ;
    USE SIGNAL ;
    PORT
      LAYER M5 ;
        RECT  122.256 25.836 122.28 25.92 ;
    END
  END b_own_out[180]
  PIN b_own_out[181]
    DIRECTION OUTPUT ;
    USE SIGNAL ;
    PORT
      LAYER M3 ;
        RECT  122.472 25.882 122.49 25.92 ;
    END
  END b_own_out[181]
  PIN b_own_out[182]
    DIRECTION OUTPUT ;
    USE SIGNAL ;
    PORT
      LAYER M5 ;
        RECT  122.64 25.836 122.664 25.92 ;
    END
  END b_own_out[182]
  PIN b_own_out[183]
    DIRECTION OUTPUT ;
    USE SIGNAL ;
    PORT
      LAYER M3 ;
        RECT  122.868 25.882 122.886 25.92 ;
    END
  END b_own_out[183]
  PIN b_own_out[184]
    DIRECTION OUTPUT ;
    USE SIGNAL ;
    PORT
      LAYER M5 ;
        RECT  123.12 25.836 123.144 25.92 ;
    END
  END b_own_out[184]
  PIN b_own_out[185]
    DIRECTION OUTPUT ;
    USE SIGNAL ;
    PORT
      LAYER M3 ;
        RECT  123.264 25.882 123.282 25.92 ;
    END
  END b_own_out[185]
  PIN b_own_out[186]
    DIRECTION OUTPUT ;
    USE SIGNAL ;
    PORT
      LAYER M5 ;
        RECT  123.504 25.836 123.528 25.92 ;
    END
  END b_own_out[186]
  PIN b_own_out[187]
    DIRECTION OUTPUT ;
    USE SIGNAL ;
    PORT
      LAYER M3 ;
        RECT  123.732 25.882 123.75 25.92 ;
    END
  END b_own_out[187]
  PIN b_own_out[188]
    DIRECTION OUTPUT ;
    USE SIGNAL ;
    PORT
      LAYER M5 ;
        RECT  123.888 25.836 123.912 25.92 ;
    END
  END b_own_out[188]
  PIN b_own_out[189]
    DIRECTION OUTPUT ;
    USE SIGNAL ;
    PORT
      LAYER M3 ;
        RECT  124.128 25.882 124.146 25.92 ;
    END
  END b_own_out[189]
  PIN b_own_out[18]
    DIRECTION OUTPUT ;
    USE SIGNAL ;
    PORT
      LAYER M5 ;
        RECT  89.136 25.836 89.16 25.92 ;
    END
  END b_own_out[18]
  PIN b_own_out[190]
    DIRECTION OUTPUT ;
    USE SIGNAL ;
    PORT
      LAYER M5 ;
        RECT  124.368 25.836 124.392 25.92 ;
    END
  END b_own_out[190]
  PIN b_own_out[191]
    DIRECTION OUTPUT ;
    USE SIGNAL ;
    PORT
      LAYER M3 ;
        RECT  124.488 25.882 124.506 25.92 ;
    END
  END b_own_out[191]
  PIN b_own_out[192]
    DIRECTION OUTPUT ;
    USE SIGNAL ;
    PORT
      LAYER M5 ;
        RECT  124.752 25.836 124.776 25.92 ;
    END
  END b_own_out[192]
  PIN b_own_out[193]
    DIRECTION OUTPUT ;
    USE SIGNAL ;
    PORT
      LAYER M3 ;
        RECT  124.884 25.882 124.902 25.92 ;
    END
  END b_own_out[193]
  PIN b_own_out[194]
    DIRECTION OUTPUT ;
    USE SIGNAL ;
    PORT
      LAYER M5 ;
        RECT  125.136 25.836 125.16 25.92 ;
    END
  END b_own_out[194]
  PIN b_own_out[195]
    DIRECTION OUTPUT ;
    USE SIGNAL ;
    PORT
      LAYER M3 ;
        RECT  125.352 25.882 125.37 25.92 ;
    END
  END b_own_out[195]
  PIN b_own_out[196]
    DIRECTION OUTPUT ;
    USE SIGNAL ;
    PORT
      LAYER M5 ;
        RECT  125.52 25.836 125.544 25.92 ;
    END
  END b_own_out[196]
  PIN b_own_out[197]
    DIRECTION OUTPUT ;
    USE SIGNAL ;
    PORT
      LAYER M3 ;
        RECT  125.748 25.882 125.766 25.92 ;
    END
  END b_own_out[197]
  PIN b_own_out[198]
    DIRECTION OUTPUT ;
    USE SIGNAL ;
    PORT
      LAYER M5 ;
        RECT  126 25.836 126.024 25.92 ;
    END
  END b_own_out[198]
  PIN b_own_out[199]
    DIRECTION OUTPUT ;
    USE SIGNAL ;
    PORT
      LAYER M3 ;
        RECT  126.144 25.882 126.162 25.92 ;
    END
  END b_own_out[199]
  PIN b_own_out[19]
    DIRECTION OUTPUT ;
    USE SIGNAL ;
    PORT
      LAYER M3 ;
        RECT  89.28 25.882 89.298 25.92 ;
    END
  END b_own_out[19]
  PIN b_own_out[1]
    DIRECTION OUTPUT ;
    USE SIGNAL ;
    PORT
      LAYER M3 ;
        RECT  85.608 25.882 85.626 25.92 ;
    END
  END b_own_out[1]
  PIN b_own_out[200]
    DIRECTION OUTPUT ;
    USE SIGNAL ;
    PORT
      LAYER M5 ;
        RECT  126.384 25.836 126.408 25.92 ;
    END
  END b_own_out[200]
  PIN b_own_out[201]
    DIRECTION OUTPUT ;
    USE SIGNAL ;
    PORT
      LAYER M3 ;
        RECT  126.612 25.882 126.63 25.92 ;
    END
  END b_own_out[201]
  PIN b_own_out[202]
    DIRECTION OUTPUT ;
    USE SIGNAL ;
    PORT
      LAYER M5 ;
        RECT  126.768 25.836 126.792 25.92 ;
    END
  END b_own_out[202]
  PIN b_own_out[203]
    DIRECTION OUTPUT ;
    USE SIGNAL ;
    PORT
      LAYER M3 ;
        RECT  127.008 25.882 127.026 25.92 ;
    END
  END b_own_out[203]
  PIN b_own_out[204]
    DIRECTION OUTPUT ;
    USE SIGNAL ;
    PORT
      LAYER M5 ;
        RECT  127.152 25.836 127.176 25.92 ;
    END
  END b_own_out[204]
  PIN b_own_out[205]
    DIRECTION OUTPUT ;
    USE SIGNAL ;
    PORT
      LAYER M3 ;
        RECT  127.368 25.882 127.386 25.92 ;
    END
  END b_own_out[205]
  PIN b_own_out[206]
    DIRECTION OUTPUT ;
    USE SIGNAL ;
    PORT
      LAYER M5 ;
        RECT  127.632 25.836 127.656 25.92 ;
    END
  END b_own_out[206]
  PIN b_own_out[207]
    DIRECTION OUTPUT ;
    USE SIGNAL ;
    PORT
      LAYER M3 ;
        RECT  127.764 25.882 127.782 25.92 ;
    END
  END b_own_out[207]
  PIN b_own_out[208]
    DIRECTION OUTPUT ;
    USE SIGNAL ;
    PORT
      LAYER M5 ;
        RECT  128.016 25.836 128.04 25.92 ;
    END
  END b_own_out[208]
  PIN b_own_out[209]
    DIRECTION OUTPUT ;
    USE SIGNAL ;
    PORT
      LAYER M3 ;
        RECT  128.232 25.882 128.25 25.92 ;
    END
  END b_own_out[209]
  PIN b_own_out[20]
    DIRECTION OUTPUT ;
    USE SIGNAL ;
    PORT
      LAYER M5 ;
        RECT  89.52 25.836 89.544 25.92 ;
    END
  END b_own_out[20]
  PIN b_own_out[210]
    DIRECTION OUTPUT ;
    USE SIGNAL ;
    PORT
      LAYER M5 ;
        RECT  128.4 25.836 128.424 25.92 ;
    END
  END b_own_out[210]
  PIN b_own_out[211]
    DIRECTION OUTPUT ;
    USE SIGNAL ;
    PORT
      LAYER M3 ;
        RECT  128.628 25.882 128.646 25.92 ;
    END
  END b_own_out[211]
  PIN b_own_out[212]
    DIRECTION OUTPUT ;
    USE SIGNAL ;
    PORT
      LAYER M5 ;
        RECT  128.784 25.836 128.808 25.92 ;
    END
  END b_own_out[212]
  PIN b_own_out[213]
    DIRECTION OUTPUT ;
    USE SIGNAL ;
    PORT
      LAYER M3 ;
        RECT  129.024 25.882 129.042 25.92 ;
    END
  END b_own_out[213]
  PIN b_own_out[214]
    DIRECTION OUTPUT ;
    USE SIGNAL ;
    PORT
      LAYER M5 ;
        RECT  129.264 25.836 129.288 25.92 ;
    END
  END b_own_out[214]
  PIN b_own_out[215]
    DIRECTION OUTPUT ;
    USE SIGNAL ;
    PORT
      LAYER M3 ;
        RECT  129.384 25.882 129.402 25.92 ;
    END
  END b_own_out[215]
  PIN b_own_out[216]
    DIRECTION OUTPUT ;
    USE SIGNAL ;
    PORT
      LAYER M5 ;
        RECT  129.648 25.836 129.672 25.92 ;
    END
  END b_own_out[216]
  PIN b_own_out[217]
    DIRECTION OUTPUT ;
    USE SIGNAL ;
    PORT
      LAYER M3 ;
        RECT  129.888 25.882 129.906 25.92 ;
    END
  END b_own_out[217]
  PIN b_own_out[218]
    DIRECTION OUTPUT ;
    USE SIGNAL ;
    PORT
      LAYER M5 ;
        RECT  130.032 25.836 130.056 25.92 ;
    END
  END b_own_out[218]
  PIN b_own_out[219]
    DIRECTION OUTPUT ;
    USE SIGNAL ;
    PORT
      LAYER M3 ;
        RECT  130.248 25.882 130.266 25.92 ;
    END
  END b_own_out[219]
  PIN b_own_out[21]
    DIRECTION OUTPUT ;
    USE SIGNAL ;
    PORT
      LAYER M3 ;
        RECT  89.748 25.882 89.766 25.92 ;
    END
  END b_own_out[21]
  PIN b_own_out[220]
    DIRECTION OUTPUT ;
    USE SIGNAL ;
    PORT
      LAYER M5 ;
        RECT  130.512 25.836 130.536 25.92 ;
    END
  END b_own_out[220]
  PIN b_own_out[221]
    DIRECTION OUTPUT ;
    USE SIGNAL ;
    PORT
      LAYER M3 ;
        RECT  130.644 25.882 130.662 25.92 ;
    END
  END b_own_out[221]
  PIN b_own_out[222]
    DIRECTION OUTPUT ;
    USE SIGNAL ;
    PORT
      LAYER M5 ;
        RECT  130.896 25.836 130.92 25.92 ;
    END
  END b_own_out[222]
  PIN b_own_out[223]
    DIRECTION OUTPUT ;
    USE SIGNAL ;
    PORT
      LAYER M3 ;
        RECT  131.112 25.882 131.13 25.92 ;
    END
  END b_own_out[223]
  PIN b_own_out[224]
    DIRECTION OUTPUT ;
    USE SIGNAL ;
    PORT
      LAYER M5 ;
        RECT  131.472 25.836 131.496 25.92 ;
    END
  END b_own_out[224]
  PIN b_own_out[225]
    DIRECTION OUTPUT ;
    USE SIGNAL ;
    PORT
      LAYER M3 ;
        RECT  131.904 25.882 131.922 25.92 ;
    END
  END b_own_out[225]
  PIN b_own_out[226]
    DIRECTION OUTPUT ;
    USE SIGNAL ;
    PORT
      LAYER M5 ;
        RECT  132.24 25.836 132.264 25.92 ;
    END
  END b_own_out[226]
  PIN b_own_out[227]
    DIRECTION OUTPUT ;
    USE SIGNAL ;
    PORT
      LAYER M3 ;
        RECT  132.552 25.882 132.57 25.92 ;
    END
  END b_own_out[227]
  PIN b_own_out[228]
    DIRECTION OUTPUT ;
    USE SIGNAL ;
    PORT
      LAYER M5 ;
        RECT  133.008 25.836 133.032 25.92 ;
    END
  END b_own_out[228]
  PIN b_own_out[229]
    DIRECTION OUTPUT ;
    USE SIGNAL ;
    PORT
      LAYER M3 ;
        RECT  133.344 25.882 133.362 25.92 ;
    END
  END b_own_out[229]
  PIN b_own_out[22]
    DIRECTION OUTPUT ;
    USE SIGNAL ;
    PORT
      LAYER M5 ;
        RECT  89.904 25.836 89.928 25.92 ;
    END
  END b_own_out[22]
  PIN b_own_out[230]
    DIRECTION OUTPUT ;
    USE SIGNAL ;
    PORT
      LAYER M5 ;
        RECT  133.68 25.836 133.704 25.92 ;
    END
  END b_own_out[230]
  PIN b_own_out[231]
    DIRECTION OUTPUT ;
    USE SIGNAL ;
    PORT
      LAYER M3 ;
        RECT  134.1 25.882 134.118 25.92 ;
    END
  END b_own_out[231]
  PIN b_own_out[232]
    DIRECTION OUTPUT ;
    USE SIGNAL ;
    PORT
      LAYER M5 ;
        RECT  134.448 25.836 134.472 25.92 ;
    END
  END b_own_out[232]
  PIN b_own_out[233]
    DIRECTION OUTPUT ;
    USE SIGNAL ;
    PORT
      LAYER M3 ;
        RECT  134.856 25.882 134.874 25.92 ;
    END
  END b_own_out[233]
  PIN b_own_out[234]
    DIRECTION OUTPUT ;
    USE SIGNAL ;
    PORT
      LAYER M5 ;
        RECT  135.216 25.836 135.24 25.92 ;
    END
  END b_own_out[234]
  PIN b_own_out[235]
    DIRECTION OUTPUT ;
    USE SIGNAL ;
    PORT
      LAYER M3 ;
        RECT  135.54 25.882 135.558 25.92 ;
    END
  END b_own_out[235]
  PIN b_own_out[236]
    DIRECTION OUTPUT ;
    USE SIGNAL ;
    PORT
      LAYER M5 ;
        RECT  135.984 25.836 136.008 25.92 ;
    END
  END b_own_out[236]
  PIN b_own_out[237]
    DIRECTION OUTPUT ;
    USE SIGNAL ;
    PORT
      LAYER M3 ;
        RECT  136.296 25.882 136.314 25.92 ;
    END
  END b_own_out[237]
  PIN b_own_out[238]
    DIRECTION OUTPUT ;
    USE SIGNAL ;
    PORT
      LAYER M5 ;
        RECT  136.656 25.836 136.68 25.92 ;
    END
  END b_own_out[238]
  PIN b_own_out[239]
    DIRECTION OUTPUT ;
    USE SIGNAL ;
    PORT
      LAYER M3 ;
        RECT  137.088 25.882 137.106 25.92 ;
    END
  END b_own_out[239]
  PIN b_own_out[23]
    DIRECTION OUTPUT ;
    USE SIGNAL ;
    PORT
      LAYER M3 ;
        RECT  90.144 25.882 90.162 25.92 ;
    END
  END b_own_out[23]
  PIN b_own_out[240]
    DIRECTION OUTPUT ;
    USE SIGNAL ;
    PORT
      LAYER M5 ;
        RECT  137.424 25.836 137.448 25.92 ;
    END
  END b_own_out[240]
  PIN b_own_out[241]
    DIRECTION OUTPUT ;
    USE SIGNAL ;
    PORT
      LAYER M3 ;
        RECT  137.844 25.882 137.862 25.92 ;
    END
  END b_own_out[241]
  PIN b_own_out[242]
    DIRECTION OUTPUT ;
    USE SIGNAL ;
    PORT
      LAYER M5 ;
        RECT  138.192 25.836 138.216 25.92 ;
    END
  END b_own_out[242]
  PIN b_own_out[243]
    DIRECTION OUTPUT ;
    USE SIGNAL ;
    PORT
      LAYER M3 ;
        RECT  138.528 25.882 138.546 25.92 ;
    END
  END b_own_out[243]
  PIN b_own_out[244]
    DIRECTION OUTPUT ;
    USE SIGNAL ;
    PORT
      LAYER M5 ;
        RECT  138.96 25.836 138.984 25.92 ;
    END
  END b_own_out[244]
  PIN b_own_out[245]
    DIRECTION OUTPUT ;
    USE SIGNAL ;
    PORT
      LAYER M3 ;
        RECT  139.284 25.882 139.302 25.92 ;
    END
  END b_own_out[245]
  PIN b_own_out[246]
    DIRECTION OUTPUT ;
    USE SIGNAL ;
    PORT
      LAYER M5 ;
        RECT  139.632 25.836 139.656 25.92 ;
    END
  END b_own_out[246]
  PIN b_own_out[247]
    DIRECTION OUTPUT ;
    USE SIGNAL ;
    PORT
      LAYER M3 ;
        RECT  140.04 25.882 140.058 25.92 ;
    END
  END b_own_out[247]
  PIN b_own_out[248]
    DIRECTION OUTPUT ;
    USE SIGNAL ;
    PORT
      LAYER M5 ;
        RECT  140.4 25.836 140.424 25.92 ;
    END
  END b_own_out[248]
  PIN b_own_out[249]
    DIRECTION OUTPUT ;
    USE SIGNAL ;
    PORT
      LAYER M3 ;
        RECT  140.832 25.882 140.85 25.92 ;
    END
  END b_own_out[249]
  PIN b_own_out[24]
    DIRECTION OUTPUT ;
    USE SIGNAL ;
    PORT
      LAYER M5 ;
        RECT  90.384 25.836 90.408 25.92 ;
    END
  END b_own_out[24]
  PIN b_own_out[250]
    DIRECTION OUTPUT ;
    USE SIGNAL ;
    PORT
      LAYER M5 ;
        RECT  141.168 25.836 141.192 25.92 ;
    END
  END b_own_out[250]
  PIN b_own_out[251]
    DIRECTION OUTPUT ;
    USE SIGNAL ;
    PORT
      LAYER M3 ;
        RECT  141.48 25.882 141.498 25.92 ;
    END
  END b_own_out[251]
  PIN b_own_out[252]
    DIRECTION OUTPUT ;
    USE SIGNAL ;
    PORT
      LAYER M5 ;
        RECT  141.936 25.836 141.96 25.92 ;
    END
  END b_own_out[252]
  PIN b_own_out[253]
    DIRECTION OUTPUT ;
    USE SIGNAL ;
    PORT
      LAYER M3 ;
        RECT  142.272 25.882 142.29 25.92 ;
    END
  END b_own_out[253]
  PIN b_own_out[254]
    DIRECTION OUTPUT ;
    USE SIGNAL ;
    PORT
      LAYER M5 ;
        RECT  142.704 25.836 142.728 25.92 ;
    END
  END b_own_out[254]
  PIN b_own_out[255]
    DIRECTION OUTPUT ;
    USE SIGNAL ;
    PORT
      LAYER M3 ;
        RECT  143.028 25.882 143.046 25.92 ;
    END
  END b_own_out[255]
  PIN b_own_out[25]
    DIRECTION OUTPUT ;
    USE SIGNAL ;
    PORT
      LAYER M3 ;
        RECT  90.504 25.882 90.522 25.92 ;
    END
  END b_own_out[25]
  PIN b_own_out[26]
    DIRECTION OUTPUT ;
    USE SIGNAL ;
    PORT
      LAYER M5 ;
        RECT  90.768 25.836 90.792 25.92 ;
    END
  END b_own_out[26]
  PIN b_own_out[27]
    DIRECTION OUTPUT ;
    USE SIGNAL ;
    PORT
      LAYER M3 ;
        RECT  90.9 25.882 90.918 25.92 ;
    END
  END b_own_out[27]
  PIN b_own_out[28]
    DIRECTION OUTPUT ;
    USE SIGNAL ;
    PORT
      LAYER M5 ;
        RECT  91.152 25.836 91.176 25.92 ;
    END
  END b_own_out[28]
  PIN b_own_out[29]
    DIRECTION OUTPUT ;
    USE SIGNAL ;
    PORT
      LAYER M3 ;
        RECT  91.368 25.882 91.386 25.92 ;
    END
  END b_own_out[29]
  PIN b_own_out[2]
    DIRECTION OUTPUT ;
    USE SIGNAL ;
    PORT
      LAYER M5 ;
        RECT  85.872 25.836 85.896 25.92 ;
    END
  END b_own_out[2]
  PIN b_own_out[30]
    DIRECTION OUTPUT ;
    USE SIGNAL ;
    PORT
      LAYER M5 ;
        RECT  91.536 25.836 91.56 25.92 ;
    END
  END b_own_out[30]
  PIN b_own_out[31]
    DIRECTION OUTPUT ;
    USE SIGNAL ;
    PORT
      LAYER M3 ;
        RECT  91.764 25.882 91.782 25.92 ;
    END
  END b_own_out[31]
  PIN b_own_out[32]
    DIRECTION OUTPUT ;
    USE SIGNAL ;
    PORT
      LAYER M5 ;
        RECT  92.016 25.836 92.04 25.92 ;
    END
  END b_own_out[32]
  PIN b_own_out[33]
    DIRECTION OUTPUT ;
    USE SIGNAL ;
    PORT
      LAYER M3 ;
        RECT  92.16 25.882 92.178 25.92 ;
    END
  END b_own_out[33]
  PIN b_own_out[34]
    DIRECTION OUTPUT ;
    USE SIGNAL ;
    PORT
      LAYER M5 ;
        RECT  92.4 25.836 92.424 25.92 ;
    END
  END b_own_out[34]
  PIN b_own_out[35]
    DIRECTION OUTPUT ;
    USE SIGNAL ;
    PORT
      LAYER M3 ;
        RECT  92.52 25.882 92.538 25.92 ;
    END
  END b_own_out[35]
  PIN b_own_out[36]
    DIRECTION OUTPUT ;
    USE SIGNAL ;
    PORT
      LAYER M5 ;
        RECT  92.784 25.836 92.808 25.92 ;
    END
  END b_own_out[36]
  PIN b_own_out[37]
    DIRECTION OUTPUT ;
    USE SIGNAL ;
    PORT
      LAYER M3 ;
        RECT  93.024 25.882 93.042 25.92 ;
    END
  END b_own_out[37]
  PIN b_own_out[38]
    DIRECTION OUTPUT ;
    USE SIGNAL ;
    PORT
      LAYER M5 ;
        RECT  93.168 25.836 93.192 25.92 ;
    END
  END b_own_out[38]
  PIN b_own_out[39]
    DIRECTION OUTPUT ;
    USE SIGNAL ;
    PORT
      LAYER M3 ;
        RECT  93.384 25.882 93.402 25.92 ;
    END
  END b_own_out[39]
  PIN b_own_out[3]
    DIRECTION OUTPUT ;
    USE SIGNAL ;
    PORT
      LAYER M3 ;
        RECT  86.004 25.882 86.022 25.92 ;
    END
  END b_own_out[3]
  PIN b_own_out[40]
    DIRECTION OUTPUT ;
    USE SIGNAL ;
    PORT
      LAYER M5 ;
        RECT  93.648 25.836 93.672 25.92 ;
    END
  END b_own_out[40]
  PIN b_own_out[41]
    DIRECTION OUTPUT ;
    USE SIGNAL ;
    PORT
      LAYER M3 ;
        RECT  93.78 25.882 93.798 25.92 ;
    END
  END b_own_out[41]
  PIN b_own_out[42]
    DIRECTION OUTPUT ;
    USE SIGNAL ;
    PORT
      LAYER M5 ;
        RECT  94.032 25.836 94.056 25.92 ;
    END
  END b_own_out[42]
  PIN b_own_out[43]
    DIRECTION OUTPUT ;
    USE SIGNAL ;
    PORT
      LAYER M3 ;
        RECT  94.248 25.882 94.266 25.92 ;
    END
  END b_own_out[43]
  PIN b_own_out[44]
    DIRECTION OUTPUT ;
    USE SIGNAL ;
    PORT
      LAYER M5 ;
        RECT  94.416 25.836 94.44 25.92 ;
    END
  END b_own_out[44]
  PIN b_own_out[45]
    DIRECTION OUTPUT ;
    USE SIGNAL ;
    PORT
      LAYER M3 ;
        RECT  94.644 25.882 94.662 25.92 ;
    END
  END b_own_out[45]
  PIN b_own_out[46]
    DIRECTION OUTPUT ;
    USE SIGNAL ;
    PORT
      LAYER M5 ;
        RECT  94.8 25.836 94.824 25.92 ;
    END
  END b_own_out[46]
  PIN b_own_out[47]
    DIRECTION OUTPUT ;
    USE SIGNAL ;
    PORT
      LAYER M3 ;
        RECT  95.04 25.882 95.058 25.92 ;
    END
  END b_own_out[47]
  PIN b_own_out[48]
    DIRECTION OUTPUT ;
    USE SIGNAL ;
    PORT
      LAYER M5 ;
        RECT  95.28 25.836 95.304 25.92 ;
    END
  END b_own_out[48]
  PIN b_own_out[49]
    DIRECTION OUTPUT ;
    USE SIGNAL ;
    PORT
      LAYER M3 ;
        RECT  95.4 25.882 95.418 25.92 ;
    END
  END b_own_out[49]
  PIN b_own_out[4]
    DIRECTION OUTPUT ;
    USE SIGNAL ;
    PORT
      LAYER M5 ;
        RECT  86.256 25.836 86.28 25.92 ;
    END
  END b_own_out[4]
  PIN b_own_out[50]
    DIRECTION OUTPUT ;
    USE SIGNAL ;
    PORT
      LAYER M5 ;
        RECT  95.664 25.836 95.688 25.92 ;
    END
  END b_own_out[50]
  PIN b_own_out[51]
    DIRECTION OUTPUT ;
    USE SIGNAL ;
    PORT
      LAYER M3 ;
        RECT  95.904 25.882 95.922 25.92 ;
    END
  END b_own_out[51]
  PIN b_own_out[52]
    DIRECTION OUTPUT ;
    USE SIGNAL ;
    PORT
      LAYER M5 ;
        RECT  96.048 25.836 96.072 25.92 ;
    END
  END b_own_out[52]
  PIN b_own_out[53]
    DIRECTION OUTPUT ;
    USE SIGNAL ;
    PORT
      LAYER M3 ;
        RECT  96.264 25.882 96.282 25.92 ;
    END
  END b_own_out[53]
  PIN b_own_out[54]
    DIRECTION OUTPUT ;
    USE SIGNAL ;
    PORT
      LAYER M5 ;
        RECT  96.528 25.836 96.552 25.92 ;
    END
  END b_own_out[54]
  PIN b_own_out[55]
    DIRECTION OUTPUT ;
    USE SIGNAL ;
    PORT
      LAYER M3 ;
        RECT  96.66 25.882 96.678 25.92 ;
    END
  END b_own_out[55]
  PIN b_own_out[56]
    DIRECTION OUTPUT ;
    USE SIGNAL ;
    PORT
      LAYER M5 ;
        RECT  96.912 25.836 96.936 25.92 ;
    END
  END b_own_out[56]
  PIN b_own_out[57]
    DIRECTION OUTPUT ;
    USE SIGNAL ;
    PORT
      LAYER M3 ;
        RECT  97.056 25.882 97.074 25.92 ;
    END
  END b_own_out[57]
  PIN b_own_out[58]
    DIRECTION OUTPUT ;
    USE SIGNAL ;
    PORT
      LAYER M5 ;
        RECT  97.296 25.836 97.32 25.92 ;
    END
  END b_own_out[58]
  PIN b_own_out[59]
    DIRECTION OUTPUT ;
    USE SIGNAL ;
    PORT
      LAYER M3 ;
        RECT  97.524 25.882 97.542 25.92 ;
    END
  END b_own_out[59]
  PIN b_own_out[5]
    DIRECTION OUTPUT ;
    USE SIGNAL ;
    PORT
      LAYER M3 ;
        RECT  86.472 25.882 86.49 25.92 ;
    END
  END b_own_out[5]
  PIN b_own_out[60]
    DIRECTION OUTPUT ;
    USE SIGNAL ;
    PORT
      LAYER M5 ;
        RECT  97.68 25.836 97.704 25.92 ;
    END
  END b_own_out[60]
  PIN b_own_out[61]
    DIRECTION OUTPUT ;
    USE SIGNAL ;
    PORT
      LAYER M3 ;
        RECT  97.92 25.882 97.938 25.92 ;
    END
  END b_own_out[61]
  PIN b_own_out[62]
    DIRECTION OUTPUT ;
    USE SIGNAL ;
    PORT
      LAYER M5 ;
        RECT  98.16 25.836 98.184 25.92 ;
    END
  END b_own_out[62]
  PIN b_own_out[63]
    DIRECTION OUTPUT ;
    USE SIGNAL ;
    PORT
      LAYER M3 ;
        RECT  98.28 25.882 98.298 25.92 ;
    END
  END b_own_out[63]
  PIN b_own_out[64]
    DIRECTION OUTPUT ;
    USE SIGNAL ;
    PORT
      LAYER M5 ;
        RECT  98.544 25.836 98.568 25.92 ;
    END
  END b_own_out[64]
  PIN b_own_out[65]
    DIRECTION OUTPUT ;
    USE SIGNAL ;
    PORT
      LAYER M3 ;
        RECT  98.676 25.882 98.694 25.92 ;
    END
  END b_own_out[65]
  PIN b_own_out[66]
    DIRECTION OUTPUT ;
    USE SIGNAL ;
    PORT
      LAYER M5 ;
        RECT  98.928 25.836 98.952 25.92 ;
    END
  END b_own_out[66]
  PIN b_own_out[67]
    DIRECTION OUTPUT ;
    USE SIGNAL ;
    PORT
      LAYER M3 ;
        RECT  99.144 25.882 99.162 25.92 ;
    END
  END b_own_out[67]
  PIN b_own_out[68]
    DIRECTION OUTPUT ;
    USE SIGNAL ;
    PORT
      LAYER M5 ;
        RECT  99.312 25.836 99.336 25.92 ;
    END
  END b_own_out[68]
  PIN b_own_out[69]
    DIRECTION OUTPUT ;
    USE SIGNAL ;
    PORT
      LAYER M3 ;
        RECT  99.54 25.882 99.558 25.92 ;
    END
  END b_own_out[69]
  PIN b_own_out[6]
    DIRECTION OUTPUT ;
    USE SIGNAL ;
    PORT
      LAYER M5 ;
        RECT  86.64 25.836 86.664 25.92 ;
    END
  END b_own_out[6]
  PIN b_own_out[70]
    DIRECTION OUTPUT ;
    USE SIGNAL ;
    PORT
      LAYER M5 ;
        RECT  99.792 25.836 99.816 25.92 ;
    END
  END b_own_out[70]
  PIN b_own_out[71]
    DIRECTION OUTPUT ;
    USE SIGNAL ;
    PORT
      LAYER M3 ;
        RECT  99.936 25.882 99.954 25.92 ;
    END
  END b_own_out[71]
  PIN b_own_out[72]
    DIRECTION OUTPUT ;
    USE SIGNAL ;
    PORT
      LAYER M5 ;
        RECT  100.176 25.836 100.2 25.92 ;
    END
  END b_own_out[72]
  PIN b_own_out[73]
    DIRECTION OUTPUT ;
    USE SIGNAL ;
    PORT
      LAYER M3 ;
        RECT  100.404 25.882 100.422 25.92 ;
    END
  END b_own_out[73]
  PIN b_own_out[74]
    DIRECTION OUTPUT ;
    USE SIGNAL ;
    PORT
      LAYER M5 ;
        RECT  100.56 25.836 100.584 25.92 ;
    END
  END b_own_out[74]
  PIN b_own_out[75]
    DIRECTION OUTPUT ;
    USE SIGNAL ;
    PORT
      LAYER M3 ;
        RECT  100.8 25.882 100.818 25.92 ;
    END
  END b_own_out[75]
  PIN b_own_out[76]
    DIRECTION OUTPUT ;
    USE SIGNAL ;
    PORT
      LAYER M5 ;
        RECT  100.944 25.836 100.968 25.92 ;
    END
  END b_own_out[76]
  PIN b_own_out[77]
    DIRECTION OUTPUT ;
    USE SIGNAL ;
    PORT
      LAYER M3 ;
        RECT  101.16 25.882 101.178 25.92 ;
    END
  END b_own_out[77]
  PIN b_own_out[78]
    DIRECTION OUTPUT ;
    USE SIGNAL ;
    PORT
      LAYER M5 ;
        RECT  101.424 25.836 101.448 25.92 ;
    END
  END b_own_out[78]
  PIN b_own_out[79]
    DIRECTION OUTPUT ;
    USE SIGNAL ;
    PORT
      LAYER M3 ;
        RECT  101.556 25.882 101.574 25.92 ;
    END
  END b_own_out[79]
  PIN b_own_out[7]
    DIRECTION OUTPUT ;
    USE SIGNAL ;
    PORT
      LAYER M3 ;
        RECT  86.868 25.882 86.886 25.92 ;
    END
  END b_own_out[7]
  PIN b_own_out[80]
    DIRECTION OUTPUT ;
    USE SIGNAL ;
    PORT
      LAYER M5 ;
        RECT  101.808 25.836 101.832 25.92 ;
    END
  END b_own_out[80]
  PIN b_own_out[81]
    DIRECTION OUTPUT ;
    USE SIGNAL ;
    PORT
      LAYER M3 ;
        RECT  102.024 25.882 102.042 25.92 ;
    END
  END b_own_out[81]
  PIN b_own_out[82]
    DIRECTION OUTPUT ;
    USE SIGNAL ;
    PORT
      LAYER M5 ;
        RECT  102.192 25.836 102.216 25.92 ;
    END
  END b_own_out[82]
  PIN b_own_out[83]
    DIRECTION OUTPUT ;
    USE SIGNAL ;
    PORT
      LAYER M3 ;
        RECT  102.42 25.882 102.438 25.92 ;
    END
  END b_own_out[83]
  PIN b_own_out[84]
    DIRECTION OUTPUT ;
    USE SIGNAL ;
    PORT
      LAYER M5 ;
        RECT  102.576 25.836 102.6 25.92 ;
    END
  END b_own_out[84]
  PIN b_own_out[85]
    DIRECTION OUTPUT ;
    USE SIGNAL ;
    PORT
      LAYER M3 ;
        RECT  102.816 25.882 102.834 25.92 ;
    END
  END b_own_out[85]
  PIN b_own_out[86]
    DIRECTION OUTPUT ;
    USE SIGNAL ;
    PORT
      LAYER M5 ;
        RECT  103.056 25.836 103.08 25.92 ;
    END
  END b_own_out[86]
  PIN b_own_out[87]
    DIRECTION OUTPUT ;
    USE SIGNAL ;
    PORT
      LAYER M3 ;
        RECT  103.176 25.882 103.194 25.92 ;
    END
  END b_own_out[87]
  PIN b_own_out[88]
    DIRECTION OUTPUT ;
    USE SIGNAL ;
    PORT
      LAYER M5 ;
        RECT  103.44 25.836 103.464 25.92 ;
    END
  END b_own_out[88]
  PIN b_own_out[89]
    DIRECTION OUTPUT ;
    USE SIGNAL ;
    PORT
      LAYER M3 ;
        RECT  103.68 25.882 103.698 25.92 ;
    END
  END b_own_out[89]
  PIN b_own_out[8]
    DIRECTION OUTPUT ;
    USE SIGNAL ;
    PORT
      LAYER M5 ;
        RECT  87.024 25.836 87.048 25.92 ;
    END
  END b_own_out[8]
  PIN b_own_out[90]
    DIRECTION OUTPUT ;
    USE SIGNAL ;
    PORT
      LAYER M5 ;
        RECT  103.824 25.836 103.848 25.92 ;
    END
  END b_own_out[90]
  PIN b_own_out[91]
    DIRECTION OUTPUT ;
    USE SIGNAL ;
    PORT
      LAYER M3 ;
        RECT  104.04 25.882 104.058 25.92 ;
    END
  END b_own_out[91]
  PIN b_own_out[92]
    DIRECTION OUTPUT ;
    USE SIGNAL ;
    PORT
      LAYER M5 ;
        RECT  104.304 25.836 104.328 25.92 ;
    END
  END b_own_out[92]
  PIN b_own_out[93]
    DIRECTION OUTPUT ;
    USE SIGNAL ;
    PORT
      LAYER M3 ;
        RECT  104.436 25.882 104.454 25.92 ;
    END
  END b_own_out[93]
  PIN b_own_out[94]
    DIRECTION OUTPUT ;
    USE SIGNAL ;
    PORT
      LAYER M5 ;
        RECT  104.688 25.836 104.712 25.92 ;
    END
  END b_own_out[94]
  PIN b_own_out[95]
    DIRECTION OUTPUT ;
    USE SIGNAL ;
    PORT
      LAYER M3 ;
        RECT  104.832 25.882 104.85 25.92 ;
    END
  END b_own_out[95]
  PIN b_own_out[96]
    DIRECTION OUTPUT ;
    USE SIGNAL ;
    PORT
      LAYER M5 ;
        RECT  105.072 25.836 105.096 25.92 ;
    END
  END b_own_out[96]
  PIN b_own_out[97]
    DIRECTION OUTPUT ;
    USE SIGNAL ;
    PORT
      LAYER M3 ;
        RECT  105.3 25.882 105.318 25.92 ;
    END
  END b_own_out[97]
  PIN b_own_out[98]
    DIRECTION OUTPUT ;
    USE SIGNAL ;
    PORT
      LAYER M5 ;
        RECT  105.456 25.836 105.48 25.92 ;
    END
  END b_own_out[98]
  PIN b_own_out[99]
    DIRECTION OUTPUT ;
    USE SIGNAL ;
    PORT
      LAYER M3 ;
        RECT  105.696 25.882 105.714 25.92 ;
    END
  END b_own_out[99]
  PIN b_own_out[9]
    DIRECTION OUTPUT ;
    USE SIGNAL ;
    PORT
      LAYER M3 ;
        RECT  87.264 25.882 87.282 25.92 ;
    END
  END b_own_out[9]
  PIN clk
    DIRECTION INPUT ;
    USE SIGNAL ;
    PORT
      LAYER M4 ;
        RECT  0 13.008 0.084 13.032 ;
    END
  END clk
  PIN flg_fault[0]
    DIRECTION INPUT ;
    USE SIGNAL ;
    PORT
      LAYER M5 ;
        RECT  1.104 0 1.128 0.084 ;
    END
  END flg_fault[0]
  PIN flg_fault[1]
    DIRECTION INPUT ;
    USE SIGNAL ;
    PORT
      LAYER M3 ;
        RECT  1.152 0 1.17 0.038 ;
    END
  END flg_fault[1]
  PIN flg_fault[2]
    DIRECTION INPUT ;
    USE SIGNAL ;
    PORT
      LAYER M5 ;
        RECT  1.2 0 1.224 0.084 ;
    END
  END flg_fault[2]
  PIN flg_fault[3]
    DIRECTION INPUT ;
    USE SIGNAL ;
    PORT
      LAYER M3 ;
        RECT  1.224 0 1.242 0.038 ;
    END
  END flg_fault[3]
  PIN flg_hnz[0]
    DIRECTION INPUT ;
    USE SIGNAL ;
    PORT
      LAYER M5 ;
        RECT  1.296 0 1.32 0.084 ;
    END
  END flg_hnz[0]
  PIN flg_hnz[1]
    DIRECTION INPUT ;
    USE SIGNAL ;
    PORT
      LAYER M3 ;
        RECT  1.332 0 1.35 0.038 ;
    END
  END flg_hnz[1]
  PIN flg_hnz[2]
    DIRECTION INPUT ;
    USE SIGNAL ;
    PORT
      LAYER M5 ;
        RECT  1.392 0 1.416 0.084 ;
    END
  END flg_hnz[2]
  PIN flg_hnz[3]
    DIRECTION INPUT ;
    USE SIGNAL ;
    PORT
      LAYER M3 ;
        RECT  1.44 0 1.458 0.038 ;
    END
  END flg_hnz[3]
  PIN hdr_c[0]
    DIRECTION INPUT ;
    USE SIGNAL ;
    PORT
      LAYER M5 ;
        RECT  1.872 0 1.896 0.084 ;
    END
  END hdr_c[0]
  PIN hdr_c[100]
    DIRECTION INPUT ;
    USE SIGNAL ;
    PORT
      LAYER M5 ;
        RECT  12.144 0 12.168 0.084 ;
    END
  END hdr_c[100]
  PIN hdr_c[101]
    DIRECTION INPUT ;
    USE SIGNAL ;
    PORT
      LAYER M3 ;
        RECT  12.276 0 12.294 0.038 ;
    END
  END hdr_c[101]
  PIN hdr_c[102]
    DIRECTION INPUT ;
    USE SIGNAL ;
    PORT
      LAYER M5 ;
        RECT  12.336 0 12.36 0.084 ;
    END
  END hdr_c[102]
  PIN hdr_c[103]
    DIRECTION INPUT ;
    USE SIGNAL ;
    PORT
      LAYER M3 ;
        RECT  12.456 0 12.474 0.038 ;
    END
  END hdr_c[103]
  PIN hdr_c[104]
    DIRECTION INPUT ;
    USE SIGNAL ;
    PORT
      LAYER M5 ;
        RECT  12.528 0 12.552 0.084 ;
    END
  END hdr_c[104]
  PIN hdr_c[105]
    DIRECTION INPUT ;
    USE SIGNAL ;
    PORT
      LAYER M3 ;
        RECT  12.672 0 12.69 0.038 ;
    END
  END hdr_c[105]
  PIN hdr_c[106]
    DIRECTION INPUT ;
    USE SIGNAL ;
    PORT
      LAYER M5 ;
        RECT  12.72 0 12.744 0.084 ;
    END
  END hdr_c[106]
  PIN hdr_c[107]
    DIRECTION INPUT ;
    USE SIGNAL ;
    PORT
      LAYER M3 ;
        RECT  12.852 0 12.87 0.038 ;
    END
  END hdr_c[107]
  PIN hdr_c[10]
    DIRECTION INPUT ;
    USE SIGNAL ;
    PORT
      LAYER M5 ;
        RECT  2.928 0 2.952 0.084 ;
    END
  END hdr_c[10]
  PIN hdr_c[11]
    DIRECTION INPUT ;
    USE SIGNAL ;
    PORT
      LAYER M3 ;
        RECT  3.06 0 3.078 0.038 ;
    END
  END hdr_c[11]
  PIN hdr_c[12]
    DIRECTION INPUT ;
    USE SIGNAL ;
    PORT
      LAYER M5 ;
        RECT  3.12 0 3.144 0.084 ;
    END
  END hdr_c[12]
  PIN hdr_c[13]
    DIRECTION INPUT ;
    USE SIGNAL ;
    PORT
      LAYER M3 ;
        RECT  3.24 0 3.258 0.038 ;
    END
  END hdr_c[13]
  PIN hdr_c[14]
    DIRECTION INPUT ;
    USE SIGNAL ;
    PORT
      LAYER M5 ;
        RECT  3.312 0 3.336 0.084 ;
    END
  END hdr_c[14]
  PIN hdr_c[15]
    DIRECTION INPUT ;
    USE SIGNAL ;
    PORT
      LAYER M3 ;
        RECT  3.456 0 3.474 0.038 ;
    END
  END hdr_c[15]
  PIN hdr_c[16]
    DIRECTION INPUT ;
    USE SIGNAL ;
    PORT
      LAYER M5 ;
        RECT  3.504 0 3.528 0.084 ;
    END
  END hdr_c[16]
  PIN hdr_c[17]
    DIRECTION INPUT ;
    USE SIGNAL ;
    PORT
      LAYER M3 ;
        RECT  3.636 0 3.654 0.038 ;
    END
  END hdr_c[17]
  PIN hdr_c[18]
    DIRECTION INPUT ;
    USE SIGNAL ;
    PORT
      LAYER M5 ;
        RECT  3.792 0 3.816 0.084 ;
    END
  END hdr_c[18]
  PIN hdr_c[19]
    DIRECTION INPUT ;
    USE SIGNAL ;
    PORT
      LAYER M3 ;
        RECT  3.816 0 3.834 0.038 ;
    END
  END hdr_c[19]
  PIN hdr_c[1]
    DIRECTION INPUT ;
    USE SIGNAL ;
    PORT
      LAYER M3 ;
        RECT  2.016 0 2.034 0.038 ;
    END
  END hdr_c[1]
  PIN hdr_c[20]
    DIRECTION INPUT ;
    USE SIGNAL ;
    PORT
      LAYER M5 ;
        RECT  3.984 0 4.008 0.084 ;
    END
  END hdr_c[20]
  PIN hdr_c[21]
    DIRECTION INPUT ;
    USE SIGNAL ;
    PORT
      LAYER M3 ;
        RECT  4.032 0 4.05 0.038 ;
    END
  END hdr_c[21]
  PIN hdr_c[22]
    DIRECTION INPUT ;
    USE SIGNAL ;
    PORT
      LAYER M5 ;
        RECT  4.176 0 4.2 0.084 ;
    END
  END hdr_c[22]
  PIN hdr_c[23]
    DIRECTION INPUT ;
    USE SIGNAL ;
    PORT
      LAYER M3 ;
        RECT  4.212 0 4.23 0.038 ;
    END
  END hdr_c[23]
  PIN hdr_c[24]
    DIRECTION INPUT ;
    USE SIGNAL ;
    PORT
      LAYER M5 ;
        RECT  4.368 0 4.392 0.084 ;
    END
  END hdr_c[24]
  PIN hdr_c[25]
    DIRECTION INPUT ;
    USE SIGNAL ;
    PORT
      LAYER M3 ;
        RECT  4.5 0 4.518 0.038 ;
    END
  END hdr_c[25]
  PIN hdr_c[26]
    DIRECTION INPUT ;
    USE SIGNAL ;
    PORT
      LAYER M5 ;
        RECT  4.56 0 4.584 0.084 ;
    END
  END hdr_c[26]
  PIN hdr_c[27]
    DIRECTION INPUT ;
    USE SIGNAL ;
    PORT
      LAYER M3 ;
        RECT  4.68 0 4.698 0.038 ;
    END
  END hdr_c[27]
  PIN hdr_c[28]
    DIRECTION INPUT ;
    USE SIGNAL ;
    PORT
      LAYER M5 ;
        RECT  4.752 0 4.776 0.084 ;
    END
  END hdr_c[28]
  PIN hdr_c[29]
    DIRECTION INPUT ;
    USE SIGNAL ;
    PORT
      LAYER M3 ;
        RECT  4.896 0 4.914 0.038 ;
    END
  END hdr_c[29]
  PIN hdr_c[2]
    DIRECTION INPUT ;
    USE SIGNAL ;
    PORT
      LAYER M5 ;
        RECT  2.064 0 2.088 0.084 ;
    END
  END hdr_c[2]
  PIN hdr_c[30]
    DIRECTION INPUT ;
    USE SIGNAL ;
    PORT
      LAYER M5 ;
        RECT  4.944 0 4.968 0.084 ;
    END
  END hdr_c[30]
  PIN hdr_c[31]
    DIRECTION INPUT ;
    USE SIGNAL ;
    PORT
      LAYER M3 ;
        RECT  5.076 0 5.094 0.038 ;
    END
  END hdr_c[31]
  PIN hdr_c[32]
    DIRECTION INPUT ;
    USE SIGNAL ;
    PORT
      LAYER M5 ;
        RECT  5.136 0 5.16 0.084 ;
    END
  END hdr_c[32]
  PIN hdr_c[33]
    DIRECTION INPUT ;
    USE SIGNAL ;
    PORT
      LAYER M3 ;
        RECT  5.256 0 5.274 0.038 ;
    END
  END hdr_c[33]
  PIN hdr_c[34]
    DIRECTION INPUT ;
    USE SIGNAL ;
    PORT
      LAYER M5 ;
        RECT  5.424 0 5.448 0.084 ;
    END
  END hdr_c[34]
  PIN hdr_c[35]
    DIRECTION INPUT ;
    USE SIGNAL ;
    PORT
      LAYER M3 ;
        RECT  5.472 0 5.49 0.038 ;
    END
  END hdr_c[35]
  PIN hdr_c[36]
    DIRECTION INPUT ;
    USE SIGNAL ;
    PORT
      LAYER M5 ;
        RECT  5.616 0 5.64 0.084 ;
    END
  END hdr_c[36]
  PIN hdr_c[37]
    DIRECTION INPUT ;
    USE SIGNAL ;
    PORT
      LAYER M3 ;
        RECT  5.652 0 5.67 0.038 ;
    END
  END hdr_c[37]
  PIN hdr_c[38]
    DIRECTION INPUT ;
    USE SIGNAL ;
    PORT
      LAYER M5 ;
        RECT  5.808 0 5.832 0.084 ;
    END
  END hdr_c[38]
  PIN hdr_c[39]
    DIRECTION INPUT ;
    USE SIGNAL ;
    PORT
      LAYER M3 ;
        RECT  5.832 0 5.85 0.038 ;
    END
  END hdr_c[39]
  PIN hdr_c[3]
    DIRECTION INPUT ;
    USE SIGNAL ;
    PORT
      LAYER M3 ;
        RECT  2.196 0 2.214 0.038 ;
    END
  END hdr_c[3]
  PIN hdr_c[40]
    DIRECTION INPUT ;
    USE SIGNAL ;
    PORT
      LAYER M5 ;
        RECT  6 0 6.024 0.084 ;
    END
  END hdr_c[40]
  PIN hdr_c[41]
    DIRECTION INPUT ;
    USE SIGNAL ;
    PORT
      LAYER M3 ;
        RECT  6.12 0 6.138 0.038 ;
    END
  END hdr_c[41]
  PIN hdr_c[42]
    DIRECTION INPUT ;
    USE SIGNAL ;
    PORT
      LAYER M5 ;
        RECT  6.192 0 6.216 0.084 ;
    END
  END hdr_c[42]
  PIN hdr_c[43]
    DIRECTION INPUT ;
    USE SIGNAL ;
    PORT
      LAYER M3 ;
        RECT  6.336 0 6.354 0.038 ;
    END
  END hdr_c[43]
  PIN hdr_c[44]
    DIRECTION INPUT ;
    USE SIGNAL ;
    PORT
      LAYER M5 ;
        RECT  6.384 0 6.408 0.084 ;
    END
  END hdr_c[44]
  PIN hdr_c[45]
    DIRECTION INPUT ;
    USE SIGNAL ;
    PORT
      LAYER M3 ;
        RECT  6.516 0 6.534 0.038 ;
    END
  END hdr_c[45]
  PIN hdr_c[46]
    DIRECTION INPUT ;
    USE SIGNAL ;
    PORT
      LAYER M5 ;
        RECT  6.576 0 6.6 0.084 ;
    END
  END hdr_c[46]
  PIN hdr_c[47]
    DIRECTION INPUT ;
    USE SIGNAL ;
    PORT
      LAYER M3 ;
        RECT  6.696 0 6.714 0.038 ;
    END
  END hdr_c[47]
  PIN hdr_c[48]
    DIRECTION INPUT ;
    USE SIGNAL ;
    PORT
      LAYER M5 ;
        RECT  6.864 0 6.888 0.084 ;
    END
  END hdr_c[48]
  PIN hdr_c[49]
    DIRECTION INPUT ;
    USE SIGNAL ;
    PORT
      LAYER M3 ;
        RECT  6.912 0 6.93 0.038 ;
    END
  END hdr_c[49]
  PIN hdr_c[4]
    DIRECTION INPUT ;
    USE SIGNAL ;
    PORT
      LAYER M5 ;
        RECT  2.352 0 2.376 0.084 ;
    END
  END hdr_c[4]
  PIN hdr_c[50]
    DIRECTION INPUT ;
    USE SIGNAL ;
    PORT
      LAYER M5 ;
        RECT  7.056 0 7.08 0.084 ;
    END
  END hdr_c[50]
  PIN hdr_c[51]
    DIRECTION INPUT ;
    USE SIGNAL ;
    PORT
      LAYER M3 ;
        RECT  7.092 0 7.11 0.038 ;
    END
  END hdr_c[51]
  PIN hdr_c[52]
    DIRECTION INPUT ;
    USE SIGNAL ;
    PORT
      LAYER M5 ;
        RECT  7.248 0 7.272 0.084 ;
    END
  END hdr_c[52]
  PIN hdr_c[53]
    DIRECTION INPUT ;
    USE SIGNAL ;
    PORT
      LAYER M3 ;
        RECT  7.272 0 7.29 0.038 ;
    END
  END hdr_c[53]
  PIN hdr_c[54]
    DIRECTION INPUT ;
    USE SIGNAL ;
    PORT
      LAYER M5 ;
        RECT  7.44 0 7.464 0.084 ;
    END
  END hdr_c[54]
  PIN hdr_c[55]
    DIRECTION INPUT ;
    USE SIGNAL ;
    PORT
      LAYER M3 ;
        RECT  7.56 0 7.578 0.038 ;
    END
  END hdr_c[55]
  PIN hdr_c[56]
    DIRECTION INPUT ;
    USE SIGNAL ;
    PORT
      LAYER M5 ;
        RECT  7.632 0 7.656 0.084 ;
    END
  END hdr_c[56]
  PIN hdr_c[57]
    DIRECTION INPUT ;
    USE SIGNAL ;
    PORT
      LAYER M3 ;
        RECT  7.776 0 7.794 0.038 ;
    END
  END hdr_c[57]
  PIN hdr_c[58]
    DIRECTION INPUT ;
    USE SIGNAL ;
    PORT
      LAYER M5 ;
        RECT  7.824 0 7.848 0.084 ;
    END
  END hdr_c[58]
  PIN hdr_c[59]
    DIRECTION INPUT ;
    USE SIGNAL ;
    PORT
      LAYER M3 ;
        RECT  7.956 0 7.974 0.038 ;
    END
  END hdr_c[59]
  PIN hdr_c[5]
    DIRECTION INPUT ;
    USE SIGNAL ;
    PORT
      LAYER M3 ;
        RECT  2.376 0 2.394 0.038 ;
    END
  END hdr_c[5]
  PIN hdr_c[60]
    DIRECTION INPUT ;
    USE SIGNAL ;
    PORT
      LAYER M5 ;
        RECT  8.016 0 8.04 0.084 ;
    END
  END hdr_c[60]
  PIN hdr_c[61]
    DIRECTION INPUT ;
    USE SIGNAL ;
    PORT
      LAYER M3 ;
        RECT  8.136 0 8.154 0.038 ;
    END
  END hdr_c[61]
  PIN hdr_c[62]
    DIRECTION INPUT ;
    USE SIGNAL ;
    PORT
      LAYER M5 ;
        RECT  8.208 0 8.232 0.084 ;
    END
  END hdr_c[62]
  PIN hdr_c[63]
    DIRECTION INPUT ;
    USE SIGNAL ;
    PORT
      LAYER M3 ;
        RECT  8.352 0 8.37 0.038 ;
    END
  END hdr_c[63]
  PIN hdr_c[64]
    DIRECTION INPUT ;
    USE SIGNAL ;
    PORT
      LAYER M5 ;
        RECT  8.496 0 8.52 0.084 ;
    END
  END hdr_c[64]
  PIN hdr_c[65]
    DIRECTION INPUT ;
    USE SIGNAL ;
    PORT
      LAYER M3 ;
        RECT  8.532 0 8.55 0.038 ;
    END
  END hdr_c[65]
  PIN hdr_c[66]
    DIRECTION INPUT ;
    USE SIGNAL ;
    PORT
      LAYER M5 ;
        RECT  8.688 0 8.712 0.084 ;
    END
  END hdr_c[66]
  PIN hdr_c[67]
    DIRECTION INPUT ;
    USE SIGNAL ;
    PORT
      LAYER M3 ;
        RECT  8.712 0 8.73 0.038 ;
    END
  END hdr_c[67]
  PIN hdr_c[68]
    DIRECTION INPUT ;
    USE SIGNAL ;
    PORT
      LAYER M5 ;
        RECT  8.88 0 8.904 0.084 ;
    END
  END hdr_c[68]
  PIN hdr_c[69]
    DIRECTION INPUT ;
    USE SIGNAL ;
    PORT
      LAYER M3 ;
        RECT  8.928 0 8.946 0.038 ;
    END
  END hdr_c[69]
  PIN hdr_c[6]
    DIRECTION INPUT ;
    USE SIGNAL ;
    PORT
      LAYER M5 ;
        RECT  2.544 0 2.568 0.084 ;
    END
  END hdr_c[6]
  PIN hdr_c[70]
    DIRECTION INPUT ;
    USE SIGNAL ;
    PORT
      LAYER M5 ;
        RECT  9.072 0 9.096 0.084 ;
    END
  END hdr_c[70]
  PIN hdr_c[71]
    DIRECTION INPUT ;
    USE SIGNAL ;
    PORT
      LAYER M3 ;
        RECT  9.216 0 9.234 0.038 ;
    END
  END hdr_c[71]
  PIN hdr_c[72]
    DIRECTION INPUT ;
    USE SIGNAL ;
    PORT
      LAYER M5 ;
        RECT  9.264 0 9.288 0.084 ;
    END
  END hdr_c[72]
  PIN hdr_c[73]
    DIRECTION INPUT ;
    USE SIGNAL ;
    PORT
      LAYER M3 ;
        RECT  9.396 0 9.414 0.038 ;
    END
  END hdr_c[73]
  PIN hdr_c[74]
    DIRECTION INPUT ;
    USE SIGNAL ;
    PORT
      LAYER M5 ;
        RECT  9.456 0 9.48 0.084 ;
    END
  END hdr_c[74]
  PIN hdr_c[75]
    DIRECTION INPUT ;
    USE SIGNAL ;
    PORT
      LAYER M3 ;
        RECT  9.576 0 9.594 0.038 ;
    END
  END hdr_c[75]
  PIN hdr_c[76]
    DIRECTION INPUT ;
    USE SIGNAL ;
    PORT
      LAYER M5 ;
        RECT  9.648 0 9.672 0.084 ;
    END
  END hdr_c[76]
  PIN hdr_c[77]
    DIRECTION INPUT ;
    USE SIGNAL ;
    PORT
      LAYER M3 ;
        RECT  9.792 0 9.81 0.038 ;
    END
  END hdr_c[77]
  PIN hdr_c[78]
    DIRECTION INPUT ;
    USE SIGNAL ;
    PORT
      LAYER M5 ;
        RECT  9.936 0 9.96 0.084 ;
    END
  END hdr_c[78]
  PIN hdr_c[79]
    DIRECTION INPUT ;
    USE SIGNAL ;
    PORT
      LAYER M3 ;
        RECT  9.972 0 9.99 0.038 ;
    END
  END hdr_c[79]
  PIN hdr_c[7]
    DIRECTION INPUT ;
    USE SIGNAL ;
    PORT
      LAYER M3 ;
        RECT  2.592 0 2.61 0.038 ;
    END
  END hdr_c[7]
  PIN hdr_c[80]
    DIRECTION INPUT ;
    USE SIGNAL ;
    PORT
      LAYER M5 ;
        RECT  10.128 0 10.152 0.084 ;
    END
  END hdr_c[80]
  PIN hdr_c[81]
    DIRECTION INPUT ;
    USE SIGNAL ;
    PORT
      LAYER M3 ;
        RECT  10.152 0 10.17 0.038 ;
    END
  END hdr_c[81]
  PIN hdr_c[82]
    DIRECTION INPUT ;
    USE SIGNAL ;
    PORT
      LAYER M5 ;
        RECT  10.32 0 10.344 0.084 ;
    END
  END hdr_c[82]
  PIN hdr_c[83]
    DIRECTION INPUT ;
    USE SIGNAL ;
    PORT
      LAYER M3 ;
        RECT  10.368 0 10.386 0.038 ;
    END
  END hdr_c[83]
  PIN hdr_c[84]
    DIRECTION INPUT ;
    USE SIGNAL ;
    PORT
      LAYER M5 ;
        RECT  10.512 0 10.536 0.084 ;
    END
  END hdr_c[84]
  PIN hdr_c[85]
    DIRECTION INPUT ;
    USE SIGNAL ;
    PORT
      LAYER M3 ;
        RECT  10.548 0 10.566 0.038 ;
    END
  END hdr_c[85]
  PIN hdr_c[86]
    DIRECTION INPUT ;
    USE SIGNAL ;
    PORT
      LAYER M5 ;
        RECT  10.704 0 10.728 0.084 ;
    END
  END hdr_c[86]
  PIN hdr_c[87]
    DIRECTION INPUT ;
    USE SIGNAL ;
    PORT
      LAYER M3 ;
        RECT  10.836 0 10.854 0.038 ;
    END
  END hdr_c[87]
  PIN hdr_c[88]
    DIRECTION INPUT ;
    USE SIGNAL ;
    PORT
      LAYER M5 ;
        RECT  10.896 0 10.92 0.084 ;
    END
  END hdr_c[88]
  PIN hdr_c[89]
    DIRECTION INPUT ;
    USE SIGNAL ;
    PORT
      LAYER M3 ;
        RECT  11.016 0 11.034 0.038 ;
    END
  END hdr_c[89]
  PIN hdr_c[8]
    DIRECTION INPUT ;
    USE SIGNAL ;
    PORT
      LAYER M5 ;
        RECT  2.736 0 2.76 0.084 ;
    END
  END hdr_c[8]
  PIN hdr_c[90]
    DIRECTION INPUT ;
    USE SIGNAL ;
    PORT
      LAYER M5 ;
        RECT  11.088 0 11.112 0.084 ;
    END
  END hdr_c[90]
  PIN hdr_c[91]
    DIRECTION INPUT ;
    USE SIGNAL ;
    PORT
      LAYER M3 ;
        RECT  11.232 0 11.25 0.038 ;
    END
  END hdr_c[91]
  PIN hdr_c[92]
    DIRECTION INPUT ;
    USE SIGNAL ;
    PORT
      LAYER M5 ;
        RECT  11.28 0 11.304 0.084 ;
    END
  END hdr_c[92]
  PIN hdr_c[93]
    DIRECTION INPUT ;
    USE SIGNAL ;
    PORT
      LAYER M3 ;
        RECT  11.412 0 11.43 0.038 ;
    END
  END hdr_c[93]
  PIN hdr_c[94]
    DIRECTION INPUT ;
    USE SIGNAL ;
    PORT
      LAYER M5 ;
        RECT  11.568 0 11.592 0.084 ;
    END
  END hdr_c[94]
  PIN hdr_c[95]
    DIRECTION INPUT ;
    USE SIGNAL ;
    PORT
      LAYER M3 ;
        RECT  11.592 0 11.61 0.038 ;
    END
  END hdr_c[95]
  PIN hdr_c[96]
    DIRECTION INPUT ;
    USE SIGNAL ;
    PORT
      LAYER M5 ;
        RECT  11.76 0 11.784 0.084 ;
    END
  END hdr_c[96]
  PIN hdr_c[97]
    DIRECTION INPUT ;
    USE SIGNAL ;
    PORT
      LAYER M3 ;
        RECT  11.808 0 11.826 0.038 ;
    END
  END hdr_c[97]
  PIN hdr_c[98]
    DIRECTION INPUT ;
    USE SIGNAL ;
    PORT
      LAYER M5 ;
        RECT  11.952 0 11.976 0.084 ;
    END
  END hdr_c[98]
  PIN hdr_c[99]
    DIRECTION INPUT ;
    USE SIGNAL ;
    PORT
      LAYER M3 ;
        RECT  11.988 0 12.006 0.038 ;
    END
  END hdr_c[99]
  PIN hdr_c[9]
    DIRECTION INPUT ;
    USE SIGNAL ;
    PORT
      LAYER M3 ;
        RECT  2.772 0 2.79 0.038 ;
    END
  END hdr_c[9]
  PIN hdr_out[0]
    DIRECTION OUTPUT ;
    USE SIGNAL ;
    PORT
      LAYER M5 ;
        RECT  1.872 25.836 1.896 25.92 ;
    END
  END hdr_out[0]
  PIN hdr_out[100]
    DIRECTION OUTPUT ;
    USE SIGNAL ;
    PORT
      LAYER M5 ;
        RECT  12.144 25.836 12.168 25.92 ;
    END
  END hdr_out[100]
  PIN hdr_out[101]
    DIRECTION OUTPUT ;
    USE SIGNAL ;
    PORT
      LAYER M3 ;
        RECT  12.276 25.882 12.294 25.92 ;
    END
  END hdr_out[101]
  PIN hdr_out[102]
    DIRECTION OUTPUT ;
    USE SIGNAL ;
    PORT
      LAYER M5 ;
        RECT  12.336 25.836 12.36 25.92 ;
    END
  END hdr_out[102]
  PIN hdr_out[103]
    DIRECTION OUTPUT ;
    USE SIGNAL ;
    PORT
      LAYER M3 ;
        RECT  12.456 25.882 12.474 25.92 ;
    END
  END hdr_out[103]
  PIN hdr_out[104]
    DIRECTION OUTPUT ;
    USE SIGNAL ;
    PORT
      LAYER M5 ;
        RECT  12.528 25.836 12.552 25.92 ;
    END
  END hdr_out[104]
  PIN hdr_out[105]
    DIRECTION OUTPUT ;
    USE SIGNAL ;
    PORT
      LAYER M3 ;
        RECT  12.672 25.882 12.69 25.92 ;
    END
  END hdr_out[105]
  PIN hdr_out[106]
    DIRECTION OUTPUT ;
    USE SIGNAL ;
    PORT
      LAYER M5 ;
        RECT  12.72 25.836 12.744 25.92 ;
    END
  END hdr_out[106]
  PIN hdr_out[107]
    DIRECTION OUTPUT ;
    USE SIGNAL ;
    PORT
      LAYER M3 ;
        RECT  12.852 25.882 12.87 25.92 ;
    END
  END hdr_out[107]
  PIN hdr_out[10]
    DIRECTION OUTPUT ;
    USE SIGNAL ;
    PORT
      LAYER M5 ;
        RECT  2.928 25.836 2.952 25.92 ;
    END
  END hdr_out[10]
  PIN hdr_out[11]
    DIRECTION OUTPUT ;
    USE SIGNAL ;
    PORT
      LAYER M3 ;
        RECT  3.06 25.882 3.078 25.92 ;
    END
  END hdr_out[11]
  PIN hdr_out[12]
    DIRECTION OUTPUT ;
    USE SIGNAL ;
    PORT
      LAYER M5 ;
        RECT  3.12 25.836 3.144 25.92 ;
    END
  END hdr_out[12]
  PIN hdr_out[13]
    DIRECTION OUTPUT ;
    USE SIGNAL ;
    PORT
      LAYER M3 ;
        RECT  3.24 25.882 3.258 25.92 ;
    END
  END hdr_out[13]
  PIN hdr_out[14]
    DIRECTION OUTPUT ;
    USE SIGNAL ;
    PORT
      LAYER M5 ;
        RECT  3.312 25.836 3.336 25.92 ;
    END
  END hdr_out[14]
  PIN hdr_out[15]
    DIRECTION OUTPUT ;
    USE SIGNAL ;
    PORT
      LAYER M3 ;
        RECT  3.456 25.882 3.474 25.92 ;
    END
  END hdr_out[15]
  PIN hdr_out[16]
    DIRECTION OUTPUT ;
    USE SIGNAL ;
    PORT
      LAYER M5 ;
        RECT  3.504 25.836 3.528 25.92 ;
    END
  END hdr_out[16]
  PIN hdr_out[17]
    DIRECTION OUTPUT ;
    USE SIGNAL ;
    PORT
      LAYER M3 ;
        RECT  3.636 25.882 3.654 25.92 ;
    END
  END hdr_out[17]
  PIN hdr_out[18]
    DIRECTION OUTPUT ;
    USE SIGNAL ;
    PORT
      LAYER M5 ;
        RECT  3.792 25.836 3.816 25.92 ;
    END
  END hdr_out[18]
  PIN hdr_out[19]
    DIRECTION OUTPUT ;
    USE SIGNAL ;
    PORT
      LAYER M3 ;
        RECT  3.816 25.882 3.834 25.92 ;
    END
  END hdr_out[19]
  PIN hdr_out[1]
    DIRECTION OUTPUT ;
    USE SIGNAL ;
    PORT
      LAYER M3 ;
        RECT  2.016 25.882 2.034 25.92 ;
    END
  END hdr_out[1]
  PIN hdr_out[20]
    DIRECTION OUTPUT ;
    USE SIGNAL ;
    PORT
      LAYER M5 ;
        RECT  3.984 25.836 4.008 25.92 ;
    END
  END hdr_out[20]
  PIN hdr_out[21]
    DIRECTION OUTPUT ;
    USE SIGNAL ;
    PORT
      LAYER M3 ;
        RECT  4.032 25.882 4.05 25.92 ;
    END
  END hdr_out[21]
  PIN hdr_out[22]
    DIRECTION OUTPUT ;
    USE SIGNAL ;
    PORT
      LAYER M5 ;
        RECT  4.176 25.836 4.2 25.92 ;
    END
  END hdr_out[22]
  PIN hdr_out[23]
    DIRECTION OUTPUT ;
    USE SIGNAL ;
    PORT
      LAYER M3 ;
        RECT  4.212 25.882 4.23 25.92 ;
    END
  END hdr_out[23]
  PIN hdr_out[24]
    DIRECTION OUTPUT ;
    USE SIGNAL ;
    PORT
      LAYER M5 ;
        RECT  4.368 25.836 4.392 25.92 ;
    END
  END hdr_out[24]
  PIN hdr_out[25]
    DIRECTION OUTPUT ;
    USE SIGNAL ;
    PORT
      LAYER M3 ;
        RECT  4.5 25.882 4.518 25.92 ;
    END
  END hdr_out[25]
  PIN hdr_out[26]
    DIRECTION OUTPUT ;
    USE SIGNAL ;
    PORT
      LAYER M5 ;
        RECT  4.56 25.836 4.584 25.92 ;
    END
  END hdr_out[26]
  PIN hdr_out[27]
    DIRECTION OUTPUT ;
    USE SIGNAL ;
    PORT
      LAYER M3 ;
        RECT  4.68 25.882 4.698 25.92 ;
    END
  END hdr_out[27]
  PIN hdr_out[28]
    DIRECTION OUTPUT ;
    USE SIGNAL ;
    PORT
      LAYER M5 ;
        RECT  4.752 25.836 4.776 25.92 ;
    END
  END hdr_out[28]
  PIN hdr_out[29]
    DIRECTION OUTPUT ;
    USE SIGNAL ;
    PORT
      LAYER M3 ;
        RECT  4.896 25.882 4.914 25.92 ;
    END
  END hdr_out[29]
  PIN hdr_out[2]
    DIRECTION OUTPUT ;
    USE SIGNAL ;
    PORT
      LAYER M5 ;
        RECT  2.064 25.836 2.088 25.92 ;
    END
  END hdr_out[2]
  PIN hdr_out[30]
    DIRECTION OUTPUT ;
    USE SIGNAL ;
    PORT
      LAYER M5 ;
        RECT  4.944 25.836 4.968 25.92 ;
    END
  END hdr_out[30]
  PIN hdr_out[31]
    DIRECTION OUTPUT ;
    USE SIGNAL ;
    PORT
      LAYER M3 ;
        RECT  5.076 25.882 5.094 25.92 ;
    END
  END hdr_out[31]
  PIN hdr_out[32]
    DIRECTION OUTPUT ;
    USE SIGNAL ;
    PORT
      LAYER M5 ;
        RECT  5.136 25.836 5.16 25.92 ;
    END
  END hdr_out[32]
  PIN hdr_out[33]
    DIRECTION OUTPUT ;
    USE SIGNAL ;
    PORT
      LAYER M3 ;
        RECT  5.256 25.882 5.274 25.92 ;
    END
  END hdr_out[33]
  PIN hdr_out[34]
    DIRECTION OUTPUT ;
    USE SIGNAL ;
    PORT
      LAYER M5 ;
        RECT  5.424 25.836 5.448 25.92 ;
    END
  END hdr_out[34]
  PIN hdr_out[35]
    DIRECTION OUTPUT ;
    USE SIGNAL ;
    PORT
      LAYER M3 ;
        RECT  5.472 25.882 5.49 25.92 ;
    END
  END hdr_out[35]
  PIN hdr_out[36]
    DIRECTION OUTPUT ;
    USE SIGNAL ;
    PORT
      LAYER M5 ;
        RECT  5.616 25.836 5.64 25.92 ;
    END
  END hdr_out[36]
  PIN hdr_out[37]
    DIRECTION OUTPUT ;
    USE SIGNAL ;
    PORT
      LAYER M3 ;
        RECT  5.652 25.882 5.67 25.92 ;
    END
  END hdr_out[37]
  PIN hdr_out[38]
    DIRECTION OUTPUT ;
    USE SIGNAL ;
    PORT
      LAYER M5 ;
        RECT  5.808 25.836 5.832 25.92 ;
    END
  END hdr_out[38]
  PIN hdr_out[39]
    DIRECTION OUTPUT ;
    USE SIGNAL ;
    PORT
      LAYER M3 ;
        RECT  5.832 25.882 5.85 25.92 ;
    END
  END hdr_out[39]
  PIN hdr_out[3]
    DIRECTION OUTPUT ;
    USE SIGNAL ;
    PORT
      LAYER M3 ;
        RECT  2.196 25.882 2.214 25.92 ;
    END
  END hdr_out[3]
  PIN hdr_out[40]
    DIRECTION OUTPUT ;
    USE SIGNAL ;
    PORT
      LAYER M5 ;
        RECT  6 25.836 6.024 25.92 ;
    END
  END hdr_out[40]
  PIN hdr_out[41]
    DIRECTION OUTPUT ;
    USE SIGNAL ;
    PORT
      LAYER M3 ;
        RECT  6.12 25.882 6.138 25.92 ;
    END
  END hdr_out[41]
  PIN hdr_out[42]
    DIRECTION OUTPUT ;
    USE SIGNAL ;
    PORT
      LAYER M5 ;
        RECT  6.192 25.836 6.216 25.92 ;
    END
  END hdr_out[42]
  PIN hdr_out[43]
    DIRECTION OUTPUT ;
    USE SIGNAL ;
    PORT
      LAYER M3 ;
        RECT  6.336 25.882 6.354 25.92 ;
    END
  END hdr_out[43]
  PIN hdr_out[44]
    DIRECTION OUTPUT ;
    USE SIGNAL ;
    PORT
      LAYER M5 ;
        RECT  6.384 25.836 6.408 25.92 ;
    END
  END hdr_out[44]
  PIN hdr_out[45]
    DIRECTION OUTPUT ;
    USE SIGNAL ;
    PORT
      LAYER M3 ;
        RECT  6.516 25.882 6.534 25.92 ;
    END
  END hdr_out[45]
  PIN hdr_out[46]
    DIRECTION OUTPUT ;
    USE SIGNAL ;
    PORT
      LAYER M5 ;
        RECT  6.576 25.836 6.6 25.92 ;
    END
  END hdr_out[46]
  PIN hdr_out[47]
    DIRECTION OUTPUT ;
    USE SIGNAL ;
    PORT
      LAYER M3 ;
        RECT  6.696 25.882 6.714 25.92 ;
    END
  END hdr_out[47]
  PIN hdr_out[48]
    DIRECTION OUTPUT ;
    USE SIGNAL ;
    PORT
      LAYER M5 ;
        RECT  6.864 25.836 6.888 25.92 ;
    END
  END hdr_out[48]
  PIN hdr_out[49]
    DIRECTION OUTPUT ;
    USE SIGNAL ;
    PORT
      LAYER M3 ;
        RECT  6.912 25.882 6.93 25.92 ;
    END
  END hdr_out[49]
  PIN hdr_out[4]
    DIRECTION OUTPUT ;
    USE SIGNAL ;
    PORT
      LAYER M5 ;
        RECT  2.352 25.836 2.376 25.92 ;
    END
  END hdr_out[4]
  PIN hdr_out[50]
    DIRECTION OUTPUT ;
    USE SIGNAL ;
    PORT
      LAYER M5 ;
        RECT  7.056 25.836 7.08 25.92 ;
    END
  END hdr_out[50]
  PIN hdr_out[51]
    DIRECTION OUTPUT ;
    USE SIGNAL ;
    PORT
      LAYER M3 ;
        RECT  7.092 25.882 7.11 25.92 ;
    END
  END hdr_out[51]
  PIN hdr_out[52]
    DIRECTION OUTPUT ;
    USE SIGNAL ;
    PORT
      LAYER M5 ;
        RECT  7.248 25.836 7.272 25.92 ;
    END
  END hdr_out[52]
  PIN hdr_out[53]
    DIRECTION OUTPUT ;
    USE SIGNAL ;
    PORT
      LAYER M3 ;
        RECT  7.272 25.882 7.29 25.92 ;
    END
  END hdr_out[53]
  PIN hdr_out[54]
    DIRECTION OUTPUT ;
    USE SIGNAL ;
    PORT
      LAYER M5 ;
        RECT  7.44 25.836 7.464 25.92 ;
    END
  END hdr_out[54]
  PIN hdr_out[55]
    DIRECTION OUTPUT ;
    USE SIGNAL ;
    PORT
      LAYER M3 ;
        RECT  7.56 25.882 7.578 25.92 ;
    END
  END hdr_out[55]
  PIN hdr_out[56]
    DIRECTION OUTPUT ;
    USE SIGNAL ;
    PORT
      LAYER M5 ;
        RECT  7.632 25.836 7.656 25.92 ;
    END
  END hdr_out[56]
  PIN hdr_out[57]
    DIRECTION OUTPUT ;
    USE SIGNAL ;
    PORT
      LAYER M3 ;
        RECT  7.776 25.882 7.794 25.92 ;
    END
  END hdr_out[57]
  PIN hdr_out[58]
    DIRECTION OUTPUT ;
    USE SIGNAL ;
    PORT
      LAYER M5 ;
        RECT  7.824 25.836 7.848 25.92 ;
    END
  END hdr_out[58]
  PIN hdr_out[59]
    DIRECTION OUTPUT ;
    USE SIGNAL ;
    PORT
      LAYER M3 ;
        RECT  7.956 25.882 7.974 25.92 ;
    END
  END hdr_out[59]
  PIN hdr_out[5]
    DIRECTION OUTPUT ;
    USE SIGNAL ;
    PORT
      LAYER M3 ;
        RECT  2.376 25.882 2.394 25.92 ;
    END
  END hdr_out[5]
  PIN hdr_out[60]
    DIRECTION OUTPUT ;
    USE SIGNAL ;
    PORT
      LAYER M5 ;
        RECT  8.016 25.836 8.04 25.92 ;
    END
  END hdr_out[60]
  PIN hdr_out[61]
    DIRECTION OUTPUT ;
    USE SIGNAL ;
    PORT
      LAYER M3 ;
        RECT  8.136 25.882 8.154 25.92 ;
    END
  END hdr_out[61]
  PIN hdr_out[62]
    DIRECTION OUTPUT ;
    USE SIGNAL ;
    PORT
      LAYER M5 ;
        RECT  8.208 25.836 8.232 25.92 ;
    END
  END hdr_out[62]
  PIN hdr_out[63]
    DIRECTION OUTPUT ;
    USE SIGNAL ;
    PORT
      LAYER M3 ;
        RECT  8.352 25.882 8.37 25.92 ;
    END
  END hdr_out[63]
  PIN hdr_out[64]
    DIRECTION OUTPUT ;
    USE SIGNAL ;
    PORT
      LAYER M5 ;
        RECT  8.496 25.836 8.52 25.92 ;
    END
  END hdr_out[64]
  PIN hdr_out[65]
    DIRECTION OUTPUT ;
    USE SIGNAL ;
    PORT
      LAYER M3 ;
        RECT  8.532 25.882 8.55 25.92 ;
    END
  END hdr_out[65]
  PIN hdr_out[66]
    DIRECTION OUTPUT ;
    USE SIGNAL ;
    PORT
      LAYER M5 ;
        RECT  8.688 25.836 8.712 25.92 ;
    END
  END hdr_out[66]
  PIN hdr_out[67]
    DIRECTION OUTPUT ;
    USE SIGNAL ;
    PORT
      LAYER M3 ;
        RECT  8.712 25.882 8.73 25.92 ;
    END
  END hdr_out[67]
  PIN hdr_out[68]
    DIRECTION OUTPUT ;
    USE SIGNAL ;
    PORT
      LAYER M5 ;
        RECT  8.88 25.836 8.904 25.92 ;
    END
  END hdr_out[68]
  PIN hdr_out[69]
    DIRECTION OUTPUT ;
    USE SIGNAL ;
    PORT
      LAYER M3 ;
        RECT  8.928 25.882 8.946 25.92 ;
    END
  END hdr_out[69]
  PIN hdr_out[6]
    DIRECTION OUTPUT ;
    USE SIGNAL ;
    PORT
      LAYER M5 ;
        RECT  2.544 25.836 2.568 25.92 ;
    END
  END hdr_out[6]
  PIN hdr_out[70]
    DIRECTION OUTPUT ;
    USE SIGNAL ;
    PORT
      LAYER M5 ;
        RECT  9.072 25.836 9.096 25.92 ;
    END
  END hdr_out[70]
  PIN hdr_out[71]
    DIRECTION OUTPUT ;
    USE SIGNAL ;
    PORT
      LAYER M3 ;
        RECT  9.216 25.882 9.234 25.92 ;
    END
  END hdr_out[71]
  PIN hdr_out[72]
    DIRECTION OUTPUT ;
    USE SIGNAL ;
    PORT
      LAYER M5 ;
        RECT  9.264 25.836 9.288 25.92 ;
    END
  END hdr_out[72]
  PIN hdr_out[73]
    DIRECTION OUTPUT ;
    USE SIGNAL ;
    PORT
      LAYER M3 ;
        RECT  9.396 25.882 9.414 25.92 ;
    END
  END hdr_out[73]
  PIN hdr_out[74]
    DIRECTION OUTPUT ;
    USE SIGNAL ;
    PORT
      LAYER M5 ;
        RECT  9.456 25.836 9.48 25.92 ;
    END
  END hdr_out[74]
  PIN hdr_out[75]
    DIRECTION OUTPUT ;
    USE SIGNAL ;
    PORT
      LAYER M3 ;
        RECT  9.576 25.882 9.594 25.92 ;
    END
  END hdr_out[75]
  PIN hdr_out[76]
    DIRECTION OUTPUT ;
    USE SIGNAL ;
    PORT
      LAYER M5 ;
        RECT  9.648 25.836 9.672 25.92 ;
    END
  END hdr_out[76]
  PIN hdr_out[77]
    DIRECTION OUTPUT ;
    USE SIGNAL ;
    PORT
      LAYER M3 ;
        RECT  9.792 25.882 9.81 25.92 ;
    END
  END hdr_out[77]
  PIN hdr_out[78]
    DIRECTION OUTPUT ;
    USE SIGNAL ;
    PORT
      LAYER M5 ;
        RECT  9.936 25.836 9.96 25.92 ;
    END
  END hdr_out[78]
  PIN hdr_out[79]
    DIRECTION OUTPUT ;
    USE SIGNAL ;
    PORT
      LAYER M3 ;
        RECT  9.972 25.882 9.99 25.92 ;
    END
  END hdr_out[79]
  PIN hdr_out[7]
    DIRECTION OUTPUT ;
    USE SIGNAL ;
    PORT
      LAYER M3 ;
        RECT  2.592 25.882 2.61 25.92 ;
    END
  END hdr_out[7]
  PIN hdr_out[80]
    DIRECTION OUTPUT ;
    USE SIGNAL ;
    PORT
      LAYER M5 ;
        RECT  10.128 25.836 10.152 25.92 ;
    END
  END hdr_out[80]
  PIN hdr_out[81]
    DIRECTION OUTPUT ;
    USE SIGNAL ;
    PORT
      LAYER M3 ;
        RECT  10.152 25.882 10.17 25.92 ;
    END
  END hdr_out[81]
  PIN hdr_out[82]
    DIRECTION OUTPUT ;
    USE SIGNAL ;
    PORT
      LAYER M5 ;
        RECT  10.32 25.836 10.344 25.92 ;
    END
  END hdr_out[82]
  PIN hdr_out[83]
    DIRECTION OUTPUT ;
    USE SIGNAL ;
    PORT
      LAYER M3 ;
        RECT  10.368 25.882 10.386 25.92 ;
    END
  END hdr_out[83]
  PIN hdr_out[84]
    DIRECTION OUTPUT ;
    USE SIGNAL ;
    PORT
      LAYER M5 ;
        RECT  10.512 25.836 10.536 25.92 ;
    END
  END hdr_out[84]
  PIN hdr_out[85]
    DIRECTION OUTPUT ;
    USE SIGNAL ;
    PORT
      LAYER M3 ;
        RECT  10.548 25.882 10.566 25.92 ;
    END
  END hdr_out[85]
  PIN hdr_out[86]
    DIRECTION OUTPUT ;
    USE SIGNAL ;
    PORT
      LAYER M5 ;
        RECT  10.704 25.836 10.728 25.92 ;
    END
  END hdr_out[86]
  PIN hdr_out[87]
    DIRECTION OUTPUT ;
    USE SIGNAL ;
    PORT
      LAYER M3 ;
        RECT  10.836 25.882 10.854 25.92 ;
    END
  END hdr_out[87]
  PIN hdr_out[88]
    DIRECTION OUTPUT ;
    USE SIGNAL ;
    PORT
      LAYER M5 ;
        RECT  10.896 25.836 10.92 25.92 ;
    END
  END hdr_out[88]
  PIN hdr_out[89]
    DIRECTION OUTPUT ;
    USE SIGNAL ;
    PORT
      LAYER M3 ;
        RECT  11.016 25.882 11.034 25.92 ;
    END
  END hdr_out[89]
  PIN hdr_out[8]
    DIRECTION OUTPUT ;
    USE SIGNAL ;
    PORT
      LAYER M5 ;
        RECT  2.736 25.836 2.76 25.92 ;
    END
  END hdr_out[8]
  PIN hdr_out[90]
    DIRECTION OUTPUT ;
    USE SIGNAL ;
    PORT
      LAYER M5 ;
        RECT  11.088 25.836 11.112 25.92 ;
    END
  END hdr_out[90]
  PIN hdr_out[91]
    DIRECTION OUTPUT ;
    USE SIGNAL ;
    PORT
      LAYER M3 ;
        RECT  11.232 25.882 11.25 25.92 ;
    END
  END hdr_out[91]
  PIN hdr_out[92]
    DIRECTION OUTPUT ;
    USE SIGNAL ;
    PORT
      LAYER M5 ;
        RECT  11.28 25.836 11.304 25.92 ;
    END
  END hdr_out[92]
  PIN hdr_out[93]
    DIRECTION OUTPUT ;
    USE SIGNAL ;
    PORT
      LAYER M3 ;
        RECT  11.412 25.882 11.43 25.92 ;
    END
  END hdr_out[93]
  PIN hdr_out[94]
    DIRECTION OUTPUT ;
    USE SIGNAL ;
    PORT
      LAYER M5 ;
        RECT  11.568 25.836 11.592 25.92 ;
    END
  END hdr_out[94]
  PIN hdr_out[95]
    DIRECTION OUTPUT ;
    USE SIGNAL ;
    PORT
      LAYER M3 ;
        RECT  11.592 25.882 11.61 25.92 ;
    END
  END hdr_out[95]
  PIN hdr_out[96]
    DIRECTION OUTPUT ;
    USE SIGNAL ;
    PORT
      LAYER M5 ;
        RECT  11.76 25.836 11.784 25.92 ;
    END
  END hdr_out[96]
  PIN hdr_out[97]
    DIRECTION OUTPUT ;
    USE SIGNAL ;
    PORT
      LAYER M3 ;
        RECT  11.808 25.882 11.826 25.92 ;
    END
  END hdr_out[97]
  PIN hdr_out[98]
    DIRECTION OUTPUT ;
    USE SIGNAL ;
    PORT
      LAYER M5 ;
        RECT  11.952 25.836 11.976 25.92 ;
    END
  END hdr_out[98]
  PIN hdr_out[99]
    DIRECTION OUTPUT ;
    USE SIGNAL ;
    PORT
      LAYER M3 ;
        RECT  11.988 25.882 12.006 25.92 ;
    END
  END hdr_out[99]
  PIN hdr_out[9]
    DIRECTION OUTPUT ;
    USE SIGNAL ;
    PORT
      LAYER M3 ;
        RECT  2.772 25.882 2.79 25.92 ;
    END
  END hdr_out[9]
  PIN rst_in
    DIRECTION INPUT ;
    USE SIGNAL ;
    PORT
      LAYER M4 ;
        RECT  0 11.952 0.084 11.976 ;
    END
  END rst_in
  PIN rv_c[0]
    DIRECTION INPUT ;
    USE SIGNAL ;
    PORT
      LAYER M5 ;
        RECT  1.488 0 1.512 0.084 ;
    END
  END rv_c[0]
  PIN rv_c[1]
    DIRECTION INPUT ;
    USE SIGNAL ;
    PORT
      LAYER M3 ;
        RECT  1.512 0 1.53 0.038 ;
    END
  END rv_c[1]
  PIN rv_c[2]
    DIRECTION INPUT ;
    USE SIGNAL ;
    PORT
      LAYER M5 ;
        RECT  1.584 0 1.608 0.084 ;
    END
  END rv_c[2]
  PIN rv_c[3]
    DIRECTION INPUT ;
    USE SIGNAL ;
    PORT
      LAYER M3 ;
        RECT  1.62 0 1.638 0.038 ;
    END
  END rv_c[3]
  PIN rv_c[4]
    DIRECTION INPUT ;
    USE SIGNAL ;
    PORT
      LAYER M5 ;
        RECT  1.68 0 1.704 0.084 ;
    END
  END rv_c[4]
  PIN rv_c[5]
    DIRECTION INPUT ;
    USE SIGNAL ;
    PORT
      LAYER M3 ;
        RECT  1.728 0 1.746 0.038 ;
    END
  END rv_c[5]
  PIN rv_c[6]
    DIRECTION INPUT ;
    USE SIGNAL ;
    PORT
      LAYER M5 ;
        RECT  1.776 0 1.8 0.084 ;
    END
  END rv_c[6]
  PIN rv_c[7]
    DIRECTION INPUT ;
    USE SIGNAL ;
    PORT
      LAYER M3 ;
        RECT  1.8 0 1.818 0.038 ;
    END
  END rv_c[7]
  PIN rv_out[0]
    DIRECTION OUTPUT ;
    USE SIGNAL ;
    PORT
      LAYER M5 ;
        RECT  1.104 25.836 1.128 25.92 ;
    END
  END rv_out[0]
  PIN rv_out[1]
    DIRECTION OUTPUT ;
    USE SIGNAL ;
    PORT
      LAYER M3 ;
        RECT  1.152 25.882 1.17 25.92 ;
    END
  END rv_out[1]
  PIN rv_out[2]
    DIRECTION OUTPUT ;
    USE SIGNAL ;
    PORT
      LAYER M5 ;
        RECT  1.296 25.836 1.32 25.92 ;
    END
  END rv_out[2]
  PIN rv_out[3]
    DIRECTION OUTPUT ;
    USE SIGNAL ;
    PORT
      LAYER M3 ;
        RECT  1.44 25.882 1.458 25.92 ;
    END
  END rv_out[3]
  PIN rv_out[4]
    DIRECTION OUTPUT ;
    USE SIGNAL ;
    PORT
      LAYER M5 ;
        RECT  1.488 25.836 1.512 25.92 ;
    END
  END rv_out[4]
  PIN rv_out[5]
    DIRECTION OUTPUT ;
    USE SIGNAL ;
    PORT
      LAYER M3 ;
        RECT  1.62 25.882 1.638 25.92 ;
    END
  END rv_out[5]
  PIN rv_out[6]
    DIRECTION OUTPUT ;
    USE SIGNAL ;
    PORT
      LAYER M5 ;
        RECT  1.68 25.836 1.704 25.92 ;
    END
  END rv_out[6]
  PIN rv_out[7]
    DIRECTION OUTPUT ;
    USE SIGNAL ;
    PORT
      LAYER M3 ;
        RECT  1.8 25.882 1.818 25.92 ;
    END
  END rv_out[7]
  PIN VDD
    DIRECTION INOUT ;
    USE POWER ;
    PORT
      LAYER M5 ;
        RECT  137.592 2.151 137.712 23.769 ;
        RECT  132.192 2.151 132.312 23.769 ;
        RECT  126.792 2.151 126.912 23.769 ;
        RECT  121.392 2.151 121.512 23.769 ;
        RECT  115.992 2.151 116.112 23.769 ;
        RECT  110.592 2.151 110.712 23.769 ;
        RECT  105.192 2.151 105.312 23.769 ;
        RECT  99.792 2.151 99.912 23.769 ;
        RECT  94.392 2.151 94.512 23.769 ;
        RECT  88.992 2.151 89.112 23.769 ;
        RECT  83.592 2.151 83.712 23.769 ;
        RECT  78.192 2.151 78.312 23.769 ;
        RECT  72.792 2.151 72.912 23.769 ;
        RECT  67.392 2.151 67.512 23.769 ;
        RECT  61.992 2.151 62.112 23.769 ;
        RECT  56.592 2.151 56.712 23.769 ;
        RECT  51.192 2.151 51.312 23.769 ;
        RECT  45.792 2.151 45.912 23.769 ;
        RECT  40.392 2.151 40.512 23.769 ;
        RECT  34.992 2.151 35.112 23.769 ;
        RECT  29.592 2.151 29.712 23.769 ;
        RECT  24.192 2.151 24.312 23.769 ;
        RECT  18.792 2.151 18.912 23.769 ;
        RECT  13.392 2.151 13.512 23.769 ;
        RECT  7.992 2.151 8.112 23.769 ;
        RECT  2.592 2.151 2.712 23.769 ;
    END
  END VDD
  PIN VSS
    DIRECTION INOUT ;
    USE GROUND ;
    PORT
      LAYER M5 ;
        RECT  137.4 2.137 137.52 23.783 ;
        RECT  132 2.137 132.12 23.783 ;
        RECT  126.6 2.137 126.72 23.783 ;
        RECT  121.2 2.137 121.32 23.783 ;
        RECT  115.8 2.137 115.92 23.783 ;
        RECT  110.4 2.137 110.52 23.783 ;
        RECT  105 2.137 105.12 23.783 ;
        RECT  99.6 2.137 99.72 23.783 ;
        RECT  94.2 2.137 94.32 23.783 ;
        RECT  88.8 2.137 88.92 23.783 ;
        RECT  83.4 2.137 83.52 23.783 ;
        RECT  78 2.137 78.12 23.783 ;
        RECT  72.6 2.137 72.72 23.783 ;
        RECT  67.2 2.137 67.32 23.783 ;
        RECT  61.8 2.137 61.92 23.783 ;
        RECT  56.4 2.137 56.52 23.783 ;
        RECT  51 2.137 51.12 23.783 ;
        RECT  45.6 2.137 45.72 23.783 ;
        RECT  40.2 2.137 40.32 23.783 ;
        RECT  34.8 2.137 34.92 23.783 ;
        RECT  29.4 2.137 29.52 23.783 ;
        RECT  24 2.137 24.12 23.783 ;
        RECT  18.6 2.137 18.72 23.783 ;
        RECT  13.2 2.137 13.32 23.783 ;
        RECT  7.8 2.137 7.92 23.783 ;
        RECT  2.4 2.137 2.52 23.783 ;
    END
  END VSS
  OBS
    LAYER RVTN ;
     RECT  2.16 2.16 142.02 2.295 ;
     RECT  2.16 2.565 142.02 2.835 ;
     RECT  2.16 3.105 142.02 3.375 ;
     RECT  2.16 3.645 142.02 3.915 ;
     RECT  2.16 4.185 142.02 4.455 ;
     RECT  2.16 4.725 142.02 4.995 ;
     RECT  2.16 5.265 142.02 5.535 ;
     RECT  2.16 5.805 142.02 6.075 ;
     RECT  2.16 6.345 142.02 6.615 ;
     RECT  2.16 6.885 142.02 7.155 ;
     RECT  2.16 7.425 142.02 7.695 ;
     RECT  2.16 7.965 142.02 8.235 ;
     RECT  2.16 8.505 142.02 8.775 ;
     RECT  2.16 9.045 142.02 9.315 ;
     RECT  2.16 9.585 142.02 9.855 ;
     RECT  2.16 10.125 142.02 10.395 ;
     RECT  2.16 10.665 142.02 10.935 ;
     RECT  2.16 11.205 142.02 11.475 ;
     RECT  2.16 11.745 142.02 12.015 ;
     RECT  2.16 12.285 142.02 12.555 ;
     RECT  2.16 12.825 142.02 13.095 ;
     RECT  2.16 13.365 142.02 13.635 ;
     RECT  2.16 13.905 142.02 14.175 ;
     RECT  2.16 14.445 142.02 14.715 ;
     RECT  2.16 14.985 142.02 15.255 ;
     RECT  2.16 15.525 142.02 15.795 ;
     RECT  2.16 16.065 142.02 16.335 ;
     RECT  2.16 16.605 142.02 16.875 ;
     RECT  2.16 17.145 142.02 17.415 ;
     RECT  2.16 17.685 142.02 17.955 ;
     RECT  2.16 18.225 142.02 18.495 ;
     RECT  2.16 18.765 142.02 19.035 ;
     RECT  2.16 19.305 142.02 19.575 ;
     RECT  2.16 19.845 142.02 20.115 ;
     RECT  2.16 20.385 142.02 20.655 ;
     RECT  2.16 20.925 142.02 21.195 ;
     RECT  2.16 21.465 142.02 21.735 ;
     RECT  2.16 22.005 142.02 22.275 ;
     RECT  2.16 22.545 142.02 22.815 ;
     RECT  2.16 23.085 142.02 23.355 ;
     RECT  2.16 23.625 142.02 23.76 ;
    LAYER RVTP ;
     RECT  2.16 2.295 142.02 2.565 ;
     RECT  2.16 2.835 142.02 3.105 ;
     RECT  2.16 3.375 142.02 3.645 ;
     RECT  2.16 3.915 142.02 4.185 ;
     RECT  2.16 4.455 142.02 4.725 ;
     RECT  2.16 4.995 142.02 5.265 ;
     RECT  2.16 5.535 142.02 5.805 ;
     RECT  2.16 6.075 142.02 6.345 ;
     RECT  2.16 6.615 142.02 6.885 ;
     RECT  2.16 7.155 142.02 7.425 ;
     RECT  2.16 7.695 142.02 7.965 ;
     RECT  2.16 8.235 142.02 8.505 ;
     RECT  2.16 8.775 142.02 9.045 ;
     RECT  2.16 9.315 142.02 9.585 ;
     RECT  2.16 9.855 142.02 10.125 ;
     RECT  2.16 10.395 142.02 10.665 ;
     RECT  2.16 10.935 142.02 11.205 ;
     RECT  2.16 11.475 142.02 11.745 ;
     RECT  2.16 12.015 142.02 12.285 ;
     RECT  2.16 12.555 142.02 12.825 ;
     RECT  2.16 13.095 142.02 13.365 ;
     RECT  2.16 13.635 142.02 13.905 ;
     RECT  2.16 14.175 142.02 14.445 ;
     RECT  2.16 14.715 142.02 14.985 ;
     RECT  2.16 15.255 142.02 15.525 ;
     RECT  2.16 15.795 142.02 16.065 ;
     RECT  2.16 16.335 142.02 16.605 ;
     RECT  2.16 16.875 142.02 17.145 ;
     RECT  2.16 17.415 142.02 17.685 ;
     RECT  2.16 17.955 142.02 18.225 ;
     RECT  2.16 18.495 142.02 18.765 ;
     RECT  2.16 19.035 142.02 19.305 ;
     RECT  2.16 19.575 142.02 19.845 ;
     RECT  2.16 20.115 142.02 20.385 ;
     RECT  2.16 20.655 142.02 20.925 ;
     RECT  2.16 21.195 142.02 21.465 ;
     RECT  2.16 21.735 142.02 22.005 ;
     RECT  2.16 22.275 142.02 22.545 ;
     RECT  2.16 22.815 142.02 23.085 ;
     RECT  2.16 23.355 142.02 23.625 ;
    LAYER M1 ;
     RECT  2.16 2.151 142.02 23.769 ;
    LAYER M2 ;
     RECT  0.427 6.696 0.463 6.714 ;
     RECT  0.463 6.426 0.499 6.714 ;
     RECT  0.499 6.39 0.535 6.714 ;
     RECT  0.499 23.4 0.535 23.418 ;
     RECT  0.391 7.506 1.111 7.524 ;
     RECT  0.535 23.4 1.147 23.616 ;
     RECT  1.147 21.096 1.247 21.114 ;
     RECT  1.147 23.4 1.247 23.814 ;
     RECT  1.327 2.232 1.399 2.25 ;
     RECT  1.111 7.506 1.399 7.956 ;
     RECT  0.463 22.356 1.399 22.374 ;
     RECT  1.327 0.036 1.427 0.054 ;
     RECT  1.399 22.356 1.471 22.644 ;
     RECT  1.247 23.4 1.471 23.724 ;
     RECT  1.363 18.036 1.615 18.054 ;
     RECT  1.435 18.936 1.615 18.954 ;
     RECT  1.147 19.926 1.651 19.944 ;
     RECT  1.615 18.036 1.687 18.954 ;
     RECT  1.615 5.202 1.723 5.22 ;
     RECT  0.535 6.156 1.723 6.714 ;
     RECT  1.435 3.456 1.795 3.474 ;
     RECT  1.687 18.036 1.903 19.062 ;
     RECT  1.651 19.854 1.903 19.944 ;
     RECT  1.471 22.356 1.903 23.724 ;
     RECT  1.795 3.42 2.083 3.474 ;
     RECT  2.011 4.23 2.083 4.248 ;
     RECT  1.399 2.232 2.16 2.286 ;
     RECT  2.083 3.42 2.16 4.248 ;
     RECT  1.723 5.202 2.16 6.714 ;
     RECT  1.399 7.506 2.16 8.064 ;
     RECT  1.903 18.036 2.16 19.944 ;
     RECT  1.903 21.978 2.16 23.724 ;
     RECT  2.16 2.151 2.299 23.769 ;
     RECT  2.299 2.151 2.371 23.922 ;
     RECT  2.371 1.728 2.615 23.922 ;
     RECT  2.587 0.108 2.695 0.126 ;
     RECT  2.695 0.036 2.795 0.126 ;
     RECT  4.027 0.036 4.127 0.054 ;
     RECT  2.615 1.728 4.271 23.769 ;
     RECT  4.271 2.106 4.531 23.769 ;
     RECT  4.531 2.106 4.603 23.814 ;
     RECT  4.603 2.106 5.071 23.958 ;
     RECT  5.071 1.728 5.099 23.958 ;
     RECT  5.099 1.728 5.531 23.886 ;
     RECT  4.027 25.056 5.567 25.074 ;
     RECT  5.531 1.728 5.675 23.814 ;
     RECT  5.575 0.036 6.143 0.054 ;
     RECT  5.675 1.8 6.215 23.769 ;
     RECT  6.215 2.151 6.511 23.769 ;
     RECT  6.511 2.151 7.699 23.814 ;
     RECT  8.131 0.036 8.447 0.054 ;
     RECT  7.699 2.151 8.519 23.922 ;
     RECT  6.331 25.056 8.555 25.074 ;
     RECT  8.519 2.151 9.283 23.886 ;
     RECT  8.527 0.576 9.383 0.594 ;
     RECT  9.391 25.056 9.527 25.074 ;
     RECT  9.283 2.151 10.147 23.922 ;
     RECT  10.147 2.151 10.643 23.958 ;
     RECT  11.227 25.056 11.803 25.074 ;
     RECT  11.803 24.984 11.939 25.074 ;
     RECT  10.643 2.151 11.947 23.922 ;
     RECT  11.939 25.056 12.551 25.074 ;
     RECT  11.947 2.034 13.487 23.922 ;
     RECT  13.531 25.866 13.631 25.884 ;
     RECT  13.487 2.106 14.395 23.922 ;
     RECT  14.395 1.728 14.531 23.922 ;
     RECT  14.531 2.151 14.819 23.922 ;
     RECT  13.531 25.056 14.963 25.074 ;
     RECT  14.819 2.151 15.619 23.814 ;
     RECT  16.879 0.036 16.979 0.054 ;
     RECT  17.275 25.056 17.519 25.074 ;
     RECT  18.499 0.036 18.599 0.054 ;
     RECT  18.499 25.056 18.779 25.074 ;
     RECT  15.619 2.151 18.895 23.85 ;
     RECT  18.895 2.151 19.535 23.922 ;
     RECT  21.091 25.866 21.443 25.884 ;
     RECT  22.747 25.866 22.811 25.884 ;
     RECT  23.611 25.866 23.819 25.884 ;
     RECT  19.535 2.151 32.611 23.769 ;
     RECT  32.611 2.151 33.215 23.814 ;
     RECT  35.023 25.866 35.159 25.884 ;
     RECT  38.299 25.866 38.507 25.884 ;
     RECT  42.403 25.866 43.295 25.884 ;
     RECT  33.215 2.151 45.679 23.769 ;
     RECT  45.679 1.728 45.779 23.922 ;
     RECT  47.299 25.866 47.687 25.884 ;
     RECT  45.779 2.151 47.983 23.769 ;
     RECT  47.983 1.728 48.191 23.769 ;
     RECT  48.191 2.151 51.223 23.769 ;
     RECT  51.223 2.151 52.043 23.814 ;
     RECT  52.043 2.151 55.327 23.769 ;
     RECT  55.327 1.728 55.499 23.769 ;
     RECT  55.499 2.151 58.819 23.769 ;
     RECT  58.819 1.728 59.027 23.769 ;
     RECT  59.027 2.151 61.771 23.769 ;
     RECT  61.771 0.036 61.943 0.054 ;
     RECT  61.771 2.151 61.943 23.85 ;
     RECT  63.067 0.036 63.167 0.054 ;
     RECT  63.931 25.056 64.211 25.074 ;
     RECT  61.943 2.151 65.551 23.769 ;
     RECT  65.551 2.151 65.623 23.814 ;
     RECT  65.947 0.036 66.047 0.054 ;
     RECT  65.623 2.151 67.883 23.85 ;
     RECT  69.187 24.561 69.467 24.579 ;
     RECT  67.883 2.151 69.943 23.769 ;
     RECT  69.943 2.151 70.871 23.886 ;
     RECT  72.859 0.036 72.959 0.054 ;
     RECT  70.871 2.151 74.947 23.769 ;
     RECT  74.947 2.151 75.047 23.814 ;
     RECT  75.047 2.151 76.963 23.769 ;
     RECT  76.963 2.151 77.099 23.814 ;
     RECT  77.099 2.151 78.187 23.769 ;
     RECT  78.151 0.036 78.251 0.054 ;
     RECT  78.187 2.151 78.575 23.886 ;
     RECT  78.575 2.151 79.115 23.814 ;
     RECT  79.115 2.151 80.347 23.769 ;
     RECT  80.347 2.151 80.699 23.994 ;
     RECT  80.699 2.151 82.363 23.769 ;
     RECT  82.363 2.151 82.679 23.922 ;
     RECT  83.047 0.036 83.147 0.054 ;
     RECT  82.679 2.151 83.615 23.814 ;
     RECT  84.739 0.036 84.839 0.054 ;
     RECT  85.927 0.036 86.027 0.054 ;
     RECT  83.615 2.151 88.771 23.769 ;
     RECT  88.771 0.036 88.907 0.054 ;
     RECT  88.771 2.151 88.907 23.922 ;
     RECT  88.907 2.151 89.375 23.814 ;
     RECT  89.375 2.151 91.759 23.769 ;
     RECT  91.759 2.151 92.443 23.814 ;
     RECT  92.443 2.151 94.091 23.886 ;
     RECT  94.243 0.036 94.379 0.054 ;
     RECT  93.775 25.056 95.711 25.074 ;
     RECT  94.091 2.151 96.511 23.769 ;
     RECT  96.511 2.151 96.655 23.814 ;
     RECT  96.655 2.151 97.051 23.85 ;
     RECT  97.051 2.151 97.799 23.886 ;
     RECT  97.799 2.151 98.563 23.769 ;
     RECT  98.563 2.151 98.671 23.814 ;
     RECT  98.671 2.151 98.771 23.85 ;
     RECT  98.771 2.151 99.095 23.814 ;
     RECT  99.931 0.036 100.031 0.054 ;
     RECT  99.095 2.151 100.795 23.769 ;
     RECT  100.795 2.151 101.003 23.814 ;
     RECT  102.019 25.866 102.155 25.884 ;
     RECT  101.003 2.151 105.295 23.769 ;
     RECT  105.295 2.151 105.431 23.814 ;
     RECT  105.295 0.036 105.791 0.054 ;
     RECT  105.431 2.151 110.587 23.769 ;
     RECT  110.587 2.151 111.451 23.814 ;
     RECT  111.451 2.151 111.587 23.922 ;
     RECT  111.587 2.151 115.951 23.769 ;
     RECT  115.951 2.151 116.735 23.814 ;
     RECT  118.723 25.866 118.823 25.884 ;
     RECT  116.735 2.151 119.803 23.769 ;
     RECT  119.803 2.151 120.011 23.922 ;
     RECT  120.011 2.151 121.171 23.769 ;
     RECT  121.171 2.151 121.271 23.85 ;
     RECT  121.243 0.036 121.379 0.054 ;
     RECT  122.863 0.036 122.963 0.054 ;
     RECT  121.271 2.151 123.727 23.769 ;
     RECT  123.727 2.151 124.043 23.814 ;
     RECT  124.043 2.151 124.447 23.769 ;
     RECT  124.447 1.764 124.583 23.769 ;
     RECT  124.583 2.151 125.347 23.769 ;
     RECT  125.347 2.151 126.607 23.814 ;
     RECT  126.535 0.036 126.635 0.054 ;
     RECT  126.607 2.151 127.003 23.85 ;
     RECT  127.003 2.151 127.103 23.922 ;
     RECT  127.103 2.151 127.175 23.814 ;
     RECT  127.175 2.151 128.407 23.769 ;
     RECT  128.407 2.151 128.623 23.814 ;
     RECT  128.623 2.151 130.739 23.886 ;
     RECT  130.739 2.151 131.027 23.814 ;
     RECT  133.231 25.866 133.367 25.884 ;
     RECT  131.027 2.151 137.083 23.769 ;
     RECT  137.083 2.151 137.255 23.814 ;
     RECT  137.255 2.151 142.02 23.769 ;
     RECT  142.02 2.808 142.295 3.132 ;
     RECT  142.02 23.094 142.295 23.112 ;
     RECT  142.295 3.114 143.051 3.132 ;
     RECT  142.02 21.474 143.051 21.492 ;
    LAYER M3 ;
     RECT  1.152 0.012 20.358 0.077 ;
     RECT  59.616 0.012 131.13 0.077 ;
     RECT  44.928 0.012 44.946 0.091 ;
     RECT  45.684 0.012 45.702 0.091 ;
     RECT  51.444 0.012 51.462 0.091 ;
     RECT  52.2 0.012 52.218 0.091 ;
     RECT  1.152 0.077 18.594 0.317 ;
     RECT  1.152 0.317 11.61 0.557 ;
     RECT  12.672 0.317 18.594 0.557 ;
     RECT  59.616 0.077 90.162 0.557 ;
     RECT  114.696 0.077 131.13 0.557 ;
     RECT  36.648 0.012 36.666 0.571 ;
     RECT  37.512 0.012 37.53 0.571 ;
     RECT  40.788 0.012 40.806 0.571 ;
     RECT  41.544 0.012 41.562 0.571 ;
     RECT  44.064 0.012 44.082 0.571 ;
     RECT  44.928 0.091 45.702 0.571 ;
     RECT  46.548 0.012 46.566 0.571 ;
     RECT  47.304 0.012 47.322 0.571 ;
     RECT  8.424 0.557 11.61 0.599 ;
     RECT  140.832 0.012 141.498 1.147 ;
     RECT  142.272 0.012 142.29 1.147 ;
     RECT  8.424 0.599 8.442 1.723 ;
     RECT  9.216 0.599 11.61 1.723 ;
     RECT  12.672 0.557 12.87 1.723 ;
     RECT  13.608 0.557 18.594 1.723 ;
     RECT  19.368 0.077 20.358 1.723 ;
     RECT  21.096 0.012 21.114 1.723 ;
     RECT  21.96 0.012 21.978 1.723 ;
     RECT  22.752 0.012 22.77 1.723 ;
     RECT  23.616 0.012 23.634 1.723 ;
     RECT  24.372 0.012 24.39 1.723 ;
     RECT  25.236 0.012 25.254 1.723 ;
     RECT  25.992 0.012 26.01 1.723 ;
     RECT  26.856 0.012 26.874 1.723 ;
     RECT  27.648 0.012 27.666 1.723 ;
     RECT  28.512 0.012 28.53 1.723 ;
     RECT  29.376 0.012 29.394 1.723 ;
     RECT  30.132 0.012 30.15 1.723 ;
     RECT  30.996 0.012 31.014 1.723 ;
     RECT  31.752 0.012 31.77 1.723 ;
     RECT  32.616 0.012 32.634 1.723 ;
     RECT  33.408 0.012 33.426 1.723 ;
     RECT  34.272 0.012 34.29 1.723 ;
     RECT  35.028 0.012 35.046 1.723 ;
     RECT  35.892 0.012 35.91 1.723 ;
     RECT  36.648 0.571 37.53 1.723 ;
     RECT  38.304 0.012 38.322 1.723 ;
     RECT  39.168 0.012 39.186 1.723 ;
     RECT  39.924 0.012 39.942 1.723 ;
     RECT  40.788 0.571 41.562 1.723 ;
     RECT  42.408 0.012 42.426 1.723 ;
     RECT  43.272 0.012 43.29 1.723 ;
     RECT  44.064 0.571 45.702 1.723 ;
     RECT  46.548 0.571 47.322 1.723 ;
     RECT  48.168 0.012 48.186 1.723 ;
     RECT  48.96 0.012 48.978 1.723 ;
     RECT  49.824 0.012 49.842 1.723 ;
     RECT  50.58 0.012 50.598 1.723 ;
     RECT  51.444 0.091 52.218 1.723 ;
     RECT  53.064 0.012 53.082 1.723 ;
     RECT  53.856 0.012 53.874 1.723 ;
     RECT  54.72 0.012 54.738 1.723 ;
     RECT  55.476 0.012 55.494 1.723 ;
     RECT  56.34 0.012 56.358 1.723 ;
     RECT  57.204 0.012 57.222 1.723 ;
     RECT  57.96 0.012 57.978 1.723 ;
     RECT  58.824 0.012 58.842 1.723 ;
     RECT  59.616 0.557 69.714 1.723 ;
     RECT  70.452 0.557 90.162 1.723 ;
     RECT  90.9 0.077 113.85 1.723 ;
     RECT  114.696 0.557 114.714 1.723 ;
     RECT  115.488 0.557 131.13 1.723 ;
     RECT  131.904 0.012 132.57 1.723 ;
     RECT  133.344 0.012 133.362 1.723 ;
     RECT  134.1 0.012 134.118 1.723 ;
     RECT  134.856 0.012 135.558 1.723 ;
     RECT  136.296 0.012 136.314 1.723 ;
     RECT  137.088 0.012 137.106 1.723 ;
     RECT  137.844 0.012 138.546 1.723 ;
     RECT  139.284 0.012 139.302 1.723 ;
     RECT  140.04 0.012 140.058 1.723 ;
     RECT  140.832 1.147 142.29 1.723 ;
     RECT  1.152 0.557 7.11 2.143 ;
     RECT  8.424 1.723 142.29 2.143 ;
     RECT  1.152 2.143 142.29 2.489 ;
     RECT  42.624 2.489 142.29 2.831 ;
     RECT  143.028 0.012 143.046 3.137 ;
     RECT  1.152 2.489 41.742 3.307 ;
     RECT  42.624 2.831 141.966 3.307 ;
     RECT  1.152 3.307 141.966 3.371 ;
     RECT  1.152 3.371 141.714 3.569 ;
     RECT  1.152 3.569 49.518 3.713 ;
     RECT  1.152 3.713 49.41 3.92 ;
     RECT  1.152 3.92 44.766 4.109 ;
     RECT  45.615 3.92 49.41 4.109 ;
     RECT  1.152 4.109 41.238 4.145 ;
     RECT  50.292 3.569 141.714 4.379 ;
     RECT  56.016 4.379 141.714 4.531 ;
     RECT  56.016 4.531 141.786 4.541 ;
     RECT  1.152 4.145 33.138 4.559 ;
     RECT  59.148 4.541 141.786 4.649 ;
     RECT  50.292 4.379 54.954 4.685 ;
     RECT  106.056 4.649 141.786 4.801 ;
     RECT  59.148 4.649 64.026 4.877 ;
     RECT  64.8 4.649 105.297 4.919 ;
     RECT  64.8 4.919 91.314 4.955 ;
     RECT  106.056 4.801 141.858 5.071 ;
     RECT  64.8 4.955 91.098 5.117 ;
     RECT  92.196 4.919 105.297 5.189 ;
     RECT  64.8 5.117 73.206 5.645 ;
     RECT  1.152 4.559 27.09 5.765 ;
     RECT  1.152 5.765 1.242 6.151 ;
     RECT  0.54 6.151 1.242 6.377 ;
     RECT  0.54 6.377 0.558 6.385 ;
     RECT  2.16 5.765 27.09 6.413 ;
     RECT  0.504 6.385 0.558 6.421 ;
     RECT  0.468 6.421 0.558 6.691 ;
     RECT  2.268 6.413 27.09 7.373 ;
     RECT  0.432 6.691 0.558 7.501 ;
     RECT  1.512 6.583 1.53 7.735 ;
     RECT  2.268 7.373 14.706 7.735 ;
     RECT  1.512 7.735 14.706 7.771 ;
     RECT  0.396 7.501 0.558 7.933 ;
     RECT  1.476 7.771 14.706 7.933 ;
     RECT  0.396 7.933 14.706 8.429 ;
     RECT  0.396 8.429 12.006 8.969 ;
     RECT  10.836 8.969 12.006 9.005 ;
     RECT  0.396 8.969 5.958 9.101 ;
     RECT  6.732 8.969 9.738 9.149 ;
     RECT  6.732 9.149 8.91 9.239 ;
     RECT  6.732 9.239 8.838 9.293 ;
     RECT  0.396 9.101 5.382 9.437 ;
     RECT  9.684 9.149 9.738 9.437 ;
     RECT  11.412 9.005 12.006 10.301 ;
     RECT  11.448 10.301 12.006 10.397 ;
     RECT  6.732 9.293 8.097 10.637 ;
     RECT  13.104 8.429 14.706 10.859 ;
     RECT  0.396 9.437 5.094 11.435 ;
     RECT  0.396 11.435 4.986 11.939 ;
     RECT  0.396 11.939 4.842 11.975 ;
     RECT  59.148 4.877 63.99 13.667 ;
     RECT  8.82 9.293 8.838 14.861 ;
     RECT  9.684 9.437 9.702 14.861 ;
     RECT  6.732 10.637 6.75 17.581 ;
     RECT  6.192 17.581 6.75 17.617 ;
     RECT  0.396 11.975 4.662 18.571 ;
     RECT  0.396 18.571 4.878 19.039 ;
     RECT  0.396 19.039 5.058 19.075 ;
     RECT  6.084 17.617 6.75 19.075 ;
     RECT  0.396 19.075 5.238 19.111 ;
     RECT  6.012 19.075 6.75 19.111 ;
     RECT  0.396 19.111 6.75 19.237 ;
     RECT  0.396 19.237 6.786 19.273 ;
     RECT  7.815 10.637 8.097 19.273 ;
     RECT  11.988 10.397 12.006 19.345 ;
     RECT  9.18 19.345 9.198 19.381 ;
     RECT  10.116 19.345 10.458 19.381 ;
     RECT  9.18 19.381 10.458 19.471 ;
     RECT  11.304 19.345 12.186 19.471 ;
     RECT  13.176 10.859 14.706 19.471 ;
     RECT  9.18 19.471 10.494 19.507 ;
     RECT  11.304 19.471 14.706 19.507 ;
     RECT  0.396 19.273 8.097 19.543 ;
     RECT  9.18 19.507 14.706 19.543 ;
     RECT  0.396 19.543 14.706 20.965 ;
     RECT  0.396 20.965 14.778 21.001 ;
     RECT  15.516 7.373 27.09 21.001 ;
     RECT  92.196 5.189 96.534 21.091 ;
     RECT  64.8 5.645 67.497 21.115 ;
     RECT  68.22 5.645 73.206 21.115 ;
     RECT  97.272 5.189 105.297 21.235 ;
     RECT  106.056 5.071 141.93 21.235 ;
     RECT  64.8 21.115 73.206 21.271 ;
     RECT  74.088 5.117 91.098 21.271 ;
     RECT  91.944 21.091 96.534 21.469 ;
     RECT  97.272 21.235 141.93 21.469 ;
     RECT  64.8 21.271 91.098 21.541 ;
     RECT  91.944 21.469 141.93 21.541 ;
     RECT  91.944 21.541 141.966 21.581 ;
     RECT  64.692 21.541 91.206 21.631 ;
     RECT  91.944 21.581 141.93 21.631 ;
     RECT  28.224 4.559 33.138 21.667 ;
     RECT  34.02 4.145 41.238 21.667 ;
     RECT  59.148 13.667 63.702 21.667 ;
     RECT  64.692 21.631 141.93 21.667 ;
     RECT  0.396 21.001 27.09 22.253 ;
     RECT  56.016 4.541 58.41 22.351 ;
     RECT  59.148 21.667 141.93 22.351 ;
     RECT  28.224 21.667 41.238 22.441 ;
     RECT  42.12 4.109 44.766 22.441 ;
     RECT  50.292 4.685 52.614 22.477 ;
     RECT  53.352 4.685 54.954 22.477 ;
     RECT  0.432 22.253 27.09 22.541 ;
     RECT  28.224 22.441 44.766 22.585 ;
     RECT  45.615 4.109 49.266 22.585 ;
     RECT  50.292 22.477 54.954 22.585 ;
     RECT  0.504 22.541 27.09 22.621 ;
     RECT  28.224 22.585 54.954 22.621 ;
     RECT  56.016 22.351 141.93 22.621 ;
     RECT  0.504 22.621 141.93 23.089 ;
     RECT  0.504 23.089 142.29 23.423 ;
     RECT  0.54 23.423 142.29 23.549 ;
     RECT  0.54 23.549 27.666 23.621 ;
     RECT  28.476 23.549 121.305 23.621 ;
     RECT  122.112 23.549 138.546 23.621 ;
     RECT  1.152 23.621 27.666 23.657 ;
     RECT  28.476 23.621 36.774 23.657 ;
     RECT  37.512 23.621 121.305 23.657 ;
     RECT  21.204 23.657 27.666 23.729 ;
     RECT  28.476 23.657 36.666 23.729 ;
     RECT  37.512 23.657 58.842 23.729 ;
     RECT  139.284 23.549 142.29 23.729 ;
     RECT  37.512 23.729 53.874 23.777 ;
     RECT  59.616 23.657 121.305 23.777 ;
     RECT  21.42 23.729 25.254 23.933 ;
     RECT  25.992 23.729 27.666 23.933 ;
     RECT  28.476 23.729 31.014 23.933 ;
     RECT  37.512 23.777 39.942 23.933 ;
     RECT  40.788 23.777 53.874 23.933 ;
     RECT  54.72 23.729 57.222 23.933 ;
     RECT  57.96 23.729 58.842 23.933 ;
     RECT  122.112 23.621 134.118 23.933 ;
     RECT  134.856 23.621 138.546 23.933 ;
     RECT  29.376 23.933 31.014 23.981 ;
     RECT  31.752 23.729 36.666 24.509 ;
     RECT  40.788 23.933 41.562 24.509 ;
     RECT  139.284 23.729 141.498 25.085 ;
     RECT  44.064 23.933 44.946 25.133 ;
     RECT  45.684 23.933 53.082 25.133 ;
     RECT  139.284 25.085 140.058 25.133 ;
     RECT  59.616 23.777 121.266 25.675 ;
     RECT  122.112 23.933 131.13 25.675 ;
     RECT  23.796 23.933 24.498 25.805 ;
     RECT  25.992 23.933 26.874 25.805 ;
     RECT  28.476 23.933 28.53 25.805 ;
     RECT  29.376 23.981 30.15 25.805 ;
     RECT  32.616 24.509 36.666 25.805 ;
     RECT  46.548 25.133 50.598 25.805 ;
     RECT  51.444 25.133 53.082 25.805 ;
     RECT  55.476 23.933 57.222 25.805 ;
     RECT  131.904 23.933 134.118 25.805 ;
     RECT  137.088 23.933 138.546 25.805 ;
     RECT  21.42 23.933 21.978 25.861 ;
     RECT  22.788 23.933 22.806 25.861 ;
     RECT  23.796 25.805 24.39 25.861 ;
     RECT  38.484 23.933 39.186 25.861 ;
     RECT  42.588 23.933 43.218 25.861 ;
     RECT  21.096 25.861 21.978 25.889 ;
     RECT  22.752 25.861 22.806 25.889 ;
     RECT  23.616 25.861 24.39 25.889 ;
     RECT  35.028 25.805 35.154 25.889 ;
     RECT  38.304 25.861 39.186 25.889 ;
     RECT  42.408 25.861 43.29 25.889 ;
     RECT  47.304 25.805 48.186 25.889 ;
     RECT  131.904 25.805 133.362 25.889 ;
     RECT  1.152 23.657 20.358 25.901 ;
     RECT  21.096 25.889 21.114 25.901 ;
     RECT  21.96 25.889 21.978 25.901 ;
     RECT  22.752 25.889 22.77 25.901 ;
     RECT  23.616 25.889 23.634 25.901 ;
     RECT  24.372 25.889 24.39 25.901 ;
     RECT  25.236 23.933 25.254 25.901 ;
     RECT  25.992 25.805 26.01 25.901 ;
     RECT  26.856 25.805 26.874 25.901 ;
     RECT  27.648 23.933 27.666 25.901 ;
     RECT  28.512 25.805 28.53 25.901 ;
     RECT  29.376 25.805 29.394 25.901 ;
     RECT  30.132 25.805 30.15 25.901 ;
     RECT  30.996 23.981 31.014 25.901 ;
     RECT  31.752 24.509 31.77 25.901 ;
     RECT  32.616 25.805 32.634 25.901 ;
     RECT  33.408 25.805 33.426 25.901 ;
     RECT  34.272 25.805 34.29 25.901 ;
     RECT  35.028 25.889 35.046 25.901 ;
     RECT  35.892 25.805 35.91 25.901 ;
     RECT  36.648 25.805 36.666 25.901 ;
     RECT  37.512 23.933 37.53 25.901 ;
     RECT  38.304 25.889 38.322 25.901 ;
     RECT  39.168 25.889 39.186 25.901 ;
     RECT  39.924 23.933 39.942 25.901 ;
     RECT  40.788 24.509 40.806 25.901 ;
     RECT  41.544 24.509 41.562 25.901 ;
     RECT  42.408 25.889 42.426 25.901 ;
     RECT  43.272 25.889 43.29 25.901 ;
     RECT  44.064 25.133 44.082 25.901 ;
     RECT  44.928 25.133 44.946 25.901 ;
     RECT  45.684 25.133 45.702 25.901 ;
     RECT  46.548 25.805 46.566 25.901 ;
     RECT  47.304 25.889 47.322 25.901 ;
     RECT  48.168 25.889 48.186 25.901 ;
     RECT  48.96 25.805 48.978 25.901 ;
     RECT  49.824 25.805 49.842 25.901 ;
     RECT  50.58 25.805 50.598 25.901 ;
     RECT  51.444 25.805 51.462 25.901 ;
     RECT  52.2 25.805 52.218 25.901 ;
     RECT  53.064 25.805 53.082 25.901 ;
     RECT  53.856 23.933 53.874 25.901 ;
     RECT  54.72 23.933 54.738 25.901 ;
     RECT  55.476 25.805 55.494 25.901 ;
     RECT  56.34 25.805 56.358 25.901 ;
     RECT  57.204 25.805 57.222 25.901 ;
     RECT  57.96 23.933 57.978 25.901 ;
     RECT  58.824 23.933 58.842 25.901 ;
     RECT  59.616 25.675 131.13 25.901 ;
     RECT  131.904 25.889 132.57 25.901 ;
     RECT  133.344 25.889 133.362 25.901 ;
     RECT  134.1 25.805 134.118 25.901 ;
     RECT  134.856 23.933 135.558 25.901 ;
     RECT  136.296 23.933 136.314 25.901 ;
     RECT  137.088 25.805 137.106 25.901 ;
     RECT  137.844 25.805 138.546 25.901 ;
     RECT  139.284 25.133 139.302 25.901 ;
     RECT  140.04 25.133 140.058 25.901 ;
     RECT  140.832 25.085 141.498 25.901 ;
     RECT  142.272 23.729 142.29 25.901 ;
     RECT  143.028 21.469 143.046 25.901 ;
    LAYER M4 ;
     RECT  0.06 13.008 0.227 13.032 ;
     RECT  0.385 22.224 0.421 22.248 ;
     RECT  0.421 22.224 0.997 22.536 ;
     RECT  0.997 22.224 1.045 23.304 ;
     RECT  0.997 6.096 1.189 6.12 ;
     RECT  1.093 2.256 1.277 2.28 ;
     RECT  1.093 20.4 1.285 20.424 ;
     RECT  1.277 1.728 1.361 2.28 ;
     RECT  0.181 7.44 1.381 7.464 ;
     RECT  1.381 0.576 1.429 0.6 ;
     RECT  1.333 9.072 1.429 9.096 ;
     RECT  1.045 22.224 1.429 23.592 ;
     RECT  1.045 4.656 1.477 4.68 ;
     RECT  1.285 20.304 1.477 20.424 ;
     RECT  1.189 6.048 1.525 6.12 ;
     RECT  1.429 22.224 1.525 23.64 ;
     RECT  1.477 4.128 1.573 4.68 ;
     RECT  1.525 5.856 1.573 6.12 ;
     RECT  1.381 7.344 1.573 7.464 ;
     RECT  1.525 21.984 1.573 23.64 ;
     RECT  1.573 5.856 1.621 7.464 ;
     RECT  1.573 4.128 1.669 4.728 ;
     RECT  1.477 19.968 1.669 20.424 ;
     RECT  1.669 3.84 1.765 4.728 ;
     RECT  1.669 19.296 1.765 20.424 ;
     RECT  1.573 21.984 1.813 23.688 ;
     RECT  1.361 2.256 1.861 2.28 ;
     RECT  1.765 3.84 1.861 4.776 ;
     RECT  1.861 2.256 1.909 4.776 ;
     RECT  1.621 5.808 1.909 7.464 ;
     RECT  1.765 19.104 1.925 20.424 ;
     RECT  1.813 21.456 1.925 23.688 ;
     RECT  1.429 8.496 2.005 9.096 ;
     RECT  1.909 2.256 2.041 7.464 ;
     RECT  2.005 8.496 2.041 9.384 ;
     RECT  1.925 19.104 2.149 23.688 ;
     RECT  2.149 19.104 2.293 23.928 ;
     RECT  1.429 0.48 2.329 0.6 ;
     RECT  2.293 18.768 2.365 23.928 ;
     RECT  2.041 2.256 2.408 9.384 ;
     RECT  1.813 10.608 2.408 10.632 ;
     RECT  0.06 11.952 2.408 11.976 ;
     RECT  2.365 18.72 2.408 23.928 ;
     RECT  2.408 2.148 2.704 23.928 ;
     RECT  2.704 2.148 2.725 9.384 ;
     RECT  2.704 18.48 2.819 23.928 ;
     RECT  1.765 25.776 2.867 25.8 ;
     RECT  2.329 0.096 3.049 0.6 ;
     RECT  2.819 18.48 3.107 23.832 ;
     RECT  2.725 2.016 3.205 9.384 ;
     RECT  3.107 18.816 3.413 23.832 ;
     RECT  2.704 10.608 3.635 12.024 ;
     RECT  3.049 0.048 3.683 0.6 ;
     RECT  3.635 10.608 3.683 11.88 ;
     RECT  2.704 13.68 3.923 13.704 ;
     RECT  3.413 18.96 3.989 23.832 ;
     RECT  3.683 0.576 4.025 0.6 ;
     RECT  3.989 19.2 4.061 23.832 ;
     RECT  3.205 1.728 4.213 9.384 ;
     RECT  3.683 10.608 4.213 11.4 ;
     RECT  4.213 1.728 4.529 11.4 ;
     RECT  4.061 19.344 4.529 23.832 ;
     RECT  4.117 14.784 4.565 14.808 ;
     RECT  4.844 0.144 5.029 0.168 ;
     RECT  3.445 25.824 5.267 25.848 ;
     RECT  5.029 0.144 5.285 0.552 ;
     RECT  4.529 19.632 5.315 23.832 ;
     RECT  4.529 1.728 5.393 9.432 ;
     RECT  5.315 19.824 5.897 23.832 ;
     RECT  5.897 19.968 5.965 23.832 ;
     RECT  5.393 1.728 5.969 9.096 ;
     RECT  6.037 25.104 6.149 25.704 ;
     RECT  5.969 1.728 6.179 8.904 ;
     RECT  4.501 17.616 6.221 17.64 ;
     RECT  6.149 25.584 6.275 25.704 ;
     RECT  6.275 25.68 6.419 25.704 ;
     RECT  6.179 1.728 6.473 8.76 ;
     RECT  6.473 1.776 6.545 8.76 ;
     RECT  6.073 18.768 6.761 18.792 ;
     RECT  5.285 0.144 6.805 0.168 ;
     RECT  6.545 2.208 6.829 8.76 ;
     RECT  5.965 19.968 7.081 23.928 ;
     RECT  7.081 19.968 7.187 24.504 ;
     RECT  6.829 2.256 7.225 8.76 ;
     RECT  6.805 0.144 7.525 0.36 ;
     RECT  7.525 0.144 7.669 0.504 ;
     RECT  7.225 2.256 7.808 9.288 ;
     RECT  4.529 10.608 7.808 11.4 ;
     RECT  7.187 19.968 7.808 23.928 ;
     RECT  7.669 0.144 8.005 0.552 ;
     RECT  7.808 2.148 8.104 23.928 ;
     RECT  7.573 25.728 8.197 25.752 ;
     RECT  8.104 20.064 8.339 23.928 ;
     RECT  8.197 25.584 8.341 25.752 ;
     RECT  8.005 0.096 8.387 0.552 ;
     RECT  8.104 2.148 8.597 9.288 ;
     RECT  8.341 25.488 8.675 25.752 ;
     RECT  8.597 2.148 8.677 9.144 ;
     RECT  8.675 25.584 8.677 25.752 ;
     RECT  8.677 25.584 8.701 25.8 ;
     RECT  8.701 25.584 8.723 25.848 ;
     RECT  8.387 0.144 8.741 0.552 ;
     RECT  8.677 1.728 8.813 9.144 ;
     RECT  8.339 20.112 9.349 23.928 ;
     RECT  8.741 0.144 9.385 0.168 ;
     RECT  8.723 25.728 9.395 25.848 ;
     RECT  8.813 2.208 9.709 9.144 ;
     RECT  9.349 19.92 9.925 23.928 ;
     RECT  9.925 19.68 10.253 23.928 ;
     RECT  8.104 14.832 10.259 14.856 ;
     RECT  9.709 2.208 10.501 9.432 ;
     RECT  9.395 25.728 10.595 25.752 ;
     RECT  10.501 1.728 10.613 9.432 ;
     RECT  10.613 2.208 11.401 9.432 ;
     RECT  11.401 2.208 11.437 10.296 ;
     RECT  9.385 0.048 11.459 0.168 ;
     RECT  10.253 19.872 11.603 23.928 ;
     RECT  11.437 2.208 11.651 10.392 ;
     RECT  11.651 10.272 11.699 10.392 ;
     RECT  11.459 0.144 11.701 0.168 ;
     RECT  11.603 19.872 11.729 23.736 ;
     RECT  10.988 25.056 11.749 25.08 ;
     RECT  11.749 25.056 11.891 25.8 ;
     RECT  11.701 0.144 11.948 0.216 ;
     RECT  11.948 0.144 12.035 0.312 ;
     RECT  11.729 19.968 12.083 23.736 ;
     RECT  11.651 2.208 12.133 9.096 ;
     RECT  11.699 10.272 12.227 10.296 ;
     RECT  12.133 1.728 12.305 9.096 ;
     RECT  12.035 0.144 12.515 0.168 ;
     RECT  11.891 25.056 12.515 25.08 ;
     RECT  12.083 20.304 12.709 23.736 ;
     RECT  12.305 1.776 13.208 9.096 ;
     RECT  12.037 17.136 13.208 17.16 ;
     RECT  12.709 20.304 13.208 23.88 ;
     RECT  13.093 0.528 13.277 0.552 ;
     RECT  13.208 1.776 13.345 23.88 ;
     RECT  13.345 1.728 13.381 23.88 ;
     RECT  13.381 1.728 13.504 23.976 ;
     RECT  13.504 20.64 13.565 23.976 ;
     RECT  13.565 20.64 13.601 23.928 ;
     RECT  13.504 1.728 13.715 9 ;
     RECT  13.715 8.976 13.763 9 ;
     RECT  13.601 21.12 14.041 23.928 ;
     RECT  14.041 21.168 14.069 23.928 ;
     RECT  13.715 1.728 14.105 7.944 ;
     RECT  14.105 2.16 14.141 7.944 ;
     RECT  14.141 2.16 14.15 7.8 ;
     RECT  14.069 21.408 14.177 23.928 ;
     RECT  14.177 21.408 14.249 23.88 ;
     RECT  14.249 21.504 14.645 23.88 ;
     RECT  14.15 2.208 14.681 7.8 ;
     RECT  14.645 21.552 14.825 23.88 ;
     RECT  15.013 25.776 15.149 25.8 ;
     RECT  14.825 21.936 15.185 23.88 ;
     RECT  15.185 22.224 15.251 23.88 ;
     RECT  14.681 2.208 15.292 7.704 ;
     RECT  15.251 22.272 15.293 23.88 ;
     RECT  15.293 22.464 15.401 23.88 ;
     RECT  15.401 23.328 15.493 23.88 ;
     RECT  15.292 2.208 15.509 6.168 ;
     RECT  15.469 1.152 15.553 1.176 ;
     RECT  15.493 23.328 15.617 23.976 ;
     RECT  15.509 4.512 15.653 6.168 ;
     RECT  15.617 23.328 15.653 23.4 ;
     RECT  15.509 2.208 15.857 3.336 ;
     RECT  15.829 21.12 15.913 21.144 ;
     RECT  15.857 1.728 15.923 3.336 ;
     RECT  15.653 23.376 15.977 23.4 ;
     RECT  15.923 1.728 16.013 2.712 ;
     RECT  16.261 25.776 16.409 25.8 ;
     RECT  15.292 7.152 16.595 7.704 ;
     RECT  15.653 5.04 16.733 6.168 ;
     RECT  16.585 3.984 16.765 4.008 ;
     RECT  16.733 5.04 16.765 5.16 ;
     RECT  16.733 6.144 16.877 6.168 ;
     RECT  16.765 3.984 17.017 5.16 ;
     RECT  16.645 23.424 17.085 23.448 ;
     RECT  16.013 1.728 17.405 2.232 ;
     RECT  17.405 1.728 17.449 2.808 ;
     RECT  17.017 3.888 17.453 5.16 ;
     RECT  17.449 1.728 17.641 2.904 ;
     RECT  17.509 21.648 18.169 21.672 ;
     RECT  17.893 25.056 18.209 25.08 ;
     RECT  18.169 21.648 18.469 22.296 ;
     RECT  18.469 21.504 18.493 22.296 ;
     RECT  17.125 23.376 18.493 23.4 ;
     RECT  18.373 24.528 18.497 24.552 ;
     RECT  17.641 1.728 18.608 1.752 ;
     RECT  17.641 2.88 18.608 2.904 ;
     RECT  17.453 3.984 18.608 5.16 ;
     RECT  16.595 7.68 18.608 7.704 ;
     RECT  18.493 21.504 18.608 23.4 ;
     RECT  18.469 25.776 18.803 25.8 ;
     RECT  18.608 1.728 18.904 23.928 ;
     RECT  18.904 22.224 19.001 22.824 ;
     RECT  18.889 0.048 19.043 0.072 ;
     RECT  18.904 4.368 19.043 5.4 ;
     RECT  19.001 22.272 19.043 22.824 ;
     RECT  18.904 1.728 19.117 2.28 ;
     RECT  19.043 22.272 19.253 22.296 ;
     RECT  19.043 4.368 19.613 5.16 ;
     RECT  18.904 23.904 19.649 23.928 ;
     RECT  20.005 22.176 20.677 22.2 ;
     RECT  20.677 22.176 21.125 22.776 ;
     RECT  20.509 3.312 21.625 3.336 ;
     RECT  19.613 4.368 21.625 4.536 ;
     RECT  21.625 3.312 21.665 4.536 ;
     RECT  21.125 22.656 21.881 22.776 ;
     RECT  21.665 3.408 22.097 4.536 ;
     RECT  21.881 22.656 22.565 22.68 ;
     RECT  22.405 23.904 23.357 23.928 ;
     RECT  22.097 3.84 23.569 4.536 ;
     RECT  19.117 1.728 24.008 1.752 ;
     RECT  23.569 3.408 24.008 4.536 ;
     RECT  18.904 7.68 24.008 7.704 ;
     RECT  24.008 1.728 24.304 23.772 ;
     RECT  24.037 25.776 24.509 25.8 ;
     RECT  24.785 23.904 24.869 23.928 ;
     RECT  25.669 23.328 25.877 23.352 ;
     RECT  24.304 3.408 26.273 4.392 ;
     RECT  26.437 25.776 26.525 25.8 ;
     RECT  27.269 23.904 27.353 23.928 ;
     RECT  26.273 3.84 27.565 4.392 ;
     RECT  28.069 25.776 28.505 25.8 ;
     RECT  27.565 3.84 29.041 4.488 ;
     RECT  28.933 23.904 29.045 23.928 ;
     RECT  24.304 1.728 29.408 1.752 ;
     RECT  29.041 3.696 29.408 4.488 ;
     RECT  24.304 7.68 29.408 7.704 ;
     RECT  29.408 1.728 29.512 23.772 ;
     RECT  29.512 1.728 29.704 23.502 ;
     RECT  29.701 25.776 29.873 25.8 ;
     RECT  30.524 23.952 30.611 23.976 ;
     RECT  29.704 3.408 30.769 4.392 ;
     RECT  30.769 3.408 30.809 4.488 ;
     RECT  31.333 23.904 31.853 23.928 ;
     RECT  32.197 24.48 32.357 24.504 ;
     RECT  30.809 3.408 33.113 3.432 ;
     RECT  30.809 4.416 33.325 4.488 ;
     RECT  33.325 3.936 34.369 4.488 ;
     RECT  29.704 1.728 34.808 1.752 ;
     RECT  34.369 3.6 34.808 4.488 ;
     RECT  29.704 7.68 34.808 7.704 ;
     RECT  34.808 1.728 34.912 23.772 ;
     RECT  34.912 1.728 35.104 23.502 ;
     RECT  35.104 1.728 36.397 1.752 ;
     RECT  32.965 25.776 36.461 25.8 ;
     RECT  35.104 3.6 36.605 4.488 ;
     RECT  37.069 0.576 37.153 0.6 ;
     RECT  36.605 3.984 38.041 4.488 ;
     RECT  37.093 23.904 38.189 23.928 ;
     RECT  38.252 5.952 38.293 5.976 ;
     RECT  38.293 5.952 38.339 6.12 ;
     RECT  38.041 3.408 38.771 4.488 ;
     RECT  38.771 3.408 38.801 4.392 ;
     RECT  39.581 23.904 39.665 23.928 ;
     RECT  37.925 1.728 40.208 1.752 ;
     RECT  38.801 3.408 40.208 4.152 ;
     RECT  38.339 6.096 40.208 6.12 ;
     RECT  35.104 7.68 40.208 7.704 ;
     RECT  38.725 22.752 40.208 22.776 ;
     RECT  40.208 1.728 40.312 23.772 ;
     RECT  40.069 25.776 40.403 25.8 ;
     RECT  40.312 1.728 40.457 23.502 ;
     RECT  40.457 2.418 40.504 23.502 ;
     RECT  41.137 0.576 41.267 0.6 ;
     RECT  40.504 22.752 41.285 22.776 ;
     RECT  41.221 24.48 41.429 24.504 ;
     RECT  40.504 4.128 42.001 4.152 ;
     RECT  41.957 23.904 42.041 23.928 ;
     RECT  42.001 3.936 42.133 4.152 ;
     RECT  42.133 3.216 42.709 4.152 ;
     RECT  42.709 3.216 42.797 4.248 ;
     RECT  42.797 3.312 43.049 4.248 ;
     RECT  42.853 25.776 43.049 25.8 ;
     RECT  43.049 3.312 43.517 4.152 ;
     RECT  41.957 1.728 43.697 1.752 ;
     RECT  43.621 23.904 43.877 23.928 ;
     RECT  44.444 25.104 44.531 25.128 ;
     RECT  43.517 3.408 44.533 4.152 ;
     RECT  44.485 0.576 44.569 0.6 ;
     RECT  44.533 2.832 44.725 4.152 ;
     RECT  44.521 23.376 45.233 23.4 ;
     RECT  44.989 0.096 45.299 0.12 ;
     RECT  45.233 23.376 45.317 23.928 ;
     RECT  44.725 2.784 45.608 4.152 ;
     RECT  40.504 6.096 45.608 6.12 ;
     RECT  40.504 7.68 45.608 7.704 ;
     RECT  45.317 23.376 45.608 23.772 ;
     RECT  45.608 2.148 45.712 23.772 ;
     RECT  45.712 2.148 45.904 23.502 ;
     RECT  45.961 1.728 46.163 1.752 ;
     RECT  45.997 25.104 46.163 25.128 ;
     RECT  45.904 3.408 46.649 4.2 ;
     RECT  46.649 3.84 46.901 4.2 ;
     RECT  46.789 0.576 46.931 0.6 ;
     RECT  46.885 25.776 47.081 25.8 ;
     RECT  47.749 23.904 47.873 23.928 ;
     RECT  48.409 22.8 48.493 22.824 ;
     RECT  47.717 2.832 48.737 2.856 ;
     RECT  46.901 3.84 49.489 4.152 ;
     RECT  49.489 3.408 49.921 4.152 ;
     RECT  48.517 25.776 50.501 25.8 ;
     RECT  47.473 1.728 51.008 1.752 ;
     RECT  49.921 2.832 51.008 4.152 ;
     RECT  45.904 6.096 51.008 6.12 ;
     RECT  45.904 7.68 51.008 7.704 ;
     RECT  50.093 23.376 51.008 23.4 ;
     RECT  51.008 1.728 51.059 23.772 ;
     RECT  50.821 25.104 51.059 25.128 ;
     RECT  51.059 2.148 51.112 23.772 ;
     RECT  51.112 2.418 51.304 23.502 ;
     RECT  51.793 0.096 51.923 0.12 ;
     RECT  51.304 4.128 52.837 4.248 ;
     RECT  51.877 25.776 52.841 25.8 ;
     RECT  52.837 22.8 52.921 22.824 ;
     RECT  52.837 4.128 52.981 5.112 ;
     RECT  52.981 3.216 53.093 5.112 ;
     RECT  53.093 3.84 53.123 5.112 ;
     RECT  53.477 23.904 53.561 23.928 ;
     RECT  53.123 3.936 53.705 5.112 ;
     RECT  53.705 3.936 54.709 4.92 ;
     RECT  54.709 3.696 54.713 4.92 ;
     RECT  54.713 3.696 54.805 3.72 ;
     RECT  54.277 23.376 54.865 23.4 ;
     RECT  55.133 23.904 55.217 23.928 ;
     RECT  54.805 3.216 56.077 3.72 ;
     RECT  52.621 1.728 56.408 1.752 ;
     RECT  56.077 2.88 56.408 3.72 ;
     RECT  54.713 4.896 56.408 4.92 ;
     RECT  51.304 6.096 56.408 6.12 ;
     RECT  51.304 7.68 56.408 7.704 ;
     RECT  56.408 1.728 56.512 23.772 ;
     RECT  56.512 1.728 56.704 23.502 ;
     RECT  55.909 25.776 56.909 25.8 ;
     RECT  56.704 23.376 57.587 23.4 ;
     RECT  58.405 23.904 58.709 23.928 ;
     RECT  56.704 2.88 58.777 3.72 ;
     RECT  56.704 4.896 58.777 4.92 ;
     RECT  59.101 23.376 59.219 23.4 ;
     RECT  58.777 2.88 59.249 4.92 ;
     RECT  60.037 25.776 60.149 25.8 ;
     RECT  60.421 23.904 60.581 23.928 ;
     RECT  59.249 3.312 60.949 4.92 ;
     RECT  56.704 1.728 61.189 1.752 ;
     RECT  60.949 2.784 61.189 4.92 ;
     RECT  61.153 25.104 61.331 25.128 ;
     RECT  60.805 22.176 61.621 22.2 ;
     RECT  61.628 24.528 61.715 24.552 ;
     RECT  61.189 1.728 61.808 4.92 ;
     RECT  56.704 6.096 61.808 6.12 ;
     RECT  56.704 7.68 61.808 7.704 ;
     RECT  61.621 21.504 61.808 22.2 ;
     RECT  61.808 1.728 61.912 23.772 ;
     RECT  61.621 25.728 62.099 25.752 ;
     RECT  61.912 1.728 62.104 23.502 ;
     RECT  62.104 3.312 62.201 4.92 ;
     RECT  62.377 25.776 62.483 25.8 ;
     RECT  62.104 21.504 62.993 22.2 ;
     RECT  62.104 1.728 63.097 1.752 ;
     RECT  62.201 3.312 63.277 3.336 ;
     RECT  63.277 3.312 63.317 3.432 ;
     RECT  62.993 21.504 63.317 21.528 ;
     RECT  63.097 1.104 63.347 1.752 ;
     RECT  63.301 23.904 63.685 23.928 ;
     RECT  63.685 23.856 63.853 23.928 ;
     RECT  63.853 23.424 63.857 23.928 ;
     RECT  63.317 3.408 63.925 3.432 ;
     RECT  62.201 4.416 63.925 4.92 ;
     RECT  63.857 23.424 63.925 23.448 ;
     RECT  63.601 25.104 64.211 25.128 ;
     RECT  63.925 3.408 64.259 4.92 ;
     RECT  63.925 23.376 64.259 23.448 ;
     RECT  64.549 24.48 64.757 24.504 ;
     RECT  64.609 22.752 64.892 22.776 ;
     RECT  64.259 4.416 65.221 4.92 ;
     RECT  62.104 6.096 65.221 6.12 ;
     RECT  64.892 22.128 65.317 22.776 ;
     RECT  65.317 21.648 65.401 22.776 ;
     RECT  63.347 1.728 65.509 1.752 ;
     RECT  64.259 3.408 65.509 3.432 ;
     RECT  65.221 4.416 65.509 6.12 ;
     RECT  65.509 3.408 65.593 6.12 ;
     RECT  65.401 21.648 66.161 23.4 ;
     RECT  65.593 3.696 66.197 6.12 ;
     RECT  66.181 25.776 66.521 25.8 ;
     RECT  66.161 21.984 66.565 23.4 ;
     RECT  66.197 3.696 66.661 5.064 ;
     RECT  66.565 21.984 66.701 23.928 ;
     RECT  66.701 21.984 66.995 23.832 ;
     RECT  65.509 1.728 67.208 2.28 ;
     RECT  66.661 3.504 67.208 5.064 ;
     RECT  66.197 6.096 67.208 6.12 ;
     RECT  62.104 7.68 67.208 7.704 ;
     RECT  66.995 21.984 67.208 23.772 ;
     RECT  67.208 1.728 67.504 23.772 ;
     RECT  67.504 21.12 67.781 23.772 ;
     RECT  67.781 21.12 67.825 21.144 ;
     RECT  67.504 2.88 67.852 6.12 ;
     RECT  67.781 22.8 68.077 23.772 ;
     RECT  68.077 23.376 68.197 23.772 ;
     RECT  67.417 25.056 68.285 25.08 ;
     RECT  68.197 23.376 68.291 23.928 ;
     RECT  67.852 2.88 68.429 5.112 ;
     RECT  68.291 23.568 68.483 23.928 ;
     RECT  68.429 3.168 68.524 5.112 ;
     RECT  68.524 3.168 68.573 3.336 ;
     RECT  68.524 4.416 68.825 5.112 ;
     RECT  68.483 23.904 69.061 23.928 ;
     RECT  67.504 7.68 69.185 7.704 ;
     RECT  69.061 23.904 69.221 24.504 ;
     RECT  67.504 1.728 69.445 1.752 ;
     RECT  68.573 3.312 69.865 3.336 ;
     RECT  68.825 4.416 69.865 4.68 ;
     RECT  69.445 1.728 69.925 1.848 ;
     RECT  69.925 1.728 70.001 2.232 ;
     RECT  69.865 3.312 70.001 4.68 ;
     RECT  69.221 23.904 70.013 23.928 ;
     RECT  70.001 0.528 70.085 0.552 ;
     RECT  70.001 1.728 70.085 4.68 ;
     RECT  70.085 1.728 70.229 2.232 ;
     RECT  70.085 3.312 70.513 4.68 ;
     RECT  70.693 7.44 70.777 7.464 ;
     RECT  70.513 3.312 70.883 5.064 ;
     RECT  70.883 4.416 70.949 5.064 ;
     RECT  70.693 25.776 71.057 25.8 ;
     RECT  70.309 24.48 71.077 24.504 ;
     RECT  70.229 1.728 71.165 1.848 ;
     RECT  70.949 4.512 71.221 5.064 ;
     RECT  67.852 6.096 71.221 6.12 ;
     RECT  71.077 23.904 71.237 24.504 ;
     RECT  71.221 4.512 71.267 6.12 ;
     RECT  70.883 3.312 71.917 3.336 ;
     RECT  71.267 4.512 71.917 5.544 ;
     RECT  71.305 23.376 72.305 23.4 ;
     RECT  71.237 24.48 72.305 24.504 ;
     RECT  72.305 23.376 72.317 24.504 ;
     RECT  72.317 23.376 72.389 23.928 ;
     RECT  72.325 21.504 72.449 21.528 ;
     RECT  71.165 1.728 72.608 1.752 ;
     RECT  71.917 3.312 72.608 5.544 ;
     RECT  72.449 21.504 72.608 21.672 ;
     RECT  72.389 23.376 72.608 23.772 ;
     RECT  72.469 25.776 72.755 25.8 ;
     RECT  72.608 1.728 72.904 23.772 ;
     RECT  72.904 21.504 73.217 23.772 ;
     RECT  73.217 22.176 73.573 23.772 ;
     RECT  72.904 3.408 73.577 5.544 ;
     RECT  73.573 22.176 73.793 24.504 ;
     RECT  73.577 3.456 74.099 5.544 ;
     RECT  73.793 22.176 74.099 23.928 ;
     RECT  74.099 4.512 74.149 5.544 ;
     RECT  74.099 23.376 74.233 23.928 ;
     RECT  74.099 22.176 74.725 22.344 ;
     RECT  74.689 25.056 74.773 25.08 ;
     RECT  74.099 3.456 75.116 3.48 ;
     RECT  74.149 4.512 75.116 5.688 ;
     RECT  75.116 3.456 75.203 5.688 ;
     RECT  74.233 23.424 75.203 23.928 ;
     RECT  75.203 4.608 75.233 5.688 ;
     RECT  75.157 25.104 75.251 25.128 ;
     RECT  74.725 21.696 75.341 22.344 ;
     RECT  75.203 3.456 75.625 3.48 ;
     RECT  75.625 3.36 75.665 3.48 ;
     RECT  75.203 23.904 76.453 23.928 ;
     RECT  75.233 4.608 76.745 5.544 ;
     RECT  76.453 23.904 76.961 24.504 ;
     RECT  77.564 24.528 77.651 24.552 ;
     RECT  72.904 1.728 78.008 1.752 ;
     RECT  75.665 3.36 78.008 3.384 ;
     RECT  76.745 4.656 78.008 5.544 ;
     RECT  77.221 22.224 78.008 22.248 ;
     RECT  77.929 0.096 78.131 0.12 ;
     RECT  78.085 25.776 78.185 25.8 ;
     RECT  78.008 1.728 78.304 23.928 ;
     RECT  78.304 23.568 79.237 23.928 ;
     RECT  78.304 22.368 79.265 22.392 ;
     RECT  79.237 23.568 79.297 24.504 ;
     RECT  78.304 3.552 79.657 5.544 ;
     RECT  78.304 1.728 79.717 1.752 ;
     RECT  79.657 2.832 79.769 5.544 ;
     RECT  79.717 1.728 79.909 1.848 ;
     RECT  79.909 1.728 80.147 2.28 ;
     RECT  79.297 23.376 80.381 24.504 ;
     RECT  80.381 24.48 80.597 24.504 ;
     RECT  80.147 1.728 80.957 1.8 ;
     RECT  80.869 21.648 81.137 21.672 ;
     RECT  80.381 23.376 81.277 23.4 ;
     RECT  81.277 22.8 81.349 23.4 ;
     RECT  79.769 3.408 81.425 5.544 ;
     RECT  81.349 22.8 81.457 23.928 ;
     RECT  81.493 21.744 81.781 21.768 ;
     RECT  81.457 22.752 81.781 23.928 ;
     RECT  80.957 1.728 81.785 1.752 ;
     RECT  81.781 21.744 82.117 23.928 ;
     RECT  82.076 2.256 82.163 2.28 ;
     RECT  82.117 21.744 82.307 24.504 ;
     RECT  82.307 21.744 82.321 22.248 ;
     RECT  82.307 23.568 82.325 24.504 ;
     RECT  81.425 3.504 82.573 5.544 ;
     RECT  82.573 3.408 82.885 5.544 ;
     RECT  82.609 25.104 83.027 25.128 ;
     RECT  82.885 3.312 83.269 5.544 ;
     RECT  82.861 1.728 83.408 1.752 ;
     RECT  83.269 2.832 83.408 5.544 ;
     RECT  82.321 21.696 83.408 22.248 ;
     RECT  82.325 23.568 83.408 23.928 ;
     RECT  83.408 1.728 83.704 23.928 ;
     RECT  83.704 22.8 83.981 23.928 ;
     RECT  83.704 2.832 84.089 5.544 ;
     RECT  83.704 1.728 85.273 1.752 ;
     RECT  83.981 23.568 85.273 23.928 ;
     RECT  84.877 22.224 85.345 22.248 ;
     RECT  85.273 23.376 85.345 23.928 ;
     RECT  85.345 22.224 85.427 23.928 ;
     RECT  85.427 22.224 85.429 22.824 ;
     RECT  85.273 1.728 85.525 1.8 ;
     RECT  85.429 22.224 85.777 22.248 ;
     RECT  85.525 1.728 86.033 2.232 ;
     RECT  85.427 23.904 86.069 23.928 ;
     RECT  86.033 2.208 86.204 2.232 ;
     RECT  86.204 2.208 86.291 2.28 ;
     RECT  86.533 0.576 86.675 0.6 ;
     RECT  84.089 3.408 86.869 5.544 ;
     RECT  85.777 22.176 86.915 22.248 ;
     RECT  86.869 3.36 87.253 5.544 ;
     RECT  86.245 24.48 87.761 24.504 ;
     RECT  87.073 23.376 87.857 23.4 ;
     RECT  87.541 0.096 87.923 0.12 ;
     RECT  87.857 23.376 88.769 23.928 ;
     RECT  87.013 1.728 88.808 1.752 ;
     RECT  87.253 3.312 88.808 5.544 ;
     RECT  86.915 22.176 88.808 22.2 ;
     RECT  88.769 23.376 88.808 23.772 ;
     RECT  88.808 1.728 88.912 23.772 ;
     RECT  88.912 1.728 89.104 23.502 ;
     RECT  89.104 2.832 89.417 5.544 ;
     RECT  89.449 0.096 89.555 0.12 ;
     RECT  89.104 21.648 89.596 21.672 ;
     RECT  89.104 22.8 89.747 23.304 ;
     RECT  89.125 25.776 89.993 25.8 ;
     RECT  89.747 22.8 90.281 22.824 ;
     RECT  90.341 25.056 90.425 25.08 ;
     RECT  89.417 3.552 90.517 5.544 ;
     RECT  90.476 0.048 90.563 0.072 ;
     RECT  90.517 2.88 90.565 5.544 ;
     RECT  90.565 2.784 90.611 5.544 ;
     RECT  90.611 2.784 90.677 4.536 ;
     RECT  90.757 24.48 90.893 24.504 ;
     RECT  91.141 21.552 91.228 21.576 ;
     RECT  91.213 22.896 91.393 22.92 ;
     RECT  91.484 25.104 91.571 25.128 ;
     RECT  90.677 3.408 91.717 4.536 ;
     RECT  90.611 5.52 91.717 5.544 ;
     RECT  91.393 22.8 91.753 22.92 ;
     RECT  91.753 22.8 91.933 23.4 ;
     RECT  89.104 1.728 91.964 1.752 ;
     RECT  91.964 1.728 92.051 2.28 ;
     RECT  91.933 22.8 92.081 23.496 ;
     RECT  92.005 25.776 92.153 25.8 ;
     RECT  91.717 3.408 92.156 5.544 ;
     RECT  92.156 3.312 92.753 5.544 ;
     RECT  92.357 21.648 92.773 21.672 ;
     RECT  92.773 21.648 92.909 22.152 ;
     RECT  92.909 21.648 93.089 21.672 ;
     RECT  92.753 2.832 93.097 5.544 ;
     RECT  92.081 23.376 93.149 23.496 ;
     RECT  93.149 23.376 93.625 23.928 ;
     RECT  93.625 23.376 93.709 24.504 ;
     RECT  92.051 1.728 93.98 1.752 ;
     RECT  93.98 1.728 94.208 2.28 ;
     RECT  93.097 3.312 94.208 5.544 ;
     RECT  93.709 23.376 94.208 23.976 ;
     RECT  94.208 1.728 94.451 23.976 ;
     RECT  94.451 1.728 94.504 23.592 ;
     RECT  94.741 25.104 94.835 25.128 ;
     RECT  94.504 23.376 95.641 23.592 ;
     RECT  95.641 23.376 95.725 23.928 ;
     RECT  94.504 21.12 95.857 21.144 ;
     RECT  95.857 21.12 95.965 21.96 ;
     RECT  95.725 23.376 95.965 23.496 ;
     RECT  95.965 21.12 96.041 23.496 ;
     RECT  96.029 25.056 96.113 25.08 ;
     RECT  96.041 22.8 96.227 23.496 ;
     RECT  96.227 22.8 96.323 23.4 ;
     RECT  96.253 25.776 96.371 25.848 ;
     RECT  96.041 21.12 96.545 21.672 ;
     RECT  96.545 21.648 96.581 21.672 ;
     RECT  96.371 25.776 96.653 25.8 ;
     RECT  96.323 23.376 96.899 23.4 ;
     RECT  96.793 0.096 96.947 0.12 ;
     RECT  96.86 24.528 96.947 24.552 ;
     RECT  94.504 3.312 97.109 5.544 ;
     RECT  97.109 2.832 97.193 5.544 ;
     RECT  97.285 22.128 97.481 22.152 ;
     RECT  97.193 3.312 97.733 5.544 ;
     RECT  97.669 24.48 97.909 24.504 ;
     RECT  97.733 3.408 98.273 5.544 ;
     RECT  97.909 23.376 98.453 24.504 ;
     RECT  98.273 3.936 98.489 5.544 ;
     RECT  94.504 1.728 98.521 1.752 ;
     RECT  98.453 23.376 98.597 23.832 ;
     RECT  98.521 1.728 98.605 1.848 ;
     RECT  98.597 23.376 98.737 23.4 ;
     RECT  98.605 1.728 99.608 1.752 ;
     RECT  98.489 3.936 99.608 5.448 ;
     RECT  99.301 21.552 99.608 21.576 ;
     RECT  98.737 22.8 99.608 23.4 ;
     RECT  99.608 1.728 99.712 23.772 ;
     RECT  99.712 1.728 99.904 23.502 ;
     RECT  99.904 3.312 100.019 5.208 ;
     RECT  99.904 22.8 100.019 22.824 ;
     RECT  99.904 21.648 100.217 21.672 ;
     RECT  99.781 24.48 100.325 24.504 ;
     RECT  100.549 25.056 100.649 25.08 ;
     RECT  100.933 22.752 101.017 22.776 ;
     RECT  99.904 1.728 101.393 1.752 ;
     RECT  101.393 1.728 101.477 1.8 ;
     RECT  101.401 21.648 101.485 21.672 ;
     RECT  101.797 23.904 101.981 23.928 ;
     RECT  100.019 3.456 102.089 5.208 ;
     RECT  101.477 1.728 102.517 1.752 ;
     RECT  102.181 24.48 102.557 24.504 ;
     RECT  102.517 1.728 102.611 2.28 ;
     RECT  102.524 23.376 102.611 23.4 ;
     RECT  102.089 3.552 103.133 5.208 ;
     RECT  103.133 3.552 103.237 3.576 ;
     RECT  103.381 23.952 103.475 23.976 ;
     RECT  103.045 22.128 103.489 22.152 ;
     RECT  103.237 3.408 103.525 3.576 ;
     RECT  103.489 22.128 103.849 22.824 ;
     RECT  103.813 25.056 103.961 25.08 ;
     RECT  103.525 3.312 104.149 3.576 ;
     RECT  103.133 4.896 104.245 5.208 ;
     RECT  104.149 3.312 104.389 3.768 ;
     RECT  104.245 4.848 104.389 5.208 ;
     RECT  103.849 22.128 104.677 22.872 ;
     RECT  104.677 21.648 104.869 22.872 ;
     RECT  102.611 1.728 105.008 1.752 ;
     RECT  104.389 3.312 105.008 5.208 ;
     RECT  104.869 21.504 105.008 22.872 ;
     RECT  104.869 25.776 105.107 25.8 ;
     RECT  105.008 1.728 105.304 23.772 ;
     RECT  105.304 2.832 105.365 5.208 ;
     RECT  105.304 21.504 105.437 21.528 ;
     RECT  105.304 23.568 105.443 23.772 ;
     RECT  105.445 23.904 105.884 23.928 ;
     RECT  105.884 23.904 105.971 23.976 ;
     RECT  105.304 1.728 106.013 1.752 ;
     RECT  105.365 3.408 106.121 5.208 ;
     RECT  105.685 0.096 106.739 0.12 ;
     RECT  105.971 23.904 107.045 23.928 ;
     RECT  106.121 3.696 107.201 5.208 ;
     RECT  107.045 23.808 107.516 23.928 ;
     RECT  107.516 23.376 107.603 23.928 ;
     RECT  107.521 3.408 108.169 3.432 ;
     RECT  107.053 1.728 108.173 1.752 ;
     RECT  107.603 23.856 108.389 23.928 ;
     RECT  108.169 2.88 108.668 3.432 ;
     RECT  108.668 2.256 108.773 3.432 ;
     RECT  108.493 22.704 108.773 22.728 ;
     RECT  108.773 22.704 108.857 22.824 ;
     RECT  108.773 2.256 109.109 3.48 ;
     RECT  108.805 21.648 109.217 21.672 ;
     RECT  109.141 23.376 109.331 23.4 ;
     RECT  108.701 24.48 109.397 24.504 ;
     RECT  109.109 3.408 109.573 3.48 ;
     RECT  107.201 4.512 109.573 5.208 ;
     RECT  109.169 1.728 110.293 1.8 ;
     RECT  109.573 22.224 110.329 22.248 ;
     RECT  109.925 23.904 110.329 23.928 ;
     RECT  110.293 1.728 110.408 2.28 ;
     RECT  109.573 3.408 110.408 5.208 ;
     RECT  110.329 22.224 110.408 23.928 ;
     RECT  110.408 1.728 110.585 23.928 ;
     RECT  110.585 1.728 110.704 23.502 ;
     RECT  110.704 3.84 110.729 5.208 ;
     RECT  110.704 21.648 110.819 23.448 ;
     RECT  110.704 1.728 110.867 2.28 ;
     RECT  110.819 23.28 110.963 23.448 ;
     RECT  110.963 23.376 111.061 23.448 ;
     RECT  110.821 24.48 111.089 24.504 ;
     RECT  110.729 3.936 111.197 5.208 ;
     RECT  111.197 3.936 111.692 5.16 ;
     RECT  110.819 21.648 111.737 22.152 ;
     RECT  111.061 23.424 111.779 23.448 ;
     RECT  111.692 3.744 112.261 5.16 ;
     RECT  112.261 3.408 112.316 5.16 ;
     RECT  112.316 3.408 112.403 5.448 ;
     RECT  112.403 3.408 112.741 5.112 ;
     RECT  112.741 2.832 112.781 5.112 ;
     RECT  112.781 2.832 112.825 4.92 ;
     RECT  112.069 23.904 112.837 23.928 ;
     RECT  112.777 21.12 112.861 21.144 ;
     RECT  112.837 23.904 112.921 24.504 ;
     RECT  112.921 23.376 113.027 24.504 ;
     RECT  112.825 3.408 113.069 4.92 ;
     RECT  113.027 23.904 113.177 24.504 ;
     RECT  112.445 22.176 113.249 22.2 ;
     RECT  113.177 23.904 113.393 23.928 ;
     RECT  113.069 4.512 113.717 4.92 ;
     RECT  113.069 3.408 113.921 3.432 ;
     RECT  114.284 0.048 114.371 0.072 ;
     RECT  110.867 1.728 114.469 1.752 ;
     RECT  113.921 2.832 114.469 3.432 ;
     RECT  114.433 22.224 114.469 22.248 ;
     RECT  114.469 21.648 114.659 22.248 ;
     RECT  114.469 1.728 114.689 3.432 ;
     RECT  114.659 21.648 114.853 21.672 ;
     RECT  115.037 0.528 115.121 0.552 ;
     RECT  113.717 4.56 115.189 4.92 ;
     RECT  113.701 25.056 115.553 25.08 ;
     RECT  115.153 23.376 115.621 23.4 ;
     RECT  115.621 22.8 115.717 23.4 ;
     RECT  114.689 1.728 115.808 1.752 ;
     RECT  114.689 2.832 115.808 3.432 ;
     RECT  115.189 4.56 115.808 4.968 ;
     RECT  114.853 21.6 115.808 21.672 ;
     RECT  115.717 22.8 115.808 23.976 ;
     RECT  115.808 1.728 116.104 23.976 ;
     RECT  116.104 23.952 116.165 23.976 ;
     RECT  116.089 25.776 116.173 25.8 ;
     RECT  116.104 1.728 116.245 4.968 ;
     RECT  116.245 3.312 116.819 4.968 ;
     RECT  116.104 22.8 116.819 22.824 ;
     RECT  116.104 21.648 116.921 21.672 ;
     RECT  116.819 3.84 117.173 4.968 ;
     RECT  116.945 24.48 117.341 24.504 ;
     RECT  117.341 23.904 117.421 24.504 ;
     RECT  117.421 23.376 117.425 24.504 ;
     RECT  117.173 3.936 117.817 4.968 ;
     RECT  117.817 3.936 117.901 5.112 ;
     RECT  117.425 23.376 117.997 23.4 ;
     RECT  116.245 1.728 118.037 2.28 ;
     RECT  117.901 3.936 118.177 4.968 ;
     RECT  117.425 24.48 118.289 24.504 ;
     RECT  117.997 22.8 118.429 23.4 ;
     RECT  118.177 3.84 118.501 4.968 ;
     RECT  118.536 0.576 118.643 0.6 ;
     RECT  118.597 25.776 118.757 25.8 ;
     RECT  118.981 21.6 119.077 21.624 ;
     RECT  118.501 3.408 119.081 4.968 ;
     RECT  119.077 21.6 119.081 21.672 ;
     RECT  118.429 22.8 119.123 23.448 ;
     RECT  119.123 22.8 119.267 23.4 ;
     RECT  119.081 21.648 119.297 21.672 ;
     RECT  119.365 25.056 119.585 25.08 ;
     RECT  119.689 22.224 119.801 22.248 ;
     RECT  119.081 3.408 119.845 4.92 ;
     RECT  119.845 3.36 120.089 4.92 ;
     RECT  119.845 25.776 120.125 25.8 ;
     RECT  119.267 23.376 120.613 23.4 ;
     RECT  120.613 23.376 120.845 23.928 ;
     RECT  120.089 3.648 121.093 4.92 ;
     RECT  121.093 3.648 121.201 5.16 ;
     RECT  118.037 1.728 121.208 1.752 ;
     RECT  121.201 3.312 121.208 5.16 ;
     RECT  120.805 21.504 121.208 21.528 ;
     RECT  120.845 23.376 121.208 23.772 ;
     RECT  121.208 1.728 121.312 23.772 ;
     RECT  121.312 1.728 121.504 23.592 ;
     RECT  121.477 25.776 121.58 25.8 ;
     RECT  121.58 25.68 121.619 25.8 ;
     RECT  121.619 25.68 121.667 25.704 ;
     RECT  121.504 21.504 121.673 21.96 ;
     RECT  121.673 21.504 121.853 21.672 ;
     RECT  121.853 21.504 121.997 21.624 ;
     RECT  121.504 23.376 122.195 23.592 ;
     RECT  121.504 1.728 122.291 2.28 ;
     RECT  121.997 21.504 122.357 21.576 ;
     RECT  121.504 3.312 122.497 3.432 ;
     RECT  121.504 4.512 122.497 5.016 ;
     RECT  122.357 21.552 122.537 21.576 ;
     RECT  122.497 3.312 122.741 5.016 ;
     RECT  122.195 23.376 122.819 23.448 ;
     RECT  122.819 23.376 122.821 23.4 ;
     RECT  122.741 3.312 122.825 5.112 ;
     RECT  121.504 6.24 123.041 6.264 ;
     RECT  122.825 3.312 123.299 4.92 ;
     RECT  123.299 3.888 123.401 4.92 ;
     RECT  122.629 25.776 123.509 25.8 ;
     RECT  123.401 3.888 123.587 3.912 ;
     RECT  122.821 22.8 123.587 23.4 ;
     RECT  123.493 21.648 123.725 21.672 ;
     RECT  123.587 22.8 124.229 22.824 ;
     RECT  123.877 23.856 124.7 23.928 ;
     RECT  123.401 4.896 124.837 4.92 ;
     RECT  124.405 3.84 124.909 3.864 ;
     RECT  124.837 4.848 124.909 4.92 ;
     RECT  124.7 23.232 125.065 23.928 ;
     RECT  125.065 23.904 125.084 23.928 ;
     RECT  125.084 23.904 125.597 23.976 ;
     RECT  122.291 1.728 125.845 1.752 ;
     RECT  125.845 1.104 126.035 1.752 ;
     RECT  125.737 22.8 126.205 22.824 ;
     RECT  125.989 24.48 126.533 24.504 ;
     RECT  126.035 1.728 126.608 1.752 ;
     RECT  124.909 3.84 126.608 4.92 ;
     RECT  125.941 21.696 126.608 21.72 ;
     RECT  126.205 22.8 126.608 23.4 ;
     RECT  126.608 1.728 126.904 23.772 ;
     RECT  126.757 25.776 127.043 25.8 ;
     RECT  126.904 3.456 127.145 4.92 ;
     RECT  126.904 21.648 127.181 21.72 ;
     RECT  127.181 21.696 127.577 21.72 ;
     RECT  127.141 25.056 127.577 25.08 ;
     RECT  126.904 1.728 127.667 2.28 ;
     RECT  127.145 3.456 128.005 3.48 ;
     RECT  126.904 22.8 128.041 22.824 ;
     RECT  127.601 23.904 128.041 23.928 ;
     RECT  128.041 22.8 128.243 23.928 ;
     RECT  127.145 4.8 128.396 4.92 ;
     RECT  128.005 2.832 128.435 3.48 ;
     RECT  128.243 23.904 128.441 23.928 ;
     RECT  128.396 4.8 128.483 5.112 ;
     RECT  128.243 22.8 128.483 22.824 ;
     RECT  128.197 21.648 128.657 21.672 ;
     RECT  128.753 25.776 128.837 25.8 ;
     RECT  128.435 3.456 129.305 3.48 ;
     RECT  128.483 4.8 129.409 4.92 ;
     RECT  129.409 3.888 129.917 4.92 ;
     RECT  129.985 23.376 130.163 23.4 ;
     RECT  129.637 25.056 130.313 25.08 ;
     RECT  129.917 3.888 130.345 4.584 ;
     RECT  127.667 1.728 130.417 1.752 ;
     RECT  130.417 1.728 130.547 1.848 ;
     RECT  130.345 3.072 130.565 4.584 ;
     RECT  129.253 22.176 130.745 22.2 ;
     RECT  130.547 1.728 131.507 1.752 ;
     RECT  130.885 23.904 131.681 23.928 ;
     RECT  130.565 3.072 132.008 3.432 ;
     RECT  130.565 4.464 132.008 4.584 ;
     RECT  131.929 0.096 132.275 0.12 ;
     RECT  132.008 2.148 132.304 23.772 ;
     RECT  132.229 25.776 132.509 25.8 ;
     RECT  132.997 23.904 133.373 23.928 ;
     RECT  133.669 25.776 133.769 25.8 ;
     RECT  134.089 22.8 134.201 22.824 ;
     RECT  134.396 23.376 134.483 23.4 ;
     RECT  132.304 3.408 134.921 4.488 ;
     RECT  134.921 4.464 135.101 4.488 ;
     RECT  135.205 25.776 135.533 25.8 ;
     RECT  134.921 3.408 136.501 3.432 ;
     RECT  135.953 23.904 136.793 23.928 ;
     RECT  132.997 1.728 137.408 1.752 ;
     RECT  136.501 3.408 137.408 4.008 ;
     RECT  137.408 1.728 137.512 23.772 ;
     RECT  137.512 1.728 137.704 23.502 ;
     RECT  137.413 25.776 138.305 25.8 ;
     RECT  137.704 3.408 139.021 3.912 ;
     RECT  139.021 3.408 139.061 3.96 ;
     RECT  139.453 25.104 139.667 25.128 ;
     RECT  139.733 2.832 139.817 2.856 ;
     RECT  139.061 3.888 139.889 3.96 ;
     RECT  139.993 22.8 140.141 22.824 ;
     RECT  138.949 23.904 140.249 23.928 ;
     RECT  139.889 3.888 140.933 3.912 ;
     RECT  137.704 1.728 141.221 1.752 ;
     RECT  140.389 25.056 141.365 25.08 ;
     RECT  141.893 1.152 141.977 1.176 ;
     RECT  141.925 21.552 142.012 21.576 ;
     RECT  141.361 0.096 142.739 0.12 ;
     RECT  141.649 22.752 142.739 22.776 ;
    LAYER M5 ;
     RECT  1.104 0.016 142.728 0.131 ;
     RECT  1.104 0.131 44.52 0.611 ;
     RECT  46.128 0.131 51.048 0.611 ;
     RECT  133.008 0.131 141.96 1.187 ;
     RECT  1.104 0.611 36.36 1.763 ;
     RECT  37.968 0.611 40.392 1.763 ;
     RECT  42 0.611 43.656 1.763 ;
     RECT  46.128 0.611 46.152 1.763 ;
     RECT  47.76 0.611 51.048 1.763 ;
     RECT  52.656 0.131 105.96 1.763 ;
     RECT  107.088 0.131 131.496 1.763 ;
     RECT  133.008 1.187 141.192 1.763 ;
     RECT  79.728 1.763 80.904 1.811 ;
     RECT  85.392 1.763 86.28 1.811 ;
     RECT  101.424 1.763 101.448 1.811 ;
     RECT  109.968 1.763 110.856 1.811 ;
     RECT  69.456 1.763 70.056 1.859 ;
     RECT  71.088 1.763 71.112 1.859 ;
     RECT  79.728 1.811 80.136 1.859 ;
     RECT  98.544 1.763 98.568 1.859 ;
     RECT  130.512 1.763 130.536 1.859 ;
     RECT  51 1.763 51.048 2.137 ;
     RECT  40.2 1.763 40.392 2.151 ;
     RECT  51 2.137 51.12 2.151 ;
     RECT  1.104 1.763 19.08 2.291 ;
     RECT  66.576 1.763 68.232 2.291 ;
     RECT  80.112 1.859 80.136 2.291 ;
     RECT  82.128 1.763 83.712 2.291 ;
     RECT  85.536 1.811 86.28 2.291 ;
     RECT  92.016 1.763 92.04 2.291 ;
     RECT  94.032 1.763 94.512 2.291 ;
     RECT  102.576 1.763 102.6 2.291 ;
     RECT  110.304 1.811 110.856 2.291 ;
     RECT  121.2 1.763 122.28 2.291 ;
     RECT  126.6 1.763 128.424 2.291 ;
     RECT  45.6 2.137 45.912 2.773 ;
     RECT  61.296 1.763 62.112 2.773 ;
     RECT  90.528 1.763 90.552 2.773 ;
     RECT  44.736 2.773 45.912 2.821 ;
     RECT  51 2.151 51.312 2.821 ;
     RECT  88.8 1.763 89.112 2.821 ;
     RECT  114.336 1.763 117.72 2.821 ;
     RECT  128.4 2.291 128.424 2.867 ;
     RECT  1.2 2.291 19.08 2.915 ;
     RECT  90.528 2.773 90.6 2.915 ;
     RECT  108.336 1.763 108.84 2.915 ;
     RECT  66.96 2.291 68.232 3.157 ;
     RECT  69.936 1.859 70.056 3.301 ;
     RECT  92.784 2.821 93.048 3.301 ;
     RECT  94.2 2.291 94.512 3.301 ;
     RECT  97.152 2.821 97.176 3.301 ;
     RECT  99.6 1.763 99.912 3.301 ;
     RECT  87.264 3.301 87.288 3.349 ;
     RECT  92.208 3.301 94.512 3.349 ;
     RECT  112.752 2.821 112.776 3.397 ;
     RECT  113.952 2.821 117.72 3.397 ;
     RECT  121.2 2.291 121.992 3.397 ;
     RECT  44.544 2.821 45.912 3.443 ;
     RECT  49.968 2.821 51.312 3.443 ;
     RECT  60.96 2.773 62.112 3.443 ;
     RECT  110.304 2.291 110.712 3.443 ;
     RECT  108.768 2.915 108.84 3.491 ;
     RECT  65.52 1.763 65.544 3.685 ;
     RECT  66.96 3.157 68.376 3.685 ;
     RECT  82.512 2.291 83.712 3.733 ;
     RECT  90.576 2.915 90.6 3.733 ;
     RECT  92.208 3.349 95.496 3.733 ;
     RECT  103.536 3.301 103.56 3.733 ;
     RECT  105 1.763 105.312 3.733 ;
     RECT  112.272 3.397 112.776 3.733 ;
     RECT  52.992 3.205 53.016 3.829 ;
     RECT  119.856 3.349 119.88 3.829 ;
     RECT  126.6 2.291 126.912 3.829 ;
     RECT  47.76 2.821 48.456 3.875 ;
     RECT  88.8 2.821 89.4 3.877 ;
     RECT  90.576 3.733 95.496 3.877 ;
     RECT  113.952 3.397 118.536 3.877 ;
     RECT  123.264 3.301 123.288 3.877 ;
     RECT  125.904 3.829 126.912 3.877 ;
     RECT  42.144 3.205 42.168 3.925 ;
     RECT  65.52 3.685 68.376 3.925 ;
     RECT  99.6 3.301 100.008 3.925 ;
     RECT  113.952 3.877 118.872 3.925 ;
     RECT  119.856 3.829 119.976 3.925 ;
     RECT  130.128 3.877 130.152 3.925 ;
     RECT  139.776 2.821 139.8 3.971 ;
     RECT  1.2 2.915 17.592 4.019 ;
     RECT  42.144 3.925 42.744 4.019 ;
     RECT  69.936 3.301 71.352 4.019 ;
     RECT  80.544 3.397 80.568 4.117 ;
     RECT  99.504 3.925 100.008 4.117 ;
     RECT  42.72 4.019 42.744 4.259 ;
     RECT  63.936 3.925 63.96 4.261 ;
     RECT  72.6 1.763 72.912 4.261 ;
     RECT  74.064 3.877 74.088 4.261 ;
     RECT  80.544 4.117 80.808 4.261 ;
     RECT  82.272 3.733 84.456 4.261 ;
     RECT  88.8 3.877 95.496 4.261 ;
     RECT  96.816 3.301 97.176 4.261 ;
     RECT  103.536 3.733 105.312 4.261 ;
     RECT  111.744 3.733 112.776 4.261 ;
     RECT  113.952 3.925 119.976 4.261 ;
     RECT  17.28 4.019 17.592 4.405 ;
     RECT  18.6 2.915 19.08 4.405 ;
     RECT  38.736 4.357 38.76 4.453 ;
     RECT  38.304 4.453 38.76 4.499 ;
     RECT  70.656 4.019 71.352 4.501 ;
     RECT  72.6 4.261 74.088 4.501 ;
     RECT  75.168 3.925 75.192 4.501 ;
     RECT  79.488 3.541 79.512 4.501 ;
     RECT  80.544 4.261 81 4.501 ;
     RECT  88.8 4.261 97.176 4.501 ;
     RECT  98.592 4.117 100.008 4.501 ;
     RECT  108.768 3.491 108.792 4.501 ;
     RECT  61.056 3.443 62.112 4.595 ;
     RECT  88.8 4.501 100.008 4.595 ;
     RECT  108.768 4.501 109.32 4.595 ;
     RECT  111.744 4.261 119.976 4.595 ;
     RECT  130.128 3.925 130.536 4.595 ;
     RECT  85.536 2.291 85.56 4.643 ;
     RECT  111.744 4.595 116.808 4.643 ;
     RECT  1.2 4.019 15.96 4.645 ;
     RECT  17.28 4.405 19.08 4.691 ;
     RECT  114.48 4.643 116.808 4.691 ;
     RECT  97.968 4.595 100.008 4.787 ;
     RECT  114.528 4.691 116.808 4.787 ;
     RECT  79.488 4.501 81 4.837 ;
     RECT  82.032 4.261 84.456 4.837 ;
     RECT  79.488 4.837 84.456 4.883 ;
     RECT  124.992 3.877 126.912 4.883 ;
     RECT  110.4 3.443 110.712 4.885 ;
     RECT  111.744 4.643 113.016 4.885 ;
     RECT  121.2 3.397 122.184 4.885 ;
     RECT  52.992 3.829 53.112 4.931 ;
     RECT  70.656 4.501 75.192 5.075 ;
     RECT  1.056 4.645 15.96 5.077 ;
     RECT  17.28 4.691 19.032 5.077 ;
     RECT  121.104 4.885 122.184 5.077 ;
     RECT  123.264 3.877 123.576 5.077 ;
     RECT  79.584 4.883 84.456 5.125 ;
     RECT  121.104 5.077 123.576 5.171 ;
     RECT  65.52 3.925 68.472 5.219 ;
     RECT  97.968 4.787 98.616 5.459 ;
     RECT  110.4 4.885 113.016 5.459 ;
     RECT  38.304 4.499 38.328 5.987 ;
     RECT  1.056 5.077 19.032 6.085 ;
     RECT  71.232 5.075 75.192 6.085 ;
     RECT  1.008 6.085 19.032 7.187 ;
     RECT  1.008 7.187 15.864 7.429 ;
     RECT  70.704 6.085 75.192 7.475 ;
     RECT  0.192 7.429 15.864 8.627 ;
     RECT  6.144 8.627 15.864 9.155 ;
     RECT  6.144 9.155 8.112 11.411 ;
     RECT  0.192 8.627 5.016 13.043 ;
     RECT  9.216 9.155 15.864 14.821 ;
     RECT  6.144 11.411 6.792 18.757 ;
     RECT  1.008 13.043 5.016 19.621 ;
     RECT  6.096 18.757 6.792 19.621 ;
     RECT  1.008 19.621 6.792 19.957 ;
     RECT  7.8 11.411 8.112 19.957 ;
     RECT  1.008 19.957 8.112 20.053 ;
     RECT  9.12 14.821 15.864 20.053 ;
     RECT  1.008 20.053 15.864 21.155 ;
     RECT  112.8 5.459 113.016 21.155 ;
     RECT  61.8 4.595 62.112 21.493 ;
     RECT  118.848 4.595 119.976 21.493 ;
     RECT  121.2 5.171 123.576 21.493 ;
     RECT  91.392 4.595 96.888 21.541 ;
     RECT  99.6 4.787 100.008 21.541 ;
     RECT  66.096 5.219 68.472 21.637 ;
     RECT  99.312 21.541 100.008 21.637 ;
     RECT  109.296 4.595 109.32 21.637 ;
     RECT  114.624 4.787 116.808 21.637 ;
     RECT  126.24 4.883 126.912 21.637 ;
     RECT  128.448 5.077 128.472 21.637 ;
     RECT  124.992 4.883 125.016 21.685 ;
     RECT  126.24 21.637 127.032 21.685 ;
     RECT  63.936 4.261 64.248 22.117 ;
     RECT  65.328 21.637 68.472 22.117 ;
     RECT  91.152 21.541 96.888 22.117 ;
     RECT  97.968 5.459 97.992 22.117 ;
     RECT  103.536 4.261 105.432 22.117 ;
     RECT  61.632 21.493 62.112 22.165 ;
     RECT  86.88 3.349 87.288 22.165 ;
     RECT  110.4 5.459 111.768 22.165 ;
     RECT  112.992 21.155 113.016 22.165 ;
     RECT  128.208 21.637 128.472 22.165 ;
     RECT  130.128 4.595 130.152 22.165 ;
     RECT  78 1.763 78.312 22.213 ;
     RECT  108.816 21.637 109.32 22.213 ;
     RECT  110.4 22.165 113.016 22.213 ;
     RECT  79.584 5.125 85.416 22.259 ;
     RECT  20.016 22.165 20.04 22.741 ;
     RECT  21.552 22.645 21.576 22.741 ;
     RECT  40.2 2.151 40.512 22.741 ;
     RECT  99.312 21.637 100.2 22.741 ;
     RECT  101.424 21.637 101.448 22.741 ;
     RECT  141.936 21.541 141.96 22.741 ;
     RECT  63.936 22.117 68.472 22.787 ;
     RECT  17.28 7.187 19.032 22.835 ;
     RECT  48.432 3.875 48.456 22.835 ;
     RECT  52.848 5.077 52.872 22.835 ;
     RECT  79.584 22.259 82.296 22.835 ;
     RECT  88.8 4.595 90.024 22.835 ;
     RECT  103.056 22.117 105.432 22.835 ;
     RECT  108.816 22.213 113.016 22.835 ;
     RECT  114.48 21.637 116.808 22.835 ;
     RECT  124.992 21.685 127.032 22.835 ;
     RECT  128.208 22.165 130.536 22.835 ;
     RECT  104.16 22.835 105.432 22.883 ;
     RECT  91.152 22.117 97.992 22.931 ;
     RECT  124.992 22.835 125.016 23.221 ;
     RECT  1.008 21.155 15.528 23.315 ;
     RECT  88.8 22.835 89.736 23.315 ;
     RECT  1.056 23.315 15.528 23.365 ;
     RECT  17.28 22.835 18.912 23.365 ;
     RECT  54.816 3.205 54.84 23.365 ;
     RECT  56.4 1.763 56.712 23.365 ;
     RECT  88.8 23.315 89.544 23.365 ;
     RECT  92.208 22.931 97.992 23.365 ;
     RECT  99.312 22.741 101.448 23.365 ;
     RECT  103.056 22.835 103.08 23.365 ;
     RECT  124.848 23.221 125.016 23.365 ;
     RECT  44.736 3.443 45.912 23.411 ;
     RECT  50.112 3.443 51.312 23.411 ;
     RECT  71.328 7.475 75.192 23.411 ;
     RECT  86.64 22.165 87.288 23.411 ;
     RECT  92.208 23.365 101.448 23.411 ;
     RECT  109.296 22.835 113.016 23.411 ;
     RECT  117.84 4.595 117.864 23.411 ;
     RECT  118.848 21.493 123.576 23.411 ;
     RECT  126.24 22.835 127.032 23.411 ;
     RECT  129.264 22.835 130.536 23.411 ;
     RECT  1.056 23.365 15.912 23.413 ;
     RECT  17.136 23.365 18.912 23.413 ;
     RECT  63.936 22.787 66.12 23.459 ;
     RECT  72.336 23.411 75.192 23.459 ;
     RECT  118.992 23.411 119.112 23.459 ;
     RECT  120.24 23.411 123.576 23.459 ;
     RECT  1.056 23.413 18.912 23.603 ;
     RECT  72.336 23.459 74.616 23.603 ;
     RECT  29.4 1.763 29.712 23.769 ;
     RECT  34.8 1.763 35.112 23.769 ;
     RECT  45.264 23.411 45.912 23.769 ;
     RECT  51 23.411 51.312 23.769 ;
     RECT  56.4 23.365 57.576 23.769 ;
     RECT  60.816 22.165 62.952 23.769 ;
     RECT  137.4 1.763 137.712 23.769 ;
     RECT  24 1.763 24.312 23.783 ;
     RECT  29.4 23.769 29.52 23.783 ;
     RECT  34.8 23.769 34.92 23.783 ;
     RECT  40.08 22.741 40.512 23.783 ;
     RECT  45.264 23.769 45.72 23.783 ;
     RECT  51 23.769 51.12 23.783 ;
     RECT  56.4 23.769 56.52 23.783 ;
     RECT  60.816 23.769 61.92 23.783 ;
     RECT  67.104 22.787 68.472 23.783 ;
     RECT  132 2.137 132.312 23.783 ;
     RECT  137.4 23.769 137.52 23.783 ;
     RECT  64.944 23.459 66.12 23.797 ;
     RECT  107.568 23.365 107.592 23.797 ;
     RECT  62.928 23.769 62.952 23.845 ;
     RECT  107.088 23.797 107.592 23.845 ;
     RECT  123.504 23.459 123.576 23.845 ;
     RECT  124.752 23.365 125.016 23.845 ;
     RECT  1.104 23.603 18.912 23.893 ;
     RECT  20.016 22.741 21.576 23.893 ;
     RECT  25.68 23.317 25.704 23.893 ;
     RECT  38.736 22.741 38.76 23.893 ;
     RECT  40.08 23.783 40.104 23.893 ;
     RECT  54.288 23.365 54.84 23.893 ;
     RECT  57.552 23.769 57.576 23.893 ;
     RECT  59.184 23.365 59.208 23.893 ;
     RECT  60.816 23.783 61.704 23.893 ;
     RECT  68.208 23.783 68.472 23.893 ;
     RECT  77.232 22.213 78.312 23.893 ;
     RECT  79.584 22.835 81.384 23.893 ;
     RECT  83.4 22.259 85.416 23.893 ;
     RECT  86.64 23.411 86.664 23.893 ;
     RECT  88.272 23.365 89.544 23.893 ;
     RECT  92.4 23.411 101.448 23.893 ;
     RECT  102.576 23.365 103.08 23.893 ;
     RECT  104.304 22.883 105.432 23.893 ;
     RECT  107.088 23.845 108.36 23.893 ;
     RECT  109.584 23.411 113.016 23.893 ;
     RECT  114.48 22.835 116.616 23.893 ;
     RECT  123.504 23.845 125.016 23.893 ;
     RECT  126.6 23.411 127.032 23.893 ;
     RECT  128.208 22.835 128.232 23.893 ;
     RECT  129.264 23.411 129.288 23.893 ;
     RECT  130.512 23.411 130.536 23.893 ;
     RECT  31.344 23.893 31.368 23.941 ;
     RECT  92.4 23.893 103.08 23.941 ;
     RECT  104.304 23.893 108.36 23.941 ;
     RECT  30.576 23.941 31.368 24.469 ;
     RECT  42 23.893 42.024 24.469 ;
     RECT  62.928 23.845 63.72 24.469 ;
     RECT  64.944 23.797 66.984 24.469 ;
     RECT  68.208 23.893 69.864 24.469 ;
     RECT  71.088 23.893 71.112 24.469 ;
     RECT  72.336 23.603 74.376 24.469 ;
     RECT  75.6 23.893 86.664 24.469 ;
     RECT  87.888 23.893 89.544 24.469 ;
     RECT  91.152 22.931 91.176 24.469 ;
     RECT  92.4 23.941 108.36 24.469 ;
     RECT  109.584 23.893 113.256 24.469 ;
     RECT  114.48 23.893 117.384 24.469 ;
     RECT  118.992 23.459 119.016 24.469 ;
     RECT  123.504 23.893 125.544 24.469 ;
     RECT  126.6 23.893 129.288 24.469 ;
     RECT  62.928 24.469 66.984 25.045 ;
     RECT  68.208 24.469 74.376 25.045 ;
     RECT  75.6 24.469 89.544 25.045 ;
     RECT  90.768 24.469 91.176 25.045 ;
     RECT  92.4 24.469 113.256 25.045 ;
     RECT  114.48 24.469 119.016 25.045 ;
     RECT  120.24 23.459 122.28 25.045 ;
     RECT  123.504 24.469 129.288 25.045 ;
     RECT  130.512 23.893 131.496 25.045 ;
     RECT  141.936 22.741 142.728 25.045 ;
     RECT  43.632 23.893 43.656 25.093 ;
     RECT  45.264 23.783 45.288 25.093 ;
     RECT  62.928 25.045 91.176 25.093 ;
     RECT  92.4 25.045 122.28 25.093 ;
     RECT  138.96 23.893 138.984 25.093 ;
     RECT  140.4 25.045 142.728 25.093 ;
     RECT  60.432 23.893 61.704 25.717 ;
     RECT  62.928 25.093 122.28 25.717 ;
     RECT  1.104 23.893 23.208 25.765 ;
     RECT  24.816 23.893 25.704 25.765 ;
     RECT  27.312 23.893 27.336 25.765 ;
     RECT  28.944 23.893 28.968 25.765 ;
     RECT  30.576 24.469 32.232 25.765 ;
     RECT  37.104 23.893 40.104 25.765 ;
     RECT  41.232 24.469 42.024 25.765 ;
     RECT  43.632 25.093 46.152 25.765 ;
     RECT  47.76 23.893 47.784 25.765 ;
     RECT  51.024 25.093 51.048 25.765 ;
     RECT  53.52 23.893 55.176 25.765 ;
     RECT  57.552 23.893 59.208 25.765 ;
     RECT  60.432 25.717 122.28 25.765 ;
     RECT  123.504 25.045 131.496 25.765 ;
     RECT  133.008 23.893 133.032 25.765 ;
     RECT  134.448 23.365 134.472 25.765 ;
     RECT  135.984 23.893 136.68 25.765 ;
     RECT  138.96 25.093 142.728 25.765 ;
     RECT  1.104 25.765 142.728 25.872 ;
  END
END ot_s81_hc_ctrn_own_e
END LIBRARY
